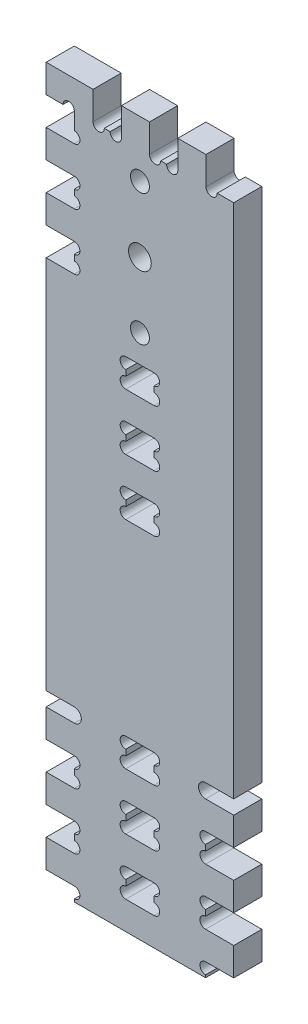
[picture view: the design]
ISO-10303-21;
HEADER;
FILE_DESCRIPTION(('STEP AP214'),'2;1');
FILE_NAME('part.step','',(''),(''),'','','');
FILE_SCHEMA(('AUTOMOTIVE_DESIGN { 1 0 10303 214 1 1 1 1 }'));
ENDSEC;
DATA;
#1=APPLICATION_CONTEXT('core data for automotive mechanical design processes');
#2=APPLICATION_PROTOCOL_DEFINITION('international standard','automotive_design',2000,#1);
#3=PRODUCT_CONTEXT('',#1,'mechanical');
#4=PRODUCT('Part','Part','',(#3));
#5=PRODUCT_RELATED_PRODUCT_CATEGORY('part','',(#4));
#6=PRODUCT_DEFINITION_FORMATION('','',#4);
#7=PRODUCT_DEFINITION_CONTEXT('part definition',#1,'design');
#8=PRODUCT_DEFINITION('design','',#6,#7);
#9=PRODUCT_DEFINITION_SHAPE('','',#8);
#10=(LENGTH_UNIT() NAMED_UNIT(*) SI_UNIT(.MILLI.,.METRE.));
#11=(NAMED_UNIT(*) PLANE_ANGLE_UNIT() SI_UNIT($,.RADIAN.));
#12=(NAMED_UNIT(*) SI_UNIT($,.STERADIAN.) SOLID_ANGLE_UNIT());
#13=UNCERTAINTY_MEASURE_WITH_UNIT(LENGTH_MEASURE(1.E-05),#10,'distance_accuracy_value','');
#14=(GEOMETRIC_REPRESENTATION_CONTEXT(3) GLOBAL_UNCERTAINTY_ASSIGNED_CONTEXT((#13)) GLOBAL_UNIT_ASSIGNED_CONTEXT((#10,
#11,#12)) REPRESENTATION_CONTEXT('',''));
#15=CARTESIAN_POINT('',(0.,0.,0.));
#16=DIRECTION('',(0.,0.,1.));
#17=DIRECTION('',(1.,0.,0.));
#18=AXIS2_PLACEMENT_3D('',#15,#16,#17);
#19=CARTESIAN_POINT('',(15.,86.35,15.));
#20=DIRECTION('',(0.,0.,1.));
#21=DIRECTION('',(1.,0.,0.));
#22=AXIS2_PLACEMENT_3D('',#19,#20,#21);
#23=PLANE('',#22);
#24=CARTESIAN_POINT('',(50.,315.270539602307,15.));
#25=DIRECTION('',(0.,0.,1.));
#26=DIRECTION('',(1.,0.,0.));
#27=AXIS2_PLACEMENT_3D('',#24,#25,#26);
#28=CIRCLE('',#27,6.05000000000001);
#29=CARTESIAN_POINT('',(56.05,315.270539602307,15.));
#30=VERTEX_POINT('',#29);
#31=EDGE_CURVE('E1719',#30,#30,#28,.T.);
#32=ORIENTED_EDGE('',*,*,#31,.F.);
#33=EDGE_LOOP('',(#32));
#34=FACE_BOUND('',#33,.T.);
#35=CARTESIAN_POINT('',(50.,280.270515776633,15.));
#36=DIRECTION('',(0.,0.,1.));
#37=DIRECTION('',(1.,0.,0.));
#38=AXIS2_PLACEMENT_3D('',#35,#36,#37);
#39=CIRCLE('',#38,5.05000000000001);
#40=CARTESIAN_POINT('',(55.05,280.270515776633,15.));
#41=VERTEX_POINT('',#40);
#42=EDGE_CURVE('E1714',#41,#41,#39,.T.);
#43=ORIENTED_EDGE('',*,*,#42,.F.);
#44=EDGE_LOOP('',(#43));
#45=FACE_BOUND('',#44,.T.);
#46=CARTESIAN_POINT('',(50.,350.270515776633,15.));
#47=DIRECTION('',(0.,0.,1.));
#48=DIRECTION('',(1.,0.,0.));
#49=AXIS2_PLACEMENT_3D('',#46,#47,#48);
#50=CIRCLE('',#49,5.05000000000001);
#51=CARTESIAN_POINT('',(55.05,350.270515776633,15.));
#52=VERTEX_POINT('',#51);
#53=EDGE_CURVE('E1708',#52,#52,#50,.T.);
#54=ORIENTED_EDGE('',*,*,#53,.F.);
#55=EDGE_LOOP('',(#54));
#56=FACE_BOUND('',#55,.T.);
#57=DIRECTION('',(0.,-1.,0.));
#58=VECTOR('',#57,1.);
#59=CARTESIAN_POINT('',(42.4499999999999,0.,15.));
#60=LINE('',#59,#58);
#61=CARTESIAN_POINT('',(42.4499999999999,84.3,15.));
#62=VERTEX_POINT('',#61);
#63=CARTESIAN_POINT('',(42.4499999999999,81.2,15.));
#64=VERTEX_POINT('',#63);
#65=EDGE_CURVE('E851',#62,#64,#60,.T.);
#66=ORIENTED_EDGE('',*,*,#65,.F.);
#67=CARTESIAN_POINT('',(42.4499999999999,87.3,15.));
#68=DIRECTION('',(0.,0.,1.));
#69=DIRECTION('',(1.,0.,0.));
#70=AXIS2_PLACEMENT_3D('',#67,#68,#69);
#71=CIRCLE('',#70,3.);
#72=CARTESIAN_POINT('',(42.4499999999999,90.3,15.));
#73=VERTEX_POINT('',#72);
#74=EDGE_CURVE('E854',#62,#73,#71,.F.);
#75=ORIENTED_EDGE('',*,*,#74,.T.);
#76=DIRECTION('',(1.,0.,0.));
#77=VECTOR('',#76,1.);
#78=CARTESIAN_POINT('',(0.,90.3,15.));
#79=LINE('',#78,#77);
#80=CARTESIAN_POINT('',(57.5499999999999,90.3,15.));
#81=VERTEX_POINT('',#80);
#82=EDGE_CURVE('E822',#73,#81,#79,.T.);
#83=ORIENTED_EDGE('',*,*,#82,.T.);
#84=CARTESIAN_POINT('',(57.5499999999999,87.3,15.));
#85=DIRECTION('',(0.,0.,1.));
#86=DIRECTION('',(1.,0.,0.));
#87=AXIS2_PLACEMENT_3D('',#84,#85,#86);
#88=CIRCLE('',#87,3.);
#89=CARTESIAN_POINT('',(57.5499999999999,84.3,15.));
#90=VERTEX_POINT('',#89);
#91=EDGE_CURVE('E836',#81,#90,#88,.F.);
#92=ORIENTED_EDGE('',*,*,#91,.T.);
#93=DIRECTION('',(0.,1.,0.));
#94=VECTOR('',#93,1.);
#95=CARTESIAN_POINT('',(57.5499999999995,-2.57634415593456E-13,15.));
#96=LINE('',#95,#94);
#97=CARTESIAN_POINT('',(57.5499999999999,81.2,15.));
#98=VERTEX_POINT('',#97);
#99=EDGE_CURVE('E839',#98,#90,#96,.T.);
#100=ORIENTED_EDGE('',*,*,#99,.F.);
#101=CARTESIAN_POINT('',(57.5499999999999,78.2,15.));
#102=DIRECTION('',(0.,0.,1.));
#103=DIRECTION('',(1.,0.,0.));
#104=AXIS2_PLACEMENT_3D('',#101,#102,#103);
#105=CIRCLE('',#104,3.);
#106=CARTESIAN_POINT('',(57.5499999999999,75.2,15.));
#107=VERTEX_POINT('',#106);
#108=EDGE_CURVE('E842',#98,#107,#105,.F.);
#109=ORIENTED_EDGE('',*,*,#108,.T.);
#110=DIRECTION('',(1.,0.,0.));
#111=VECTOR('',#110,1.);
#112=CARTESIAN_POINT('',(0.,75.2,15.));
#113=LINE('',#112,#111);
#114=CARTESIAN_POINT('',(42.4499999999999,75.2,15.));
#115=VERTEX_POINT('',#114);
#116=EDGE_CURVE('E845',#115,#107,#113,.T.);
#117=ORIENTED_EDGE('',*,*,#116,.F.);
#118=CARTESIAN_POINT('',(42.4499999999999,78.2,15.));
#119=DIRECTION('',(0.,0.,1.));
#120=DIRECTION('',(1.,0.,0.));
#121=AXIS2_PLACEMENT_3D('',#118,#119,#120);
#122=CIRCLE('',#121,3.);
#123=EDGE_CURVE('E848',#64,#115,#122,.T.);
#124=ORIENTED_EDGE('',*,*,#123,.F.);
#125=EDGE_LOOP('',(#66,#75,#83,#92,#100,#109,#117,#124));
#126=FACE_BOUND('',#125,.T.);
#127=DIRECTION('',(0.,-1.,0.));
#128=VECTOR('',#127,1.);
#129=CARTESIAN_POINT('',(42.4500000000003,0.,15.));
#130=LINE('',#129,#128);
#131=CARTESIAN_POINT('',(42.4499999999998,229.5,15.));
#132=VERTEX_POINT('',#131);
#133=CARTESIAN_POINT('',(42.4499999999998,226.4,15.));
#134=VERTEX_POINT('',#133);
#135=EDGE_CURVE('E933',#132,#134,#130,.T.);
#136=ORIENTED_EDGE('',*,*,#135,.F.);
#137=CARTESIAN_POINT('',(42.4499999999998,232.5,15.));
#138=DIRECTION('',(0.,0.,1.));
#139=DIRECTION('',(1.,0.,0.));
#140=AXIS2_PLACEMENT_3D('',#137,#138,#139);
#141=CIRCLE('',#140,3.);
#142=CARTESIAN_POINT('',(42.4499999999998,235.5,15.));
#143=VERTEX_POINT('',#142);
#144=EDGE_CURVE('E936',#132,#143,#141,.F.);
#145=ORIENTED_EDGE('',*,*,#144,.T.);
#146=DIRECTION('',(1.,0.,0.));
#147=VECTOR('',#146,1.);
#148=CARTESIAN_POINT('',(0.,235.5,15.));
#149=LINE('',#148,#147);
#150=CARTESIAN_POINT('',(57.5499999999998,235.5,15.));
#151=VERTEX_POINT('',#150);
#152=EDGE_CURVE('E902',#143,#151,#149,.T.);
#153=ORIENTED_EDGE('',*,*,#152,.T.);
#154=CARTESIAN_POINT('',(57.5499999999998,232.5,15.));
#155=DIRECTION('',(0.,0.,1.));
#156=DIRECTION('',(1.,0.,0.));
#157=AXIS2_PLACEMENT_3D('',#154,#155,#156);
#158=CIRCLE('',#157,2.99999999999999);
#159=CARTESIAN_POINT('',(57.5499999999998,229.5,15.));
#160=VERTEX_POINT('',#159);
#161=EDGE_CURVE('E918',#151,#160,#158,.F.);
#162=ORIENTED_EDGE('',*,*,#161,.T.);
#163=DIRECTION('',(0.,1.,0.));
#164=VECTOR('',#163,1.);
#165=CARTESIAN_POINT('',(57.5499999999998,0.,15.));
#166=LINE('',#165,#164);
#167=CARTESIAN_POINT('',(57.5499999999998,226.4,15.));
#168=VERTEX_POINT('',#167);
#169=EDGE_CURVE('E921',#168,#160,#166,.T.);
#170=ORIENTED_EDGE('',*,*,#169,.F.);
#171=CARTESIAN_POINT('',(57.5499999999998,223.4,15.));
#172=DIRECTION('',(0.,0.,1.));
#173=DIRECTION('',(1.,0.,0.));
#174=AXIS2_PLACEMENT_3D('',#171,#172,#173);
#175=CIRCLE('',#174,3.00000000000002);
#176=CARTESIAN_POINT('',(57.5499999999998,220.4,15.));
#177=VERTEX_POINT('',#176);
#178=EDGE_CURVE('E924',#168,#177,#175,.F.);
#179=ORIENTED_EDGE('',*,*,#178,.T.);
#180=DIRECTION('',(1.,0.,0.));
#181=VECTOR('',#180,1.);
#182=CARTESIAN_POINT('',(0.,220.4,15.));
#183=LINE('',#182,#181);
#184=CARTESIAN_POINT('',(42.4499999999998,220.4,15.));
#185=VERTEX_POINT('',#184);
#186=EDGE_CURVE('E927',#185,#177,#183,.T.);
#187=ORIENTED_EDGE('',*,*,#186,.F.);
#188=CARTESIAN_POINT('',(42.4499999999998,223.4,15.));
#189=DIRECTION('',(0.,0.,1.));
#190=DIRECTION('',(1.,0.,0.));
#191=AXIS2_PLACEMENT_3D('',#188,#189,#190);
#192=CIRCLE('',#191,3.);
#193=EDGE_CURVE('E930',#134,#185,#192,.T.);
#194=ORIENTED_EDGE('',*,*,#193,.F.);
#195=EDGE_LOOP('',(#136,#145,#153,#162,#170,#179,#187,#194));
#196=FACE_BOUND('',#195,.T.);
#197=DIRECTION('',(0.,-1.,0.));
#198=VECTOR('',#197,1.);
#199=CARTESIAN_POINT('',(42.45,0.,15.));
#200=LINE('',#199,#198);
#201=CARTESIAN_POINT('',(42.45,24.1,15.));
#202=VERTEX_POINT('',#201);
#203=CARTESIAN_POINT('',(42.45,21.,15.));
#204=VERTEX_POINT('',#203);
#205=EDGE_CURVE('E983',#202,#204,#200,.T.);
#206=ORIENTED_EDGE('',*,*,#205,.F.);
#207=CARTESIAN_POINT('',(42.45,27.1,15.));
#208=DIRECTION('',(0.,0.,1.));
#209=DIRECTION('',(1.,0.,0.));
#210=AXIS2_PLACEMENT_3D('',#207,#208,#209);
#211=CIRCLE('',#210,3.);
#212=CARTESIAN_POINT('',(42.45,30.1,15.));
#213=VERTEX_POINT('',#212);
#214=EDGE_CURVE('E980',#202,#213,#211,.F.);
#215=ORIENTED_EDGE('',*,*,#214,.T.);
#216=DIRECTION('',(1.,0.,0.));
#217=VECTOR('',#216,1.);
#218=CARTESIAN_POINT('',(0.,30.1,15.));
#219=LINE('',#218,#217);
#220=CARTESIAN_POINT('',(57.55,30.1,15.));
#221=VERTEX_POINT('',#220);
#222=EDGE_CURVE('E1001',#213,#221,#219,.T.);
#223=ORIENTED_EDGE('',*,*,#222,.T.);
#224=CARTESIAN_POINT('',(57.55,27.1,15.));
#225=DIRECTION('',(0.,0.,1.));
#226=DIRECTION('',(1.,0.,0.));
#227=AXIS2_PLACEMENT_3D('',#224,#225,#226);
#228=CIRCLE('',#227,3.);
#229=CARTESIAN_POINT('',(57.55,24.1,15.));
#230=VERTEX_POINT('',#229);
#231=EDGE_CURVE('E998',#221,#230,#228,.F.);
#232=ORIENTED_EDGE('',*,*,#231,.T.);
#233=DIRECTION('',(0.,1.,0.));
#234=VECTOR('',#233,1.);
#235=CARTESIAN_POINT('',(57.5500000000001,2.57634415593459E-13,15.));
#236=LINE('',#235,#234);
#237=CARTESIAN_POINT('',(57.55,21.,15.));
#238=VERTEX_POINT('',#237);
#239=EDGE_CURVE('E995',#238,#230,#236,.T.);
#240=ORIENTED_EDGE('',*,*,#239,.F.);
#241=CARTESIAN_POINT('',(57.55,18.,15.));
#242=DIRECTION('',(0.,0.,1.));
#243=DIRECTION('',(1.,0.,0.));
#244=AXIS2_PLACEMENT_3D('',#241,#242,#243);
#245=CIRCLE('',#244,3.);
#246=CARTESIAN_POINT('',(57.55,15.,15.));
#247=VERTEX_POINT('',#246);
#248=EDGE_CURVE('E992',#238,#247,#245,.F.);
#249=ORIENTED_EDGE('',*,*,#248,.T.);
#250=DIRECTION('',(1.,0.,0.));
#251=VECTOR('',#250,1.);
#252=CARTESIAN_POINT('',(0.,15.,15.));
#253=LINE('',#252,#251);
#254=CARTESIAN_POINT('',(42.45,15.,15.));
#255=VERTEX_POINT('',#254);
#256=EDGE_CURVE('E989',#255,#247,#253,.T.);
#257=ORIENTED_EDGE('',*,*,#256,.F.);
#258=CARTESIAN_POINT('',(42.45,18.,15.));
#259=DIRECTION('',(0.,0.,1.));
#260=DIRECTION('',(1.,0.,0.));
#261=AXIS2_PLACEMENT_3D('',#258,#259,#260);
#262=CIRCLE('',#261,3.);
#263=EDGE_CURVE('E986',#204,#255,#262,.T.);
#264=ORIENTED_EDGE('',*,*,#263,.F.);
#265=EDGE_LOOP('',(#206,#215,#223,#232,#240,#249,#257,#264));
#266=FACE_BOUND('',#265,.T.);
#267=CARTESIAN_POINT('',(15.,86.35,15.));
#268=DIRECTION('',(0.,0.,-1.));
#269=DIRECTION('',(1.,0.,0.));
#270=AXIS2_PLACEMENT_3D('',#267,#268,#269);
#271=CIRCLE('',#270,3.75);
#272=CARTESIAN_POINT('',(15.,90.1,15.));
#273=VERTEX_POINT('',#272);
#274=CARTESIAN_POINT('',(15.,82.6,15.));
#275=VERTEX_POINT('',#274);
#276=EDGE_CURVE('E1022',#273,#275,#271,.T.);
#277=ORIENTED_EDGE('',*,*,#276,.T.);
#278=DIRECTION('',(-1.,0.,0.));
#279=VECTOR('',#278,1.);
#280=CARTESIAN_POINT('',(0.,82.6,15.));
#281=LINE('',#280,#279);
#282=CARTESIAN_POINT('',(0.,82.6,15.));
#283=VERTEX_POINT('',#282);
#284=EDGE_CURVE('E1025',#275,#283,#281,.T.);
#285=ORIENTED_EDGE('',*,*,#284,.T.);
#286=DIRECTION('',(0.,-1.,0.));
#287=VECTOR('',#286,1.);
#288=CARTESIAN_POINT('',(0.,82.6,15.));
#289=LINE('',#288,#287);
#290=CARTESIAN_POINT('',(0.,67.6,15.));
#291=VERTEX_POINT('',#290);
#292=EDGE_CURVE('E1028',#283,#291,#289,.T.);
#293=ORIENTED_EDGE('',*,*,#292,.T.);
#294=DIRECTION('',(1.,0.,0.));
#295=VECTOR('',#294,1.);
#296=CARTESIAN_POINT('',(0.,67.6,15.));
#297=LINE('',#296,#295);
#298=CARTESIAN_POINT('',(15.,67.6,15.));
#299=VERTEX_POINT('',#298);
#300=EDGE_CURVE('E1030',#291,#299,#297,.T.);
#301=ORIENTED_EDGE('',*,*,#300,.T.);
#302=CARTESIAN_POINT('',(15.,64.6,15.));
#303=DIRECTION('',(0.,0.,-1.));
#304=DIRECTION('',(-1.,0.,0.));
#305=AXIS2_PLACEMENT_3D('',#302,#303,#304);
#306=CIRCLE('',#305,3.);
#307=CARTESIAN_POINT('',(15.,61.6,15.));
#308=VERTEX_POINT('',#307);
#309=EDGE_CURVE('E1032',#299,#308,#306,.T.);
#310=ORIENTED_EDGE('',*,*,#309,.T.);
#311=DIRECTION('',(0.,-1.,0.));
#312=VECTOR('',#311,1.);
#313=CARTESIAN_POINT('',(15.,61.6,15.));
#314=LINE('',#313,#312);
#315=CARTESIAN_POINT('',(15.,58.5,15.));
#316=VERTEX_POINT('',#315);
#317=EDGE_CURVE('E1034',#308,#316,#314,.T.);
#318=ORIENTED_EDGE('',*,*,#317,.T.);
#319=CARTESIAN_POINT('',(15.,55.5,15.));
#320=DIRECTION('',(0.,0.,-1.));
#321=DIRECTION('',(-1.,0.,0.));
#322=AXIS2_PLACEMENT_3D('',#319,#320,#321);
#323=CIRCLE('',#322,3.);
#324=CARTESIAN_POINT('',(15.,52.5,15.));
#325=VERTEX_POINT('',#324);
#326=EDGE_CURVE('E1036',#316,#325,#323,.T.);
#327=ORIENTED_EDGE('',*,*,#326,.T.);
#328=DIRECTION('',(-1.,0.,0.));
#329=VECTOR('',#328,1.);
#330=CARTESIAN_POINT('',(15.,52.5,15.));
#331=LINE('',#330,#329);
#332=CARTESIAN_POINT('',(0.,52.5,15.));
#333=VERTEX_POINT('',#332);
#334=EDGE_CURVE('E1038',#325,#333,#331,.T.);
#335=ORIENTED_EDGE('',*,*,#334,.T.);
#336=DIRECTION('',(0.,-1.,0.));
#337=VECTOR('',#336,1.);
#338=CARTESIAN_POINT('',(0.,52.5,15.));
#339=LINE('',#338,#337);
#340=CARTESIAN_POINT('',(0.,37.5,15.));
#341=VERTEX_POINT('',#340);
#342=EDGE_CURVE('E1040',#333,#341,#339,.T.);
#343=ORIENTED_EDGE('',*,*,#342,.T.);
#344=DIRECTION('',(1.,0.,0.));
#345=VECTOR('',#344,1.);
#346=CARTESIAN_POINT('',(0.,37.5,15.));
#347=LINE('',#346,#345);
#348=CARTESIAN_POINT('',(15.,37.5,15.));
#349=VERTEX_POINT('',#348);
#350=EDGE_CURVE('E1042',#341,#349,#347,.T.);
#351=ORIENTED_EDGE('',*,*,#350,.T.);
#352=CARTESIAN_POINT('',(15.,34.5,15.));
#353=DIRECTION('',(0.,0.,-1.));
#354=DIRECTION('',(-1.,0.,0.));
#355=AXIS2_PLACEMENT_3D('',#352,#353,#354);
#356=CIRCLE('',#355,3.);
#357=CARTESIAN_POINT('',(15.,31.5,15.));
#358=VERTEX_POINT('',#357);
#359=EDGE_CURVE('E1044',#349,#358,#356,.T.);
#360=ORIENTED_EDGE('',*,*,#359,.T.);
#361=DIRECTION('',(0.,-1.,0.));
#362=VECTOR('',#361,1.);
#363=CARTESIAN_POINT('',(15.,31.5,15.));
#364=LINE('',#363,#362);
#365=CARTESIAN_POINT('',(15.,28.4,15.));
#366=VERTEX_POINT('',#365);
#367=EDGE_CURVE('E1046',#358,#366,#364,.T.);
#368=ORIENTED_EDGE('',*,*,#367,.T.);
#369=CARTESIAN_POINT('',(15.,25.4,15.));
#370=DIRECTION('',(0.,0.,-1.));
#371=DIRECTION('',(-1.,0.,0.));
#372=AXIS2_PLACEMENT_3D('',#369,#370,#371);
#373=CIRCLE('',#372,3.);
#374=CARTESIAN_POINT('',(15.,22.4,15.));
#375=VERTEX_POINT('',#374);
#376=EDGE_CURVE('E1048',#366,#375,#373,.T.);
#377=ORIENTED_EDGE('',*,*,#376,.T.);
#378=DIRECTION('',(-1.,0.,0.));
#379=VECTOR('',#378,1.);
#380=CARTESIAN_POINT('',(15.,22.4,15.));
#381=LINE('',#380,#379);
#382=CARTESIAN_POINT('',(0.,22.4,15.));
#383=VERTEX_POINT('',#382);
#384=EDGE_CURVE('E1050',#375,#383,#381,.T.);
#385=ORIENTED_EDGE('',*,*,#384,.T.);
#386=DIRECTION('',(0.,-1.,0.));
#387=VECTOR('',#386,1.);
#388=CARTESIAN_POINT('',(0.,22.4,15.));
#389=LINE('',#388,#387);
#390=CARTESIAN_POINT('',(0.,7.4,15.));
#391=VERTEX_POINT('',#390);
#392=EDGE_CURVE('E1052',#383,#391,#389,.T.);
#393=ORIENTED_EDGE('',*,*,#392,.T.);
#394=DIRECTION('',(1.,0.,0.));
#395=VECTOR('',#394,1.);
#396=CARTESIAN_POINT('',(0.,7.4,15.));
#397=LINE('',#396,#395);
#398=CARTESIAN_POINT('',(15.,7.4,15.));
#399=VERTEX_POINT('',#398);
#400=EDGE_CURVE('E1054',#391,#399,#397,.T.);
#401=ORIENTED_EDGE('',*,*,#400,.T.);
#402=CARTESIAN_POINT('',(15.,4.4,15.));
#403=DIRECTION('',(0.,0.,-1.));
#404=DIRECTION('',(-1.,0.,0.));
#405=AXIS2_PLACEMENT_3D('',#402,#403,#404);
#406=CIRCLE('',#405,3.);
#407=CARTESIAN_POINT('',(15.,1.4,15.));
#408=VERTEX_POINT('',#407);
#409=EDGE_CURVE('E1056',#399,#408,#406,.T.);
#410=ORIENTED_EDGE('',*,*,#409,.T.);
#411=DIRECTION('',(0.,-1.,0.));
#412=VECTOR('',#411,1.);
#413=CARTESIAN_POINT('',(15.,1.4,15.));
#414=LINE('',#413,#412);
#415=CARTESIAN_POINT('',(15.,0.,15.));
#416=VERTEX_POINT('',#415);
#417=EDGE_CURVE('E1058',#408,#416,#414,.T.);
#418=ORIENTED_EDGE('',*,*,#417,.T.);
#419=DIRECTION('',(1.,0.,0.));
#420=VECTOR('',#419,1.);
#421=CARTESIAN_POINT('',(85.,0.,15.));
#422=LINE('',#421,#420);
#423=CARTESIAN_POINT('',(85.,0.,15.));
#424=VERTEX_POINT('',#423);
#425=EDGE_CURVE('E1060',#416,#424,#422,.T.);
#426=ORIENTED_EDGE('',*,*,#425,.T.);
#427=DIRECTION('',(0.,1.,0.));
#428=VECTOR('',#427,1.);
#429=CARTESIAN_POINT('',(85.,1.39999999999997,15.));
#430=LINE('',#429,#428);
#431=CARTESIAN_POINT('',(85.,1.39999999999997,15.));
#432=VERTEX_POINT('',#431);
#433=EDGE_CURVE('E1062',#424,#432,#430,.T.);
#434=ORIENTED_EDGE('',*,*,#433,.T.);
#435=CARTESIAN_POINT('',(85.,4.39999999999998,15.));
#436=DIRECTION('',(0.,0.,-1.));
#437=DIRECTION('',(1.,0.,0.));
#438=AXIS2_PLACEMENT_3D('',#435,#436,#437);
#439=CIRCLE('',#438,3.00000000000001);
#440=CARTESIAN_POINT('',(85.,7.39999999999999,15.));
#441=VERTEX_POINT('',#440);
#442=EDGE_CURVE('E1064',#432,#441,#439,.T.);
#443=ORIENTED_EDGE('',*,*,#442,.T.);
#444=DIRECTION('',(1.,0.,0.));
#445=VECTOR('',#444,1.);
#446=CARTESIAN_POINT('',(100.,7.4,15.));
#447=LINE('',#446,#445);
#448=CARTESIAN_POINT('',(100.,7.4,15.));
#449=VERTEX_POINT('',#448);
#450=EDGE_CURVE('E1066',#441,#449,#447,.T.);
#451=ORIENTED_EDGE('',*,*,#450,.T.);
#452=DIRECTION('',(0.,1.,0.));
#453=VECTOR('',#452,1.);
#454=CARTESIAN_POINT('',(100.,22.4,15.));
#455=LINE('',#454,#453);
#456=CARTESIAN_POINT('',(100.,22.4,15.));
#457=VERTEX_POINT('',#456);
#458=EDGE_CURVE('E1068',#449,#457,#455,.T.);
#459=ORIENTED_EDGE('',*,*,#458,.T.);
#460=DIRECTION('',(-1.,0.,0.));
#461=VECTOR('',#460,1.);
#462=CARTESIAN_POINT('',(85.,22.4,15.));
#463=LINE('',#462,#461);
#464=CARTESIAN_POINT('',(85.,22.4,15.));
#465=VERTEX_POINT('',#464);
#466=EDGE_CURVE('E1070',#457,#465,#463,.T.);
#467=ORIENTED_EDGE('',*,*,#466,.T.);
#468=CARTESIAN_POINT('',(85.0000000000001,25.4,15.));
#469=DIRECTION('',(0.,0.,-1.));
#470=DIRECTION('',(-1.,0.,0.));
#471=AXIS2_PLACEMENT_3D('',#468,#469,#470);
#472=CIRCLE('',#471,3.);
#473=CARTESIAN_POINT('',(85.0000000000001,28.4,15.));
#474=VERTEX_POINT('',#473);
#475=EDGE_CURVE('E1072',#465,#474,#472,.T.);
#476=ORIENTED_EDGE('',*,*,#475,.T.);
#477=DIRECTION('',(0.,1.,0.));
#478=VECTOR('',#477,1.);
#479=CARTESIAN_POINT('',(85.,31.5,15.));
#480=LINE('',#479,#478);
#481=CARTESIAN_POINT('',(85.,31.5,15.));
#482=VERTEX_POINT('',#481);
#483=EDGE_CURVE('E1074',#474,#482,#480,.T.);
#484=ORIENTED_EDGE('',*,*,#483,.T.);
#485=CARTESIAN_POINT('',(85.,34.5,15.));
#486=DIRECTION('',(0.,0.,-1.));
#487=DIRECTION('',(-1.,0.,0.));
#488=AXIS2_PLACEMENT_3D('',#485,#486,#487);
#489=CIRCLE('',#488,3.);
#490=CARTESIAN_POINT('',(85.,37.5,15.));
#491=VERTEX_POINT('',#490);
#492=EDGE_CURVE('E1076',#482,#491,#489,.T.);
#493=ORIENTED_EDGE('',*,*,#492,.T.);
#494=DIRECTION('',(1.,0.,0.));
#495=VECTOR('',#494,1.);
#496=CARTESIAN_POINT('',(100.,37.5,15.));
#497=LINE('',#496,#495);
#498=CARTESIAN_POINT('',(100.,37.5,15.));
#499=VERTEX_POINT('',#498);
#500=EDGE_CURVE('E1078',#491,#499,#497,.T.);
#501=ORIENTED_EDGE('',*,*,#500,.T.);
#502=DIRECTION('',(0.,1.,0.));
#503=VECTOR('',#502,1.);
#504=CARTESIAN_POINT('',(100.,52.5,15.));
#505=LINE('',#504,#503);
#506=CARTESIAN_POINT('',(100.,52.5,15.));
#507=VERTEX_POINT('',#506);
#508=EDGE_CURVE('E1080',#499,#507,#505,.T.);
#509=ORIENTED_EDGE('',*,*,#508,.T.);
#510=DIRECTION('',(-1.,0.,0.));
#511=VECTOR('',#510,1.);
#512=CARTESIAN_POINT('',(85.,52.5,15.));
#513=LINE('',#512,#511);
#514=CARTESIAN_POINT('',(85.,52.5,15.));
#515=VERTEX_POINT('',#514);
#516=EDGE_CURVE('E1082',#507,#515,#513,.T.);
#517=ORIENTED_EDGE('',*,*,#516,.T.);
#518=CARTESIAN_POINT('',(85.,55.5,15.));
#519=DIRECTION('',(0.,0.,-1.));
#520=DIRECTION('',(-1.,0.,0.));
#521=AXIS2_PLACEMENT_3D('',#518,#519,#520);
#522=CIRCLE('',#521,3.);
#523=CARTESIAN_POINT('',(85.,58.5,15.));
#524=VERTEX_POINT('',#523);
#525=EDGE_CURVE('E1084',#515,#524,#522,.T.);
#526=ORIENTED_EDGE('',*,*,#525,.T.);
#527=DIRECTION('',(0.,1.,0.));
#528=VECTOR('',#527,1.);
#529=CARTESIAN_POINT('',(85.,61.6,15.));
#530=LINE('',#529,#528);
#531=CARTESIAN_POINT('',(85.,61.6,15.));
#532=VERTEX_POINT('',#531);
#533=EDGE_CURVE('E1086',#524,#532,#530,.T.);
#534=ORIENTED_EDGE('',*,*,#533,.T.);
#535=CARTESIAN_POINT('',(85.,64.6,15.));
#536=DIRECTION('',(0.,0.,-1.));
#537=DIRECTION('',(-1.,0.,0.));
#538=AXIS2_PLACEMENT_3D('',#535,#536,#537);
#539=CIRCLE('',#538,3.);
#540=CARTESIAN_POINT('',(85.,67.6,15.));
#541=VERTEX_POINT('',#540);
#542=EDGE_CURVE('E1088',#532,#541,#539,.T.);
#543=ORIENTED_EDGE('',*,*,#542,.T.);
#544=DIRECTION('',(1.,0.,0.));
#545=VECTOR('',#544,1.);
#546=CARTESIAN_POINT('',(100.,67.6,15.));
#547=LINE('',#546,#545);
#548=CARTESIAN_POINT('',(100.,67.6,15.));
#549=VERTEX_POINT('',#548);
#550=EDGE_CURVE('E1090',#541,#549,#547,.T.);
#551=ORIENTED_EDGE('',*,*,#550,.T.);
#552=DIRECTION('',(0.,1.,0.));
#553=VECTOR('',#552,1.);
#554=CARTESIAN_POINT('',(100.,82.6,15.));
#555=LINE('',#554,#553);
#556=CARTESIAN_POINT('',(100.,82.6,15.));
#557=VERTEX_POINT('',#556);
#558=EDGE_CURVE('E1092',#549,#557,#555,.T.);
#559=ORIENTED_EDGE('',*,*,#558,.T.);
#560=DIRECTION('',(-1.,0.,0.));
#561=VECTOR('',#560,1.);
#562=CARTESIAN_POINT('',(85.,82.6,15.));
#563=LINE('',#562,#561);
#564=CARTESIAN_POINT('',(85.,82.6,15.));
#565=VERTEX_POINT('',#564);
#566=EDGE_CURVE('E1094',#557,#565,#563,.T.);
#567=ORIENTED_EDGE('',*,*,#566,.T.);
#568=CARTESIAN_POINT('',(85.,86.35,15.));
#569=DIRECTION('',(0.,0.,-1.));
#570=DIRECTION('',(-1.,0.,0.));
#571=AXIS2_PLACEMENT_3D('',#568,#569,#570);
#572=CIRCLE('',#571,3.75);
#573=CARTESIAN_POINT('',(85.,90.1,15.));
#574=VERTEX_POINT('',#573);
#575=EDGE_CURVE('E1096',#565,#574,#572,.T.);
#576=ORIENTED_EDGE('',*,*,#575,.T.);
#577=DIRECTION('',(1.,0.,0.));
#578=VECTOR('',#577,1.);
#579=CARTESIAN_POINT('',(85.,90.1,15.));
#580=LINE('',#579,#578);
#581=CARTESIAN_POINT('',(100.,90.1,15.));
#582=VERTEX_POINT('',#581);
#583=EDGE_CURVE('E1098',#574,#582,#580,.T.);
#584=ORIENTED_EDGE('',*,*,#583,.T.);
#585=DIRECTION('',(0.,1.,0.));
#586=VECTOR('',#585,1.);
#587=CARTESIAN_POINT('',(100.,90.1,15.));
#588=LINE('',#587,#586);
#589=CARTESIAN_POINT('',(100.,365.4,15.));
#590=VERTEX_POINT('',#589);
#591=EDGE_CURVE('E1100',#582,#590,#588,.T.);
#592=ORIENTED_EDGE('',*,*,#591,.T.);
#593=DIRECTION('',(-1.,0.,0.));
#594=VECTOR('',#593,1.);
#595=CARTESIAN_POINT('',(91.1999999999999,365.4,15.));
#596=LINE('',#595,#594);
#597=CARTESIAN_POINT('',(91.1999999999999,365.4,15.));
#598=VERTEX_POINT('',#597);
#599=EDGE_CURVE('E1102',#590,#598,#596,.T.);
#600=ORIENTED_EDGE('',*,*,#599,.T.);
#601=CARTESIAN_POINT('',(88.1999999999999,365.335267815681,15.));
#602=DIRECTION('',(0.,0.,-1.));
#603=DIRECTION('',(-1.,0.,0.));
#604=AXIS2_PLACEMENT_3D('',#601,#602,#603);
#605=CIRCLE('',#604,3.00069829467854);
#606=CARTESIAN_POINT('',(85.2,365.270535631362,15.));
#607=VERTEX_POINT('',#606);
#608=EDGE_CURVE('E1104',#598,#607,#605,.T.);
#609=ORIENTED_EDGE('',*,*,#608,.T.);
#610=DIRECTION('',(0.,1.,0.));
#611=VECTOR('',#610,1.);
#612=CARTESIAN_POINT('',(85.1999999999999,380.270535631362,15.));
#613=LINE('',#612,#611);
#614=CARTESIAN_POINT('',(85.1999999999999,380.270535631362,15.));
#615=VERTEX_POINT('',#614);
#616=EDGE_CURVE('E1106',#607,#615,#613,.T.);
#617=ORIENTED_EDGE('',*,*,#616,.T.);
#618=DIRECTION('',(-1.,0.,0.));
#619=VECTOR('',#618,1.);
#620=CARTESIAN_POINT('',(70.1999999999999,380.270535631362,15.));
#621=LINE('',#620,#619);
#622=CARTESIAN_POINT('',(70.1999999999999,380.270535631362,15.));
#623=VERTEX_POINT('',#622);
#624=EDGE_CURVE('E1108',#615,#623,#621,.T.);
#625=ORIENTED_EDGE('',*,*,#624,.T.);
#626=DIRECTION('',(0.,-1.,0.));
#627=VECTOR('',#626,1.);
#628=CARTESIAN_POINT('',(70.1999999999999,365.270535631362,15.));
#629=LINE('',#628,#627);
#630=CARTESIAN_POINT('',(70.1999999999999,365.270535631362,15.));
#631=VERTEX_POINT('',#630);
#632=EDGE_CURVE('E1110',#623,#631,#629,.T.);
#633=ORIENTED_EDGE('',*,*,#632,.T.);
#634=CARTESIAN_POINT('',(67.1999999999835,365.270535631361,15.));
#635=DIRECTION('',(0.,0.,-1.));
#636=DIRECTION('',(-1.,0.,0.));
#637=AXIS2_PLACEMENT_3D('',#634,#635,#636);
#638=CIRCLE('',#637,3.00000000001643);
#639=CARTESIAN_POINT('',(64.2000000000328,365.270515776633,15.));
#640=VERTEX_POINT('',#639);
#641=EDGE_CURVE('E1112',#631,#640,#638,.T.);
#642=ORIENTED_EDGE('',*,*,#641,.T.);
#643=DIRECTION('',(-1.,0.,0.));
#644=VECTOR('',#643,1.);
#645=CARTESIAN_POINT('',(61.0999999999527,365.270515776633,15.));
#646=LINE('',#645,#644);
#647=CARTESIAN_POINT('',(61.0999999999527,365.270515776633,15.));
#648=VERTEX_POINT('',#647);
#649=EDGE_CURVE('E1114',#640,#648,#646,.T.);
#650=ORIENTED_EDGE('',*,*,#649,.T.);
#651=CARTESIAN_POINT('',(58.1000000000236,365.270539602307,15.));
#652=DIRECTION('',(0.,0.,-1.));
#653=DIRECTION('',(-1.,0.,0.));
#654=AXIS2_PLACEMENT_3D('',#651,#652,#653);
#655=CIRCLE('',#654,3.00000000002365);
#656=CARTESIAN_POINT('',(55.1,365.270539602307,15.));
#657=VERTEX_POINT('',#656);
#658=EDGE_CURVE('E1116',#648,#657,#655,.T.);
#659=ORIENTED_EDGE('',*,*,#658,.T.);
#660=DIRECTION('',(0.,1.,0.));
#661=VECTOR('',#660,1.);
#662=CARTESIAN_POINT('',(55.1,380.270539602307,15.));
#663=LINE('',#662,#661);
#664=CARTESIAN_POINT('',(55.1,380.270539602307,15.));
#665=VERTEX_POINT('',#664);
#666=EDGE_CURVE('E1118',#657,#665,#663,.T.);
#667=ORIENTED_EDGE('',*,*,#666,.T.);
#668=DIRECTION('',(-1.,0.,0.));
#669=VECTOR('',#668,1.);
#670=CARTESIAN_POINT('',(40.1,380.270539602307,15.));
#671=LINE('',#670,#669);
#672=CARTESIAN_POINT('',(40.1,380.270539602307,15.));
#673=VERTEX_POINT('',#672);
#674=EDGE_CURVE('E1120',#665,#673,#671,.T.);
#675=ORIENTED_EDGE('',*,*,#674,.T.);
#676=DIRECTION('',(0.,-1.,0.));
#677=VECTOR('',#676,1.);
#678=CARTESIAN_POINT('',(40.1,365.270539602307,15.));
#679=LINE('',#678,#677);
#680=CARTESIAN_POINT('',(40.1,365.270539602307,15.));
#681=VERTEX_POINT('',#680);
#682=EDGE_CURVE('E1122',#673,#681,#679,.T.);
#683=ORIENTED_EDGE('',*,*,#682,.T.);
#684=CARTESIAN_POINT('',(37.0999999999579,365.270539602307,15.));
#685=DIRECTION('',(0.,0.,-1.));
#686=DIRECTION('',(-1.,0.,0.));
#687=AXIS2_PLACEMENT_3D('',#684,#685,#686);
#688=CIRCLE('',#687,3.00000000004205);
#689=CARTESIAN_POINT('',(34.1000000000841,365.270507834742,15.));
#690=VERTEX_POINT('',#689);
#691=EDGE_CURVE('E1124',#681,#690,#688,.T.);
#692=ORIENTED_EDGE('',*,*,#691,.T.);
#693=DIRECTION('',(-1.,0.,0.));
#694=VECTOR('',#693,1.);
#695=CARTESIAN_POINT('',(30.9999999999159,365.270507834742,15.));
#696=LINE('',#695,#694);
#697=CARTESIAN_POINT('',(30.9999999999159,365.270507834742,15.));
#698=VERTEX_POINT('',#697);
#699=EDGE_CURVE('E1126',#690,#698,#696,.T.);
#700=ORIENTED_EDGE('',*,*,#699,.T.);
#701=CARTESIAN_POINT('',(28.0000000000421,365.270539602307,15.));
#702=DIRECTION('',(0.,0.,-1.));
#703=DIRECTION('',(-1.,0.,0.));
#704=AXIS2_PLACEMENT_3D('',#701,#702,#703);
#705=CIRCLE('',#704,3.00000000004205);
#706=CARTESIAN_POINT('',(25.,365.270539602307,15.));
#707=VERTEX_POINT('',#706);
#708=EDGE_CURVE('E1128',#698,#707,#705,.T.);
#709=ORIENTED_EDGE('',*,*,#708,.T.);
#710=DIRECTION('',(0.,1.,0.));
#711=VECTOR('',#710,1.);
#712=CARTESIAN_POINT('',(25.,365.270539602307,15.));
#713=LINE('',#712,#711);
#714=CARTESIAN_POINT('',(25.,380.270539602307,15.));
#715=VERTEX_POINT('',#714);
#716=EDGE_CURVE('E1130',#707,#715,#713,.T.);
#717=ORIENTED_EDGE('',*,*,#716,.T.);
#718=DIRECTION('',(-1.,0.,0.));
#719=VECTOR('',#718,1.);
#720=CARTESIAN_POINT('',(0.,380.270539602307,15.));
#721=LINE('',#720,#719);
#722=CARTESIAN_POINT('',(0.,380.270539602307,15.));
#723=VERTEX_POINT('',#722);
#724=EDGE_CURVE('E1132',#715,#723,#721,.T.);
#725=ORIENTED_EDGE('',*,*,#724,.T.);
#726=DIRECTION('',(0.,-1.,0.));
#727=VECTOR('',#726,1.);
#728=CARTESIAN_POINT('',(0.,365.270539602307,15.));
#729=LINE('',#728,#727);
#730=CARTESIAN_POINT('',(0.,365.270539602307,15.));
#731=VERTEX_POINT('',#730);
#732=EDGE_CURVE('E1134',#723,#731,#729,.T.);
#733=ORIENTED_EDGE('',*,*,#732,.T.);
#734=DIRECTION('',(1.,0.,0.));
#735=VECTOR('',#734,1.);
#736=CARTESIAN_POINT('',(0.,365.270539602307,15.));
#737=LINE('',#736,#735);
#738=CARTESIAN_POINT('',(9.,365.270539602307,15.));
#739=VERTEX_POINT('',#738);
#740=EDGE_CURVE('E1136',#731,#739,#737,.T.);
#741=ORIENTED_EDGE('',*,*,#740,.T.);
#742=CARTESIAN_POINT('',(12.,365.270539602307,15.));
#743=DIRECTION('',(0.,0.,-1.));
#744=DIRECTION('',(1.,0.,0.));
#745=AXIS2_PLACEMENT_3D('',#742,#743,#744);
#746=CIRCLE('',#745,3.);
#747=CARTESIAN_POINT('',(15.,365.270539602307,15.));
#748=VERTEX_POINT('',#747);
#749=EDGE_CURVE('E1138',#739,#748,#746,.T.);
#750=ORIENTED_EDGE('',*,*,#749,.T.);
#751=DIRECTION('',(0.,-1.,0.));
#752=VECTOR('',#751,1.);
#753=CARTESIAN_POINT('',(15.,356.170539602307,15.));
#754=LINE('',#753,#752);
#755=CARTESIAN_POINT('',(15.,356.170539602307,15.));
#756=VERTEX_POINT('',#755);
#757=EDGE_CURVE('E1140',#748,#756,#754,.T.);
#758=ORIENTED_EDGE('',*,*,#757,.T.);
#759=CARTESIAN_POINT('',(15.,353.170539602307,15.));
#760=DIRECTION('',(0.,0.,-1.));
#761=DIRECTION('',(-1.,0.,0.));
#762=AXIS2_PLACEMENT_3D('',#759,#760,#761);
#763=CIRCLE('',#762,3.);
#764=CARTESIAN_POINT('',(15.,350.170539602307,15.));
#765=VERTEX_POINT('',#764);
#766=EDGE_CURVE('E1142',#756,#765,#763,.T.);
#767=ORIENTED_EDGE('',*,*,#766,.T.);
#768=DIRECTION('',(-1.,0.,0.));
#769=VECTOR('',#768,1.);
#770=CARTESIAN_POINT('',(15.,350.170539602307,15.));
#771=LINE('',#770,#769);
#772=CARTESIAN_POINT('',(0.,350.170539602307,15.));
#773=VERTEX_POINT('',#772);
#774=EDGE_CURVE('E1144',#765,#773,#771,.T.);
#775=ORIENTED_EDGE('',*,*,#774,.T.);
#776=DIRECTION('',(0.,-1.,0.));
#777=VECTOR('',#776,1.);
#778=CARTESIAN_POINT('',(0.,335.170539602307,15.));
#779=LINE('',#778,#777);
#780=CARTESIAN_POINT('',(0.,335.170539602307,15.));
#781=VERTEX_POINT('',#780);
#782=EDGE_CURVE('E1146',#773,#781,#779,.T.);
#783=ORIENTED_EDGE('',*,*,#782,.T.);
#784=DIRECTION('',(1.,0.,0.));
#785=VECTOR('',#784,1.);
#786=CARTESIAN_POINT('',(0.,335.170539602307,15.));
#787=LINE('',#786,#785);
#788=CARTESIAN_POINT('',(15.,335.170539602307,15.));
#789=VERTEX_POINT('',#788);
#790=EDGE_CURVE('E1148',#781,#789,#787,.T.);
#791=ORIENTED_EDGE('',*,*,#790,.T.);
#792=CARTESIAN_POINT('',(15.,332.170539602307,15.));
#793=DIRECTION('',(0.,0.,-1.));
#794=DIRECTION('',(-1.,0.,0.));
#795=AXIS2_PLACEMENT_3D('',#792,#793,#794);
#796=CIRCLE('',#795,3.);
#797=CARTESIAN_POINT('',(15.,329.170539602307,15.));
#798=VERTEX_POINT('',#797);
#799=EDGE_CURVE('E1150',#789,#798,#796,.T.);
#800=ORIENTED_EDGE('',*,*,#799,.T.);
#801=DIRECTION('',(0.,-1.,0.));
#802=VECTOR('',#801,1.);
#803=CARTESIAN_POINT('',(15.,326.070539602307,15.));
#804=LINE('',#803,#802);
#805=CARTESIAN_POINT('',(15.,326.070539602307,15.));
#806=VERTEX_POINT('',#805);
#807=EDGE_CURVE('E1152',#798,#806,#804,.T.);
#808=ORIENTED_EDGE('',*,*,#807,.T.);
#809=CARTESIAN_POINT('',(15.,323.070539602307,15.));
#810=DIRECTION('',(0.,0.,-1.));
#811=DIRECTION('',(-1.,0.,0.));
#812=AXIS2_PLACEMENT_3D('',#809,#810,#811);
#813=CIRCLE('',#812,3.);
#814=CARTESIAN_POINT('',(15.,320.070539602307,15.));
#815=VERTEX_POINT('',#814);
#816=EDGE_CURVE('E1154',#806,#815,#813,.T.);
#817=ORIENTED_EDGE('',*,*,#816,.T.);
#818=DIRECTION('',(-1.,0.,0.));
#819=VECTOR('',#818,1.);
#820=CARTESIAN_POINT('',(15.,320.070539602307,15.));
#821=LINE('',#820,#819);
#822=CARTESIAN_POINT('',(0.,320.070539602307,15.));
#823=VERTEX_POINT('',#822);
#824=EDGE_CURVE('E1156',#815,#823,#821,.T.);
#825=ORIENTED_EDGE('',*,*,#824,.T.);
#826=DIRECTION('',(0.,-1.,0.));
#827=VECTOR('',#826,1.);
#828=CARTESIAN_POINT('',(0.,305.070539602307,15.));
#829=LINE('',#828,#827);
#830=CARTESIAN_POINT('',(0.,305.070539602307,15.));
#831=VERTEX_POINT('',#830);
#832=EDGE_CURVE('E1158',#823,#831,#829,.T.);
#833=ORIENTED_EDGE('',*,*,#832,.T.);
#834=DIRECTION('',(1.,0.,0.));
#835=VECTOR('',#834,1.);
#836=CARTESIAN_POINT('',(0.,305.070539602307,15.));
#837=LINE('',#836,#835);
#838=CARTESIAN_POINT('',(15.,305.070539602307,15.));
#839=VERTEX_POINT('',#838);
#840=EDGE_CURVE('E1160',#831,#839,#837,.T.);
#841=ORIENTED_EDGE('',*,*,#840,.T.);
#842=CARTESIAN_POINT('',(15.,302.070539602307,15.));
#843=DIRECTION('',(0.,0.,-1.));
#844=DIRECTION('',(-1.,0.,0.));
#845=AXIS2_PLACEMENT_3D('',#842,#843,#844);
#846=CIRCLE('',#845,3.);
#847=CARTESIAN_POINT('',(15.,299.070539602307,15.));
#848=VERTEX_POINT('',#847);
#849=EDGE_CURVE('E1162',#839,#848,#846,.T.);
#850=ORIENTED_EDGE('',*,*,#849,.T.);
#851=DIRECTION('',(0.,-1.,0.));
#852=VECTOR('',#851,1.);
#853=CARTESIAN_POINT('',(15.,295.970539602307,15.));
#854=LINE('',#853,#852);
#855=CARTESIAN_POINT('',(15.,295.970539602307,15.));
#856=VERTEX_POINT('',#855);
#857=EDGE_CURVE('E1164',#848,#856,#854,.T.);
#858=ORIENTED_EDGE('',*,*,#857,.T.);
#859=CARTESIAN_POINT('',(15.,292.970539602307,15.));
#860=DIRECTION('',(0.,0.,-1.));
#861=DIRECTION('',(-1.,0.,0.));
#862=AXIS2_PLACEMENT_3D('',#859,#860,#861);
#863=CIRCLE('',#862,3.);
#864=CARTESIAN_POINT('',(15.,289.970539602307,15.));
#865=VERTEX_POINT('',#864);
#866=EDGE_CURVE('E1166',#856,#865,#863,.T.);
#867=ORIENTED_EDGE('',*,*,#866,.T.);
#868=DIRECTION('',(-1.,0.,0.));
#869=VECTOR('',#868,1.);
#870=CARTESIAN_POINT('',(15.,289.970539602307,15.));
#871=LINE('',#870,#869);
#872=CARTESIAN_POINT('',(0.,289.970539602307,15.));
#873=VERTEX_POINT('',#872);
#874=EDGE_CURVE('E1168',#865,#873,#871,.T.);
#875=ORIENTED_EDGE('',*,*,#874,.T.);
#876=DIRECTION('',(0.,-1.,0.));
#877=VECTOR('',#876,1.);
#878=CARTESIAN_POINT('',(0.,289.970539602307,15.));
#879=LINE('',#878,#877);
#880=CARTESIAN_POINT('',(0.,90.1,15.));
#881=VERTEX_POINT('',#880);
#882=EDGE_CURVE('E1170',#873,#881,#879,.T.);
#883=ORIENTED_EDGE('',*,*,#882,.T.);
#884=DIRECTION('',(1.,0.,0.));
#885=VECTOR('',#884,1.);
#886=CARTESIAN_POINT('',(0.,90.1,15.));
#887=LINE('',#886,#885);
#888=EDGE_CURVE('E1172',#881,#273,#887,.T.);
#889=ORIENTED_EDGE('',*,*,#888,.T.);
#890=EDGE_LOOP('',(#277,#285,#293,#301,#310,#318,#327,#335,#343,#351,#360,#368,#377,#385,#393,
#401,#410,#418,#426,#434,#443,#451,#459,#467,#476,#484,#493,#501,#509,#517,#526,#534,#543,#551,
#559,#567,#576,#584,#592,#600,#609,#617,#625,#633,#642,#650,#659,#667,#675,#683,#692,#700,#709,
#717,#725,#733,#741,#750,#758,#767,#775,#783,#791,#800,#808,#817,#825,#833,#841,#850,#858,#867,
#875,#883,#889));
#891=FACE_BOUND('',#890,.T.);
#892=DIRECTION('',(0.,-1.,0.));
#893=VECTOR('',#892,1.);
#894=CARTESIAN_POINT('',(42.4500000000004,0.,15.));
#895=LINE('',#894,#893);
#896=CARTESIAN_POINT('',(42.4499999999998,259.6,15.));
#897=VERTEX_POINT('',#896);
#898=CARTESIAN_POINT('',(42.4499999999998,256.5,15.));
#899=VERTEX_POINT('',#898);
#900=EDGE_CURVE('E974',#897,#899,#895,.T.);
#901=ORIENTED_EDGE('',*,*,#900,.F.);
#902=CARTESIAN_POINT('',(42.4499999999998,262.6,15.));
#903=DIRECTION('',(0.,0.,1.));
#904=DIRECTION('',(1.,0.,0.));
#905=AXIS2_PLACEMENT_3D('',#902,#903,#904);
#906=CIRCLE('',#905,3.);
#907=CARTESIAN_POINT('',(42.4499999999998,265.6,15.));
#908=VERTEX_POINT('',#907);
#909=EDGE_CURVE('E977',#897,#908,#906,.F.);
#910=ORIENTED_EDGE('',*,*,#909,.T.);
#911=DIRECTION('',(1.,0.,0.));
#912=VECTOR('',#911,1.);
#913=CARTESIAN_POINT('',(0.,265.6,15.));
#914=LINE('',#913,#912);
#915=CARTESIAN_POINT('',(57.5499999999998,265.6,15.));
#916=VERTEX_POINT('',#915);
#917=EDGE_CURVE('E943',#908,#916,#914,.T.);
#918=ORIENTED_EDGE('',*,*,#917,.T.);
#919=CARTESIAN_POINT('',(57.5499999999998,262.6,15.));
#920=DIRECTION('',(0.,0.,1.));
#921=DIRECTION('',(1.,0.,0.));
#922=AXIS2_PLACEMENT_3D('',#919,#920,#921);
#923=CIRCLE('',#922,3.);
#924=CARTESIAN_POINT('',(57.5499999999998,259.6,15.));
#925=VERTEX_POINT('',#924);
#926=EDGE_CURVE('E959',#916,#925,#923,.F.);
#927=ORIENTED_EDGE('',*,*,#926,.T.);
#928=DIRECTION('',(0.,1.,0.));
#929=VECTOR('',#928,1.);
#930=CARTESIAN_POINT('',(57.5499999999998,0.,15.));
#931=LINE('',#930,#929);
#932=CARTESIAN_POINT('',(57.5499999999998,256.5,15.));
#933=VERTEX_POINT('',#932);
#934=EDGE_CURVE('E962',#933,#925,#931,.T.);
#935=ORIENTED_EDGE('',*,*,#934,.F.);
#936=CARTESIAN_POINT('',(57.5499999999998,253.5,15.));
#937=DIRECTION('',(0.,0.,1.));
#938=DIRECTION('',(1.,0.,0.));
#939=AXIS2_PLACEMENT_3D('',#936,#937,#938);
#940=CIRCLE('',#939,3.);
#941=CARTESIAN_POINT('',(57.5499999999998,250.5,15.));
#942=VERTEX_POINT('',#941);
#943=EDGE_CURVE('E965',#933,#942,#940,.F.);
#944=ORIENTED_EDGE('',*,*,#943,.T.);
#945=DIRECTION('',(1.,0.,0.));
#946=VECTOR('',#945,1.);
#947=CARTESIAN_POINT('',(0.,250.5,15.));
#948=LINE('',#947,#946);
#949=CARTESIAN_POINT('',(42.4499999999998,250.5,15.));
#950=VERTEX_POINT('',#949);
#951=EDGE_CURVE('E968',#950,#942,#948,.T.);
#952=ORIENTED_EDGE('',*,*,#951,.F.);
#953=CARTESIAN_POINT('',(42.4499999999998,253.5,15.));
#954=DIRECTION('',(0.,0.,1.));
#955=DIRECTION('',(1.,0.,0.));
#956=AXIS2_PLACEMENT_3D('',#953,#954,#955);
#957=CIRCLE('',#956,3.);
#958=EDGE_CURVE('E971',#899,#950,#957,.T.);
#959=ORIENTED_EDGE('',*,*,#958,.F.);
#960=EDGE_LOOP('',(#901,#910,#918,#927,#935,#944,#952,#959));
#961=FACE_BOUND('',#960,.T.);
#962=DIRECTION('',(0.,-1.,0.));
#963=VECTOR('',#962,1.);
#964=CARTESIAN_POINT('',(42.45,0.,15.));
#965=LINE('',#964,#963);
#966=CARTESIAN_POINT('',(42.4499999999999,54.2,15.));
#967=VERTEX_POINT('',#966);
#968=CARTESIAN_POINT('',(42.4499999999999,51.1,15.));
#969=VERTEX_POINT('',#968);
#970=EDGE_CURVE('E892',#967,#969,#965,.T.);
#971=ORIENTED_EDGE('',*,*,#970,.F.);
#972=CARTESIAN_POINT('',(42.4499999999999,57.2,15.));
#973=DIRECTION('',(0.,0.,1.));
#974=DIRECTION('',(1.,0.,0.));
#975=AXIS2_PLACEMENT_3D('',#972,#973,#974);
#976=CIRCLE('',#975,3.);
#977=CARTESIAN_POINT('',(42.4499999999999,60.2,15.));
#978=VERTEX_POINT('',#977);
#979=EDGE_CURVE('E895',#967,#978,#976,.F.);
#980=ORIENTED_EDGE('',*,*,#979,.T.);
#981=DIRECTION('',(1.,0.,0.));
#982=VECTOR('',#981,1.);
#983=CARTESIAN_POINT('',(0.,60.2,15.));
#984=LINE('',#983,#982);
#985=CARTESIAN_POINT('',(57.5499999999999,60.2,15.));
#986=VERTEX_POINT('',#985);
#987=EDGE_CURVE('E861',#978,#986,#984,.T.);
#988=ORIENTED_EDGE('',*,*,#987,.T.);
#989=CARTESIAN_POINT('',(57.5499999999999,57.2,15.));
#990=DIRECTION('',(0.,0.,1.));
#991=DIRECTION('',(1.,0.,0.));
#992=AXIS2_PLACEMENT_3D('',#989,#990,#991);
#993=CIRCLE('',#992,3.);
#994=CARTESIAN_POINT('',(57.5499999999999,54.2,15.));
#995=VERTEX_POINT('',#994);
#996=EDGE_CURVE('E877',#986,#995,#993,.F.);
#997=ORIENTED_EDGE('',*,*,#996,.T.);
#998=DIRECTION('',(0.,1.,0.));
#999=VECTOR('',#998,1.);
#1000=CARTESIAN_POINT('',(57.5499999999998,-1.28817207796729E-13,15.));
#1001=LINE('',#1000,#999);
#1002=CARTESIAN_POINT('',(57.5499999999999,51.1,15.));
#1003=VERTEX_POINT('',#1002);
#1004=EDGE_CURVE('E880',#1003,#995,#1001,.T.);
#1005=ORIENTED_EDGE('',*,*,#1004,.F.);
#1006=CARTESIAN_POINT('',(57.5499999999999,48.1,15.));
#1007=DIRECTION('',(0.,0.,1.));
#1008=DIRECTION('',(1.,0.,0.));
#1009=AXIS2_PLACEMENT_3D('',#1006,#1007,#1008);
#1010=CIRCLE('',#1009,3.);
#1011=CARTESIAN_POINT('',(57.5499999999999,45.1,15.));
#1012=VERTEX_POINT('',#1011);
#1013=EDGE_CURVE('E883',#1003,#1012,#1010,.F.);
#1014=ORIENTED_EDGE('',*,*,#1013,.T.);
#1015=DIRECTION('',(1.,0.,0.));
#1016=VECTOR('',#1015,1.);
#1017=CARTESIAN_POINT('',(0.,45.1,15.));
#1018=LINE('',#1017,#1016);
#1019=CARTESIAN_POINT('',(42.4499999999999,45.1,15.));
#1020=VERTEX_POINT('',#1019);
#1021=EDGE_CURVE('E886',#1020,#1012,#1018,.T.);
#1022=ORIENTED_EDGE('',*,*,#1021,.F.);
#1023=CARTESIAN_POINT('',(42.4499999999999,48.1,15.));
#1024=DIRECTION('',(0.,0.,1.));
#1025=DIRECTION('',(1.,0.,0.));
#1026=AXIS2_PLACEMENT_3D('',#1023,#1024,#1025);
#1027=CIRCLE('',#1026,3.);
#1028=EDGE_CURVE('E889',#969,#1020,#1027,.T.);
#1029=ORIENTED_EDGE('',*,*,#1028,.F.);
#1030=EDGE_LOOP('',(#971,#980,#988,#997,#1005,#1014,#1022,#1029));
#1031=FACE_BOUND('',#1030,.T.);
#1032=DIRECTION('',(0.,-1.,0.));
#1033=VECTOR('',#1032,1.);
#1034=CARTESIAN_POINT('',(42.4500000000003,0.,15.));
#1035=LINE('',#1034,#1033);
#1036=CARTESIAN_POINT('',(42.4499999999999,199.4,15.));
#1037=VERTEX_POINT('',#1036);
#1038=CARTESIAN_POINT('',(42.4499999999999,196.3,15.));
#1039=VERTEX_POINT('',#1038);
#1040=EDGE_CURVE('E810',#1037,#1039,#1035,.T.);
#1041=ORIENTED_EDGE('',*,*,#1040,.F.);
#1042=CARTESIAN_POINT('',(42.4499999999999,202.4,15.));
#1043=DIRECTION('',(0.,0.,1.));
#1044=DIRECTION('',(1.,0.,0.));
#1045=AXIS2_PLACEMENT_3D('',#1042,#1043,#1044);
#1046=CIRCLE('',#1045,3.);
#1047=CARTESIAN_POINT('',(42.4499999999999,205.4,15.));
#1048=VERTEX_POINT('',#1047);
#1049=EDGE_CURVE('E51',#1037,#1048,#1046,.F.);
#1050=ORIENTED_EDGE('',*,*,#1049,.T.);
#1051=DIRECTION('',(1.,0.,0.));
#1052=VECTOR('',#1051,1.);
#1053=CARTESIAN_POINT('',(0.,205.4,15.));
#1054=LINE('',#1053,#1052);
#1055=CARTESIAN_POINT('',(57.5499999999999,205.4,15.));
#1056=VERTEX_POINT('',#1055);
#1057=EDGE_CURVE('E799',#1048,#1056,#1054,.T.);
#1058=ORIENTED_EDGE('',*,*,#1057,.T.);
#1059=CARTESIAN_POINT('',(57.5499999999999,202.4,15.));
#1060=DIRECTION('',(0.,0.,1.));
#1061=DIRECTION('',(1.,0.,0.));
#1062=AXIS2_PLACEMENT_3D('',#1059,#1060,#1061);
#1063=CIRCLE('',#1062,3.);
#1064=CARTESIAN_POINT('',(57.5499999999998,199.4,15.));
#1065=VERTEX_POINT('',#1064);
#1066=EDGE_CURVE('E805',#1056,#1065,#1063,.F.);
#1067=ORIENTED_EDGE('',*,*,#1066,.T.);
#1068=DIRECTION('',(0.,1.,0.));
#1069=VECTOR('',#1068,1.);
#1070=CARTESIAN_POINT('',(57.5499999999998,0.,15.));
#1071=LINE('',#1070,#1069);
#1072=CARTESIAN_POINT('',(57.5499999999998,196.3,15.));
#1073=VERTEX_POINT('',#1072);
#1074=EDGE_CURVE('E1693',#1073,#1065,#1071,.T.);
#1075=ORIENTED_EDGE('',*,*,#1074,.F.);
#1076=CARTESIAN_POINT('',(57.5499999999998,193.3,15.));
#1077=DIRECTION('',(0.,0.,1.));
#1078=DIRECTION('',(1.,0.,0.));
#1079=AXIS2_PLACEMENT_3D('',#1076,#1077,#1078);
#1080=CIRCLE('',#1079,2.99999999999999);
#1081=CARTESIAN_POINT('',(57.5499999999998,190.3,15.));
#1082=VERTEX_POINT('',#1081);
#1083=EDGE_CURVE('E1683',#1073,#1082,#1080,.F.);
#1084=ORIENTED_EDGE('',*,*,#1083,.T.);
#1085=DIRECTION('',(1.,0.,0.));
#1086=VECTOR('',#1085,1.);
#1087=CARTESIAN_POINT('',(-3.49793777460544E-13,190.3,15.));
#1088=LINE('',#1087,#1086);
#1089=CARTESIAN_POINT('',(42.4499999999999,190.3,15.));
#1090=VERTEX_POINT('',#1089);
#1091=EDGE_CURVE('E1696',#1090,#1082,#1088,.T.);
#1092=ORIENTED_EDGE('',*,*,#1091,.F.);
#1093=CARTESIAN_POINT('',(42.4499999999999,193.3,15.));
#1094=DIRECTION('',(0.,0.,1.));
#1095=DIRECTION('',(1.,0.,0.));
#1096=AXIS2_PLACEMENT_3D('',#1093,#1094,#1095);
#1097=CIRCLE('',#1096,3.);
#1098=EDGE_CURVE('E815',#1039,#1090,#1097,.T.);
#1099=ORIENTED_EDGE('',*,*,#1098,.F.);
#1100=EDGE_LOOP('',(#1041,#1050,#1058,#1067,#1075,#1084,#1092,#1099));
#1101=FACE_BOUND('',#1100,.T.);
#1102=ADVANCED_FACE('F35',(#34,#45,#56,#126,#196,#266,#891,#961,#1031,#1101),#23,.T.);
#1103=CARTESIAN_POINT('',(15.,86.35,0.));
#1104=DIRECTION('',(0.,0.,1.));
#1105=DIRECTION('',(1.,0.,0.));
#1106=AXIS2_PLACEMENT_3D('',#1103,#1104,#1105);
#1107=PLANE('',#1106);
#1108=CARTESIAN_POINT('',(50.,315.270539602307,0.));
#1109=DIRECTION('',(0.,0.,1.));
#1110=DIRECTION('',(1.,0.,0.));
#1111=AXIS2_PLACEMENT_3D('',#1108,#1109,#1110);
#1112=CIRCLE('',#1111,6.05000000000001);
#1113=CARTESIAN_POINT('',(56.05,315.270539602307,0.));
#1114=VERTEX_POINT('',#1113);
#1115=EDGE_CURVE('E39',#1114,#1114,#1112,.T.);
#1116=ORIENTED_EDGE('',*,*,#1115,.T.);
#1117=EDGE_LOOP('',(#1116));
#1118=FACE_BOUND('',#1117,.T.);
#1119=CARTESIAN_POINT('',(42.4499999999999,87.3,0.));
#1120=DIRECTION('',(0.,0.,1.));
#1121=DIRECTION('',(1.,0.,0.));
#1122=AXIS2_PLACEMENT_3D('',#1119,#1120,#1121);
#1123=CIRCLE('',#1122,3.);
#1124=CARTESIAN_POINT('',(42.4499999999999,84.3,0.));
#1125=VERTEX_POINT('',#1124);
#1126=CARTESIAN_POINT('',(42.4499999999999,90.3,0.));
#1127=VERTEX_POINT('',#1126);
#1128=EDGE_CURVE('E1646',#1125,#1127,#1123,.F.);
#1129=ORIENTED_EDGE('',*,*,#1128,.F.);
#1130=DIRECTION('',(0.,-1.,0.));
#1131=VECTOR('',#1130,1.);
#1132=CARTESIAN_POINT('',(42.4499999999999,86.35,0.));
#1133=LINE('',#1132,#1131);
#1134=CARTESIAN_POINT('',(42.4499999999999,81.2,0.));
#1135=VERTEX_POINT('',#1134);
#1136=EDGE_CURVE('E1628',#1125,#1135,#1133,.T.);
#1137=ORIENTED_EDGE('',*,*,#1136,.T.);
#1138=CARTESIAN_POINT('',(42.4499999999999,78.2,0.));
#1139=DIRECTION('',(0.,0.,1.));
#1140=DIRECTION('',(1.,0.,0.));
#1141=AXIS2_PLACEMENT_3D('',#1138,#1139,#1140);
#1142=CIRCLE('',#1141,3.);
#1143=CARTESIAN_POINT('',(42.4499999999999,75.2,0.));
#1144=VERTEX_POINT('',#1143);
#1145=EDGE_CURVE('E1631',#1135,#1144,#1142,.T.);
#1146=ORIENTED_EDGE('',*,*,#1145,.T.);
#1147=DIRECTION('',(1.,0.,0.));
#1148=VECTOR('',#1147,1.);
#1149=CARTESIAN_POINT('',(15.,75.2,0.));
#1150=LINE('',#1149,#1148);
#1151=CARTESIAN_POINT('',(57.5499999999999,75.2,0.));
#1152=VERTEX_POINT('',#1151);
#1153=EDGE_CURVE('E1634',#1144,#1152,#1150,.T.);
#1154=ORIENTED_EDGE('',*,*,#1153,.T.);
#1155=CARTESIAN_POINT('',(57.5499999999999,78.2,0.));
#1156=DIRECTION('',(0.,0.,1.));
#1157=DIRECTION('',(1.,0.,0.));
#1158=AXIS2_PLACEMENT_3D('',#1155,#1156,#1157);
#1159=CIRCLE('',#1158,3.);
#1160=CARTESIAN_POINT('',(57.5499999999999,81.2,0.));
#1161=VERTEX_POINT('',#1160);
#1162=EDGE_CURVE('E1637',#1161,#1152,#1159,.F.);
#1163=ORIENTED_EDGE('',*,*,#1162,.F.);
#1164=DIRECTION('',(0.,1.,0.));
#1165=VECTOR('',#1164,1.);
#1166=CARTESIAN_POINT('',(57.5499999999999,86.3499999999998,0.));
#1167=LINE('',#1166,#1165);
#1168=CARTESIAN_POINT('',(57.5499999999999,84.3,0.));
#1169=VERTEX_POINT('',#1168);
#1170=EDGE_CURVE('E1639',#1161,#1169,#1167,.T.);
#1171=ORIENTED_EDGE('',*,*,#1170,.T.);
#1172=CARTESIAN_POINT('',(57.5499999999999,87.3,0.));
#1173=DIRECTION('',(0.,0.,1.));
#1174=DIRECTION('',(1.,0.,0.));
#1175=AXIS2_PLACEMENT_3D('',#1172,#1173,#1174);
#1176=CIRCLE('',#1175,3.);
#1177=CARTESIAN_POINT('',(57.5499999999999,90.3,0.));
#1178=VERTEX_POINT('',#1177);
#1179=EDGE_CURVE('E1642',#1178,#1169,#1176,.F.);
#1180=ORIENTED_EDGE('',*,*,#1179,.F.);
#1181=DIRECTION('',(1.,0.,0.));
#1182=VECTOR('',#1181,1.);
#1183=CARTESIAN_POINT('',(15.,90.3,0.));
#1184=LINE('',#1183,#1182);
#1185=EDGE_CURVE('E1644',#1127,#1178,#1184,.T.);
#1186=ORIENTED_EDGE('',*,*,#1185,.F.);
#1187=EDGE_LOOP('',(#1129,#1137,#1146,#1154,#1163,#1171,#1180,#1186));
#1188=FACE_BOUND('',#1187,.T.);
#1189=CARTESIAN_POINT('',(42.4499999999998,232.5,0.));
#1190=DIRECTION('',(0.,0.,1.));
#1191=DIRECTION('',(1.,0.,0.));
#1192=AXIS2_PLACEMENT_3D('',#1189,#1190,#1191);
#1193=CIRCLE('',#1192,3.);
#1194=CARTESIAN_POINT('',(42.4499999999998,229.5,0.));
#1195=VERTEX_POINT('',#1194);
#1196=CARTESIAN_POINT('',(42.4499999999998,235.5,0.));
#1197=VERTEX_POINT('',#1196);
#1198=EDGE_CURVE('E1606',#1195,#1197,#1193,.F.);
#1199=ORIENTED_EDGE('',*,*,#1198,.F.);
#1200=DIRECTION('',(0.,-1.,0.));
#1201=VECTOR('',#1200,1.);
#1202=CARTESIAN_POINT('',(42.4500000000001,86.3500000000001,0.));
#1203=LINE('',#1202,#1201);
#1204=CARTESIAN_POINT('',(42.4499999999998,226.4,0.));
#1205=VERTEX_POINT('',#1204);
#1206=EDGE_CURVE('E1588',#1195,#1205,#1203,.T.);
#1207=ORIENTED_EDGE('',*,*,#1206,.T.);
#1208=CARTESIAN_POINT('',(42.4499999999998,223.4,0.));
#1209=DIRECTION('',(0.,0.,1.));
#1210=DIRECTION('',(1.,0.,0.));
#1211=AXIS2_PLACEMENT_3D('',#1208,#1209,#1210);
#1212=CIRCLE('',#1211,3.);
#1213=CARTESIAN_POINT('',(42.4499999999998,220.4,0.));
#1214=VERTEX_POINT('',#1213);
#1215=EDGE_CURVE('E1591',#1205,#1214,#1212,.T.);
#1216=ORIENTED_EDGE('',*,*,#1215,.T.);
#1217=DIRECTION('',(1.,0.,0.));
#1218=VECTOR('',#1217,1.);
#1219=CARTESIAN_POINT('',(15.,220.4,0.));
#1220=LINE('',#1219,#1218);
#1221=CARTESIAN_POINT('',(57.5499999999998,220.4,0.));
#1222=VERTEX_POINT('',#1221);
#1223=EDGE_CURVE('E1594',#1214,#1222,#1220,.T.);
#1224=ORIENTED_EDGE('',*,*,#1223,.T.);
#1225=CARTESIAN_POINT('',(57.5499999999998,223.4,0.));
#1226=DIRECTION('',(0.,0.,1.));
#1227=DIRECTION('',(1.,0.,0.));
#1228=AXIS2_PLACEMENT_3D('',#1225,#1226,#1227);
#1229=CIRCLE('',#1228,3.00000000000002);
#1230=CARTESIAN_POINT('',(57.5499999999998,226.4,0.));
#1231=VERTEX_POINT('',#1230);
#1232=EDGE_CURVE('E1597',#1231,#1222,#1229,.F.);
#1233=ORIENTED_EDGE('',*,*,#1232,.F.);
#1234=DIRECTION('',(0.,1.,0.));
#1235=VECTOR('',#1234,1.);
#1236=CARTESIAN_POINT('',(57.5499999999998,86.35,0.));
#1237=LINE('',#1236,#1235);
#1238=CARTESIAN_POINT('',(57.5499999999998,229.5,0.));
#1239=VERTEX_POINT('',#1238);
#1240=EDGE_CURVE('E1599',#1231,#1239,#1237,.T.);
#1241=ORIENTED_EDGE('',*,*,#1240,.T.);
#1242=CARTESIAN_POINT('',(57.5499999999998,232.5,0.));
#1243=DIRECTION('',(0.,0.,1.));
#1244=DIRECTION('',(1.,0.,0.));
#1245=AXIS2_PLACEMENT_3D('',#1242,#1243,#1244);
#1246=CIRCLE('',#1245,2.99999999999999);
#1247=CARTESIAN_POINT('',(57.5499999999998,235.5,0.));
#1248=VERTEX_POINT('',#1247);
#1249=EDGE_CURVE('E1602',#1248,#1239,#1246,.F.);
#1250=ORIENTED_EDGE('',*,*,#1249,.F.);
#1251=DIRECTION('',(1.,0.,0.));
#1252=VECTOR('',#1251,1.);
#1253=CARTESIAN_POINT('',(15.,235.5,0.));
#1254=LINE('',#1253,#1252);
#1255=EDGE_CURVE('E1604',#1197,#1248,#1254,.T.);
#1256=ORIENTED_EDGE('',*,*,#1255,.F.);
#1257=EDGE_LOOP('',(#1199,#1207,#1216,#1224,#1233,#1241,#1250,#1256));
#1258=FACE_BOUND('',#1257,.T.);
#1259=CARTESIAN_POINT('',(42.45,27.1,0.));
#1260=DIRECTION('',(0.,0.,1.));
#1261=DIRECTION('',(1.,0.,0.));
#1262=AXIS2_PLACEMENT_3D('',#1259,#1260,#1261);
#1263=CIRCLE('',#1262,3.);
#1264=CARTESIAN_POINT('',(42.45,24.1,0.));
#1265=VERTEX_POINT('',#1264);
#1266=CARTESIAN_POINT('',(42.45,30.1,0.));
#1267=VERTEX_POINT('',#1266);
#1268=EDGE_CURVE('E1566',#1265,#1267,#1263,.F.);
#1269=ORIENTED_EDGE('',*,*,#1268,.F.);
#1270=DIRECTION('',(0.,-1.,0.));
#1271=VECTOR('',#1270,1.);
#1272=CARTESIAN_POINT('',(42.45,86.35,0.));
#1273=LINE('',#1272,#1271);
#1274=CARTESIAN_POINT('',(42.45,21.,0.));
#1275=VERTEX_POINT('',#1274);
#1276=EDGE_CURVE('E1548',#1265,#1275,#1273,.T.);
#1277=ORIENTED_EDGE('',*,*,#1276,.T.);
#1278=CARTESIAN_POINT('',(42.45,18.,0.));
#1279=DIRECTION('',(0.,0.,1.));
#1280=DIRECTION('',(1.,0.,0.));
#1281=AXIS2_PLACEMENT_3D('',#1278,#1279,#1280);
#1282=CIRCLE('',#1281,3.);
#1283=CARTESIAN_POINT('',(42.45,15.,0.));
#1284=VERTEX_POINT('',#1283);
#1285=EDGE_CURVE('E1551',#1275,#1284,#1282,.T.);
#1286=ORIENTED_EDGE('',*,*,#1285,.T.);
#1287=DIRECTION('',(1.,0.,0.));
#1288=VECTOR('',#1287,1.);
#1289=CARTESIAN_POINT('',(15.,15.,0.));
#1290=LINE('',#1289,#1288);
#1291=CARTESIAN_POINT('',(57.55,15.,0.));
#1292=VERTEX_POINT('',#1291);
#1293=EDGE_CURVE('E1554',#1284,#1292,#1290,.T.);
#1294=ORIENTED_EDGE('',*,*,#1293,.T.);
#1295=CARTESIAN_POINT('',(57.55,18.,0.));
#1296=DIRECTION('',(0.,0.,1.));
#1297=DIRECTION('',(1.,0.,0.));
#1298=AXIS2_PLACEMENT_3D('',#1295,#1296,#1297);
#1299=CIRCLE('',#1298,3.);
#1300=CARTESIAN_POINT('',(57.55,21.,0.));
#1301=VERTEX_POINT('',#1300);
#1302=EDGE_CURVE('E1557',#1301,#1292,#1299,.F.);
#1303=ORIENTED_EDGE('',*,*,#1302,.F.);
#1304=DIRECTION('',(0.,1.,0.));
#1305=VECTOR('',#1304,1.);
#1306=CARTESIAN_POINT('',(57.5499999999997,86.3500000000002,0.));
#1307=LINE('',#1306,#1305);
#1308=CARTESIAN_POINT('',(57.55,24.1,0.));
#1309=VERTEX_POINT('',#1308);
#1310=EDGE_CURVE('E1559',#1301,#1309,#1307,.T.);
#1311=ORIENTED_EDGE('',*,*,#1310,.T.);
#1312=CARTESIAN_POINT('',(57.55,27.1,0.));
#1313=DIRECTION('',(0.,0.,1.));
#1314=DIRECTION('',(1.,0.,0.));
#1315=AXIS2_PLACEMENT_3D('',#1312,#1313,#1314);
#1316=CIRCLE('',#1315,3.);
#1317=CARTESIAN_POINT('',(57.55,30.1,0.));
#1318=VERTEX_POINT('',#1317);
#1319=EDGE_CURVE('E1562',#1318,#1309,#1316,.F.);
#1320=ORIENTED_EDGE('',*,*,#1319,.F.);
#1321=DIRECTION('',(1.,0.,0.));
#1322=VECTOR('',#1321,1.);
#1323=CARTESIAN_POINT('',(15.,30.1,0.));
#1324=LINE('',#1323,#1322);
#1325=EDGE_CURVE('E1564',#1267,#1318,#1324,.T.);
#1326=ORIENTED_EDGE('',*,*,#1325,.F.);
#1327=EDGE_LOOP('',(#1269,#1277,#1286,#1294,#1303,#1311,#1320,#1326));
#1328=FACE_BOUND('',#1327,.T.);
#1329=CARTESIAN_POINT('',(15.,86.35,0.));
#1330=DIRECTION('',(0.,0.,-1.));
#1331=DIRECTION('',(1.,0.,0.));
#1332=AXIS2_PLACEMENT_3D('',#1329,#1330,#1331);
#1333=CIRCLE('',#1332,3.75);
#1334=CARTESIAN_POINT('',(15.,90.1,0.));
#1335=VERTEX_POINT('',#1334);
#1336=CARTESIAN_POINT('',(15.,82.6,0.));
#1337=VERTEX_POINT('',#1336);
#1338=EDGE_CURVE('E1007',#1335,#1337,#1333,.T.);
#1339=ORIENTED_EDGE('',*,*,#1338,.F.);
#1340=DIRECTION('',(1.,0.,0.));
#1341=VECTOR('',#1340,1.);
#1342=CARTESIAN_POINT('',(0.,90.1,0.));
#1343=LINE('',#1342,#1341);
#1344=CARTESIAN_POINT('',(0.,90.1,0.));
#1345=VERTEX_POINT('',#1344);
#1346=EDGE_CURVE('E1026',#1345,#1335,#1343,.T.);
#1347=ORIENTED_EDGE('',*,*,#1346,.F.);
#1348=DIRECTION('',(0.,-1.,0.));
#1349=VECTOR('',#1348,1.);
#1350=CARTESIAN_POINT('',(0.,289.970539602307,0.));
#1351=LINE('',#1350,#1349);
#1352=CARTESIAN_POINT('',(0.,289.970539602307,0.));
#1353=VERTEX_POINT('',#1352);
#1354=EDGE_CURVE('E1321',#1353,#1345,#1351,.T.);
#1355=ORIENTED_EDGE('',*,*,#1354,.F.);
#1356=DIRECTION('',(-1.,0.,0.));
#1357=VECTOR('',#1356,1.);
#1358=CARTESIAN_POINT('',(15.,289.970539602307,0.));
#1359=LINE('',#1358,#1357);
#1360=CARTESIAN_POINT('',(15.,289.970539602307,0.));
#1361=VERTEX_POINT('',#1360);
#1362=EDGE_CURVE('E1319',#1361,#1353,#1359,.T.);
#1363=ORIENTED_EDGE('',*,*,#1362,.F.);
#1364=CARTESIAN_POINT('',(15.,292.970539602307,0.));
#1365=DIRECTION('',(0.,0.,-1.));
#1366=DIRECTION('',(-1.,0.,0.));
#1367=AXIS2_PLACEMENT_3D('',#1364,#1365,#1366);
#1368=CIRCLE('',#1367,3.);
#1369=CARTESIAN_POINT('',(15.,295.970539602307,0.));
#1370=VERTEX_POINT('',#1369);
#1371=EDGE_CURVE('E1317',#1370,#1361,#1368,.T.);
#1372=ORIENTED_EDGE('',*,*,#1371,.F.);
#1373=DIRECTION('',(0.,-1.,0.));
#1374=VECTOR('',#1373,1.);
#1375=CARTESIAN_POINT('',(15.,295.970539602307,0.));
#1376=LINE('',#1375,#1374);
#1377=CARTESIAN_POINT('',(15.,299.070539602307,0.));
#1378=VERTEX_POINT('',#1377);
#1379=EDGE_CURVE('E1315',#1378,#1370,#1376,.T.);
#1380=ORIENTED_EDGE('',*,*,#1379,.F.);
#1381=CARTESIAN_POINT('',(15.,302.070539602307,0.));
#1382=DIRECTION('',(0.,0.,-1.));
#1383=DIRECTION('',(-1.,0.,0.));
#1384=AXIS2_PLACEMENT_3D('',#1381,#1382,#1383);
#1385=CIRCLE('',#1384,3.);
#1386=CARTESIAN_POINT('',(15.,305.070539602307,0.));
#1387=VERTEX_POINT('',#1386);
#1388=EDGE_CURVE('E1313',#1387,#1378,#1385,.T.);
#1389=ORIENTED_EDGE('',*,*,#1388,.F.);
#1390=DIRECTION('',(1.,0.,0.));
#1391=VECTOR('',#1390,1.);
#1392=CARTESIAN_POINT('',(0.,305.070539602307,0.));
#1393=LINE('',#1392,#1391);
#1394=CARTESIAN_POINT('',(0.,305.070539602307,0.));
#1395=VERTEX_POINT('',#1394);
#1396=EDGE_CURVE('E1311',#1395,#1387,#1393,.T.);
#1397=ORIENTED_EDGE('',*,*,#1396,.F.);
#1398=DIRECTION('',(0.,-1.,0.));
#1399=VECTOR('',#1398,1.);
#1400=CARTESIAN_POINT('',(0.,305.070539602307,0.));
#1401=LINE('',#1400,#1399);
#1402=CARTESIAN_POINT('',(0.,320.070539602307,0.));
#1403=VERTEX_POINT('',#1402);
#1404=EDGE_CURVE('E1309',#1403,#1395,#1401,.T.);
#1405=ORIENTED_EDGE('',*,*,#1404,.F.);
#1406=DIRECTION('',(-1.,0.,0.));
#1407=VECTOR('',#1406,1.);
#1408=CARTESIAN_POINT('',(15.,320.070539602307,0.));
#1409=LINE('',#1408,#1407);
#1410=CARTESIAN_POINT('',(15.,320.070539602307,0.));
#1411=VERTEX_POINT('',#1410);
#1412=EDGE_CURVE('E1307',#1411,#1403,#1409,.T.);
#1413=ORIENTED_EDGE('',*,*,#1412,.F.);
#1414=CARTESIAN_POINT('',(15.,323.070539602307,0.));
#1415=DIRECTION('',(0.,0.,-1.));
#1416=DIRECTION('',(-1.,0.,0.));
#1417=AXIS2_PLACEMENT_3D('',#1414,#1415,#1416);
#1418=CIRCLE('',#1417,3.);
#1419=CARTESIAN_POINT('',(15.,326.070539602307,0.));
#1420=VERTEX_POINT('',#1419);
#1421=EDGE_CURVE('E1305',#1420,#1411,#1418,.T.);
#1422=ORIENTED_EDGE('',*,*,#1421,.F.);
#1423=DIRECTION('',(0.,-1.,0.));
#1424=VECTOR('',#1423,1.);
#1425=CARTESIAN_POINT('',(15.,326.070539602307,0.));
#1426=LINE('',#1425,#1424);
#1427=CARTESIAN_POINT('',(15.,329.170539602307,0.));
#1428=VERTEX_POINT('',#1427);
#1429=EDGE_CURVE('E1303',#1428,#1420,#1426,.T.);
#1430=ORIENTED_EDGE('',*,*,#1429,.F.);
#1431=CARTESIAN_POINT('',(15.,332.170539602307,0.));
#1432=DIRECTION('',(0.,0.,-1.));
#1433=DIRECTION('',(-1.,0.,0.));
#1434=AXIS2_PLACEMENT_3D('',#1431,#1432,#1433);
#1435=CIRCLE('',#1434,3.);
#1436=CARTESIAN_POINT('',(15.,335.170539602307,0.));
#1437=VERTEX_POINT('',#1436);
#1438=EDGE_CURVE('E1301',#1437,#1428,#1435,.T.);
#1439=ORIENTED_EDGE('',*,*,#1438,.F.);
#1440=DIRECTION('',(1.,0.,0.));
#1441=VECTOR('',#1440,1.);
#1442=CARTESIAN_POINT('',(0.,335.170539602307,0.));
#1443=LINE('',#1442,#1441);
#1444=CARTESIAN_POINT('',(0.,335.170539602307,0.));
#1445=VERTEX_POINT('',#1444);
#1446=EDGE_CURVE('E1299',#1445,#1437,#1443,.T.);
#1447=ORIENTED_EDGE('',*,*,#1446,.F.);
#1448=DIRECTION('',(0.,-1.,0.));
#1449=VECTOR('',#1448,1.);
#1450=CARTESIAN_POINT('',(0.,335.170539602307,0.));
#1451=LINE('',#1450,#1449);
#1452=CARTESIAN_POINT('',(0.,350.170539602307,0.));
#1453=VERTEX_POINT('',#1452);
#1454=EDGE_CURVE('E1297',#1453,#1445,#1451,.T.);
#1455=ORIENTED_EDGE('',*,*,#1454,.F.);
#1456=DIRECTION('',(-1.,0.,0.));
#1457=VECTOR('',#1456,1.);
#1458=CARTESIAN_POINT('',(15.,350.170539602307,0.));
#1459=LINE('',#1458,#1457);
#1460=CARTESIAN_POINT('',(15.,350.170539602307,0.));
#1461=VERTEX_POINT('',#1460);
#1462=EDGE_CURVE('E1295',#1461,#1453,#1459,.T.);
#1463=ORIENTED_EDGE('',*,*,#1462,.F.);
#1464=CARTESIAN_POINT('',(15.,353.170539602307,0.));
#1465=DIRECTION('',(0.,0.,-1.));
#1466=DIRECTION('',(-1.,0.,0.));
#1467=AXIS2_PLACEMENT_3D('',#1464,#1465,#1466);
#1468=CIRCLE('',#1467,3.);
#1469=CARTESIAN_POINT('',(15.,356.170539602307,0.));
#1470=VERTEX_POINT('',#1469);
#1471=EDGE_CURVE('E1293',#1470,#1461,#1468,.T.);
#1472=ORIENTED_EDGE('',*,*,#1471,.F.);
#1473=DIRECTION('',(0.,-1.,0.));
#1474=VECTOR('',#1473,1.);
#1475=CARTESIAN_POINT('',(15.,356.170539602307,0.));
#1476=LINE('',#1475,#1474);
#1477=CARTESIAN_POINT('',(15.,365.270539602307,0.));
#1478=VERTEX_POINT('',#1477);
#1479=EDGE_CURVE('E1291',#1478,#1470,#1476,.T.);
#1480=ORIENTED_EDGE('',*,*,#1479,.F.);
#1481=CARTESIAN_POINT('',(12.,365.270539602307,0.));
#1482=DIRECTION('',(0.,0.,-1.));
#1483=DIRECTION('',(1.,0.,0.));
#1484=AXIS2_PLACEMENT_3D('',#1481,#1482,#1483);
#1485=CIRCLE('',#1484,3.);
#1486=CARTESIAN_POINT('',(9.,365.270539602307,0.));
#1487=VERTEX_POINT('',#1486);
#1488=EDGE_CURVE('E1289',#1487,#1478,#1485,.T.);
#1489=ORIENTED_EDGE('',*,*,#1488,.F.);
#1490=DIRECTION('',(1.,0.,0.));
#1491=VECTOR('',#1490,1.);
#1492=CARTESIAN_POINT('',(0.,365.270539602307,0.));
#1493=LINE('',#1492,#1491);
#1494=CARTESIAN_POINT('',(0.,365.270539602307,0.));
#1495=VERTEX_POINT('',#1494);
#1496=EDGE_CURVE('E1287',#1495,#1487,#1493,.T.);
#1497=ORIENTED_EDGE('',*,*,#1496,.F.);
#1498=DIRECTION('',(0.,-1.,0.));
#1499=VECTOR('',#1498,1.);
#1500=CARTESIAN_POINT('',(0.,365.270539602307,0.));
#1501=LINE('',#1500,#1499);
#1502=CARTESIAN_POINT('',(0.,380.270539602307,0.));
#1503=VERTEX_POINT('',#1502);
#1504=EDGE_CURVE('E1285',#1503,#1495,#1501,.T.);
#1505=ORIENTED_EDGE('',*,*,#1504,.F.);
#1506=DIRECTION('',(-1.,0.,0.));
#1507=VECTOR('',#1506,1.);
#1508=CARTESIAN_POINT('',(0.,380.270539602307,0.));
#1509=LINE('',#1508,#1507);
#1510=CARTESIAN_POINT('',(25.,380.270539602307,0.));
#1511=VERTEX_POINT('',#1510);
#1512=EDGE_CURVE('E1283',#1511,#1503,#1509,.T.);
#1513=ORIENTED_EDGE('',*,*,#1512,.F.);
#1514=DIRECTION('',(0.,1.,0.));
#1515=VECTOR('',#1514,1.);
#1516=CARTESIAN_POINT('',(25.,365.270539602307,0.));
#1517=LINE('',#1516,#1515);
#1518=CARTESIAN_POINT('',(25.,365.270539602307,0.));
#1519=VERTEX_POINT('',#1518);
#1520=EDGE_CURVE('E1281',#1519,#1511,#1517,.T.);
#1521=ORIENTED_EDGE('',*,*,#1520,.F.);
#1522=CARTESIAN_POINT('',(28.0000000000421,365.270539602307,0.));
#1523=DIRECTION('',(0.,0.,-1.));
#1524=DIRECTION('',(-1.,0.,0.));
#1525=AXIS2_PLACEMENT_3D('',#1522,#1523,#1524);
#1526=CIRCLE('',#1525,3.00000000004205);
#1527=CARTESIAN_POINT('',(30.9999999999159,365.270507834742,0.));
#1528=VERTEX_POINT('',#1527);
#1529=EDGE_CURVE('E1279',#1528,#1519,#1526,.T.);
#1530=ORIENTED_EDGE('',*,*,#1529,.F.);
#1531=DIRECTION('',(-1.,0.,0.));
#1532=VECTOR('',#1531,1.);
#1533=CARTESIAN_POINT('',(30.9999999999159,365.270507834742,0.));
#1534=LINE('',#1533,#1532);
#1535=CARTESIAN_POINT('',(34.1000000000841,365.270507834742,0.));
#1536=VERTEX_POINT('',#1535);
#1537=EDGE_CURVE('E1277',#1536,#1528,#1534,.T.);
#1538=ORIENTED_EDGE('',*,*,#1537,.F.);
#1539=CARTESIAN_POINT('',(37.0999999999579,365.270539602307,0.));
#1540=DIRECTION('',(0.,0.,-1.));
#1541=DIRECTION('',(-1.,0.,0.));
#1542=AXIS2_PLACEMENT_3D('',#1539,#1540,#1541);
#1543=CIRCLE('',#1542,3.00000000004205);
#1544=CARTESIAN_POINT('',(40.1,365.270539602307,0.));
#1545=VERTEX_POINT('',#1544);
#1546=EDGE_CURVE('E1275',#1545,#1536,#1543,.T.);
#1547=ORIENTED_EDGE('',*,*,#1546,.F.);
#1548=DIRECTION('',(0.,-1.,0.));
#1549=VECTOR('',#1548,1.);
#1550=CARTESIAN_POINT('',(40.1,365.270539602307,0.));
#1551=LINE('',#1550,#1549);
#1552=CARTESIAN_POINT('',(40.1,380.270539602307,0.));
#1553=VERTEX_POINT('',#1552);
#1554=EDGE_CURVE('E1273',#1553,#1545,#1551,.T.);
#1555=ORIENTED_EDGE('',*,*,#1554,.F.);
#1556=DIRECTION('',(-1.,0.,0.));
#1557=VECTOR('',#1556,1.);
#1558=CARTESIAN_POINT('',(40.1,380.270539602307,0.));
#1559=LINE('',#1558,#1557);
#1560=CARTESIAN_POINT('',(55.1,380.270539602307,0.));
#1561=VERTEX_POINT('',#1560);
#1562=EDGE_CURVE('E1271',#1561,#1553,#1559,.T.);
#1563=ORIENTED_EDGE('',*,*,#1562,.F.);
#1564=DIRECTION('',(0.,1.,0.));
#1565=VECTOR('',#1564,1.);
#1566=CARTESIAN_POINT('',(55.1,380.270539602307,0.));
#1567=LINE('',#1566,#1565);
#1568=CARTESIAN_POINT('',(55.1,365.270539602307,0.));
#1569=VERTEX_POINT('',#1568);
#1570=EDGE_CURVE('E1269',#1569,#1561,#1567,.T.);
#1571=ORIENTED_EDGE('',*,*,#1570,.F.);
#1572=CARTESIAN_POINT('',(58.1000000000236,365.270539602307,0.));
#1573=DIRECTION('',(0.,0.,-1.));
#1574=DIRECTION('',(-1.,0.,0.));
#1575=AXIS2_PLACEMENT_3D('',#1572,#1573,#1574);
#1576=CIRCLE('',#1575,3.00000000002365);
#1577=CARTESIAN_POINT('',(61.0999999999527,365.270515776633,0.));
#1578=VERTEX_POINT('',#1577);
#1579=EDGE_CURVE('E1267',#1578,#1569,#1576,.T.);
#1580=ORIENTED_EDGE('',*,*,#1579,.F.);
#1581=DIRECTION('',(-1.,0.,0.));
#1582=VECTOR('',#1581,1.);
#1583=CARTESIAN_POINT('',(61.0999999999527,365.270515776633,0.));
#1584=LINE('',#1583,#1582);
#1585=CARTESIAN_POINT('',(64.2000000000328,365.270515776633,0.));
#1586=VERTEX_POINT('',#1585);
#1587=EDGE_CURVE('E1265',#1586,#1578,#1584,.T.);
#1588=ORIENTED_EDGE('',*,*,#1587,.F.);
#1589=CARTESIAN_POINT('',(67.1999999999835,365.270535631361,0.));
#1590=DIRECTION('',(0.,0.,-1.));
#1591=DIRECTION('',(-1.,0.,0.));
#1592=AXIS2_PLACEMENT_3D('',#1589,#1590,#1591);
#1593=CIRCLE('',#1592,3.00000000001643);
#1594=CARTESIAN_POINT('',(70.1999999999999,365.270535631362,0.));
#1595=VERTEX_POINT('',#1594);
#1596=EDGE_CURVE('E1263',#1595,#1586,#1593,.T.);
#1597=ORIENTED_EDGE('',*,*,#1596,.F.);
#1598=DIRECTION('',(0.,-1.,0.));
#1599=VECTOR('',#1598,1.);
#1600=CARTESIAN_POINT('',(70.1999999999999,365.270535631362,0.));
#1601=LINE('',#1600,#1599);
#1602=CARTESIAN_POINT('',(70.1999999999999,380.270535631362,0.));
#1603=VERTEX_POINT('',#1602);
#1604=EDGE_CURVE('E1261',#1603,#1595,#1601,.T.);
#1605=ORIENTED_EDGE('',*,*,#1604,.F.);
#1606=DIRECTION('',(-1.,0.,0.));
#1607=VECTOR('',#1606,1.);
#1608=CARTESIAN_POINT('',(70.1999999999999,380.270535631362,0.));
#1609=LINE('',#1608,#1607);
#1610=CARTESIAN_POINT('',(85.1999999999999,380.270535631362,0.));
#1611=VERTEX_POINT('',#1610);
#1612=EDGE_CURVE('E1259',#1611,#1603,#1609,.T.);
#1613=ORIENTED_EDGE('',*,*,#1612,.F.);
#1614=DIRECTION('',(0.,1.,0.));
#1615=VECTOR('',#1614,1.);
#1616=CARTESIAN_POINT('',(85.1999999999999,380.270535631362,0.));
#1617=LINE('',#1616,#1615);
#1618=CARTESIAN_POINT('',(85.2,365.270535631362,0.));
#1619=VERTEX_POINT('',#1618);
#1620=EDGE_CURVE('E1257',#1619,#1611,#1617,.T.);
#1621=ORIENTED_EDGE('',*,*,#1620,.F.);
#1622=CARTESIAN_POINT('',(88.1999999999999,365.335267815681,0.));
#1623=DIRECTION('',(0.,0.,-1.));
#1624=DIRECTION('',(-1.,0.,0.));
#1625=AXIS2_PLACEMENT_3D('',#1622,#1623,#1624);
#1626=CIRCLE('',#1625,3.00069829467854);
#1627=CARTESIAN_POINT('',(91.1999999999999,365.4,0.));
#1628=VERTEX_POINT('',#1627);
#1629=EDGE_CURVE('E1255',#1628,#1619,#1626,.T.);
#1630=ORIENTED_EDGE('',*,*,#1629,.F.);
#1631=DIRECTION('',(-1.,0.,0.));
#1632=VECTOR('',#1631,1.);
#1633=CARTESIAN_POINT('',(91.1999999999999,365.4,0.));
#1634=LINE('',#1633,#1632);
#1635=CARTESIAN_POINT('',(100.,365.4,0.));
#1636=VERTEX_POINT('',#1635);
#1637=EDGE_CURVE('E1253',#1636,#1628,#1634,.T.);
#1638=ORIENTED_EDGE('',*,*,#1637,.F.);
#1639=DIRECTION('',(0.,1.,0.));
#1640=VECTOR('',#1639,1.);
#1641=CARTESIAN_POINT('',(100.,90.1,0.));
#1642=LINE('',#1641,#1640);
#1643=CARTESIAN_POINT('',(100.,90.1,0.));
#1644=VERTEX_POINT('',#1643);
#1645=EDGE_CURVE('E1251',#1644,#1636,#1642,.T.);
#1646=ORIENTED_EDGE('',*,*,#1645,.F.);
#1647=DIRECTION('',(1.,0.,0.));
#1648=VECTOR('',#1647,1.);
#1649=CARTESIAN_POINT('',(85.,90.1,0.));
#1650=LINE('',#1649,#1648);
#1651=CARTESIAN_POINT('',(85.,90.1,0.));
#1652=VERTEX_POINT('',#1651);
#1653=EDGE_CURVE('E1249',#1652,#1644,#1650,.T.);
#1654=ORIENTED_EDGE('',*,*,#1653,.F.);
#1655=CARTESIAN_POINT('',(85.,86.35,0.));
#1656=DIRECTION('',(0.,0.,-1.));
#1657=DIRECTION('',(-1.,0.,0.));
#1658=AXIS2_PLACEMENT_3D('',#1655,#1656,#1657);
#1659=CIRCLE('',#1658,3.75);
#1660=CARTESIAN_POINT('',(85.,82.6,0.));
#1661=VERTEX_POINT('',#1660);
#1662=EDGE_CURVE('E1247',#1661,#1652,#1659,.T.);
#1663=ORIENTED_EDGE('',*,*,#1662,.F.);
#1664=DIRECTION('',(-1.,0.,0.));
#1665=VECTOR('',#1664,1.);
#1666=CARTESIAN_POINT('',(85.,82.6,0.));
#1667=LINE('',#1666,#1665);
#1668=CARTESIAN_POINT('',(100.,82.6,0.));
#1669=VERTEX_POINT('',#1668);
#1670=EDGE_CURVE('E1245',#1669,#1661,#1667,.T.);
#1671=ORIENTED_EDGE('',*,*,#1670,.F.);
#1672=DIRECTION('',(0.,1.,0.));
#1673=VECTOR('',#1672,1.);
#1674=CARTESIAN_POINT('',(100.,82.6,0.));
#1675=LINE('',#1674,#1673);
#1676=CARTESIAN_POINT('',(100.,67.6,0.));
#1677=VERTEX_POINT('',#1676);
#1678=EDGE_CURVE('E1243',#1677,#1669,#1675,.T.);
#1679=ORIENTED_EDGE('',*,*,#1678,.F.);
#1680=DIRECTION('',(1.,0.,0.));
#1681=VECTOR('',#1680,1.);
#1682=CARTESIAN_POINT('',(100.,67.6,0.));
#1683=LINE('',#1682,#1681);
#1684=CARTESIAN_POINT('',(85.,67.6,0.));
#1685=VERTEX_POINT('',#1684);
#1686=EDGE_CURVE('E1241',#1685,#1677,#1683,.T.);
#1687=ORIENTED_EDGE('',*,*,#1686,.F.);
#1688=CARTESIAN_POINT('',(85.,64.6,0.));
#1689=DIRECTION('',(0.,0.,-1.));
#1690=DIRECTION('',(-1.,0.,0.));
#1691=AXIS2_PLACEMENT_3D('',#1688,#1689,#1690);
#1692=CIRCLE('',#1691,3.);
#1693=CARTESIAN_POINT('',(85.,61.6,0.));
#1694=VERTEX_POINT('',#1693);
#1695=EDGE_CURVE('E1239',#1694,#1685,#1692,.T.);
#1696=ORIENTED_EDGE('',*,*,#1695,.F.);
#1697=DIRECTION('',(0.,1.,0.));
#1698=VECTOR('',#1697,1.);
#1699=CARTESIAN_POINT('',(85.,61.6,0.));
#1700=LINE('',#1699,#1698);
#1701=CARTESIAN_POINT('',(85.,58.5,0.));
#1702=VERTEX_POINT('',#1701);
#1703=EDGE_CURVE('E1237',#1702,#1694,#1700,.T.);
#1704=ORIENTED_EDGE('',*,*,#1703,.F.);
#1705=CARTESIAN_POINT('',(85.,55.5,0.));
#1706=DIRECTION('',(0.,0.,-1.));
#1707=DIRECTION('',(-1.,0.,0.));
#1708=AXIS2_PLACEMENT_3D('',#1705,#1706,#1707);
#1709=CIRCLE('',#1708,3.);
#1710=CARTESIAN_POINT('',(85.,52.5,0.));
#1711=VERTEX_POINT('',#1710);
#1712=EDGE_CURVE('E1235',#1711,#1702,#1709,.T.);
#1713=ORIENTED_EDGE('',*,*,#1712,.F.);
#1714=DIRECTION('',(-1.,0.,0.));
#1715=VECTOR('',#1714,1.);
#1716=CARTESIAN_POINT('',(85.,52.5,0.));
#1717=LINE('',#1716,#1715);
#1718=CARTESIAN_POINT('',(100.,52.5,0.));
#1719=VERTEX_POINT('',#1718);
#1720=EDGE_CURVE('E1233',#1719,#1711,#1717,.T.);
#1721=ORIENTED_EDGE('',*,*,#1720,.F.);
#1722=DIRECTION('',(0.,1.,0.));
#1723=VECTOR('',#1722,1.);
#1724=CARTESIAN_POINT('',(100.,52.5,0.));
#1725=LINE('',#1724,#1723);
#1726=CARTESIAN_POINT('',(100.,37.5,0.));
#1727=VERTEX_POINT('',#1726);
#1728=EDGE_CURVE('E1231',#1727,#1719,#1725,.T.);
#1729=ORIENTED_EDGE('',*,*,#1728,.F.);
#1730=DIRECTION('',(1.,0.,0.));
#1731=VECTOR('',#1730,1.);
#1732=CARTESIAN_POINT('',(100.,37.5,0.));
#1733=LINE('',#1732,#1731);
#1734=CARTESIAN_POINT('',(85.,37.5,0.));
#1735=VERTEX_POINT('',#1734);
#1736=EDGE_CURVE('E1229',#1735,#1727,#1733,.T.);
#1737=ORIENTED_EDGE('',*,*,#1736,.F.);
#1738=CARTESIAN_POINT('',(85.,34.5,0.));
#1739=DIRECTION('',(0.,0.,-1.));
#1740=DIRECTION('',(-1.,0.,0.));
#1741=AXIS2_PLACEMENT_3D('',#1738,#1739,#1740);
#1742=CIRCLE('',#1741,3.);
#1743=CARTESIAN_POINT('',(85.,31.5,0.));
#1744=VERTEX_POINT('',#1743);
#1745=EDGE_CURVE('E1227',#1744,#1735,#1742,.T.);
#1746=ORIENTED_EDGE('',*,*,#1745,.F.);
#1747=DIRECTION('',(0.,1.,0.));
#1748=VECTOR('',#1747,1.);
#1749=CARTESIAN_POINT('',(85.,31.5,0.));
#1750=LINE('',#1749,#1748);
#1751=CARTESIAN_POINT('',(85.0000000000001,28.4,0.));
#1752=VERTEX_POINT('',#1751);
#1753=EDGE_CURVE('E1225',#1752,#1744,#1750,.T.);
#1754=ORIENTED_EDGE('',*,*,#1753,.F.);
#1755=CARTESIAN_POINT('',(85.0000000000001,25.4,0.));
#1756=DIRECTION('',(0.,0.,-1.));
#1757=DIRECTION('',(-1.,0.,0.));
#1758=AXIS2_PLACEMENT_3D('',#1755,#1756,#1757);
#1759=CIRCLE('',#1758,3.);
#1760=CARTESIAN_POINT('',(85.,22.4,0.));
#1761=VERTEX_POINT('',#1760);
#1762=EDGE_CURVE('E1223',#1761,#1752,#1759,.T.);
#1763=ORIENTED_EDGE('',*,*,#1762,.F.);
#1764=DIRECTION('',(-1.,0.,0.));
#1765=VECTOR('',#1764,1.);
#1766=CARTESIAN_POINT('',(85.,22.4,0.));
#1767=LINE('',#1766,#1765);
#1768=CARTESIAN_POINT('',(100.,22.4,0.));
#1769=VERTEX_POINT('',#1768);
#1770=EDGE_CURVE('E1221',#1769,#1761,#1767,.T.);
#1771=ORIENTED_EDGE('',*,*,#1770,.F.);
#1772=DIRECTION('',(0.,1.,0.));
#1773=VECTOR('',#1772,1.);
#1774=CARTESIAN_POINT('',(100.,22.4,0.));
#1775=LINE('',#1774,#1773);
#1776=CARTESIAN_POINT('',(100.,7.4,0.));
#1777=VERTEX_POINT('',#1776);
#1778=EDGE_CURVE('E1219',#1777,#1769,#1775,.T.);
#1779=ORIENTED_EDGE('',*,*,#1778,.F.);
#1780=DIRECTION('',(1.,0.,0.));
#1781=VECTOR('',#1780,1.);
#1782=CARTESIAN_POINT('',(100.,7.4,0.));
#1783=LINE('',#1782,#1781);
#1784=CARTESIAN_POINT('',(85.,7.39999999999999,0.));
#1785=VERTEX_POINT('',#1784);
#1786=EDGE_CURVE('E1217',#1785,#1777,#1783,.T.);
#1787=ORIENTED_EDGE('',*,*,#1786,.F.);
#1788=CARTESIAN_POINT('',(85.,4.39999999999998,0.));
#1789=DIRECTION('',(0.,0.,-1.));
#1790=DIRECTION('',(1.,0.,0.));
#1791=AXIS2_PLACEMENT_3D('',#1788,#1789,#1790);
#1792=CIRCLE('',#1791,3.00000000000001);
#1793=CARTESIAN_POINT('',(85.,1.39999999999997,0.));
#1794=VERTEX_POINT('',#1793);
#1795=EDGE_CURVE('E1215',#1794,#1785,#1792,.T.);
#1796=ORIENTED_EDGE('',*,*,#1795,.F.);
#1797=DIRECTION('',(0.,1.,0.));
#1798=VECTOR('',#1797,1.);
#1799=CARTESIAN_POINT('',(85.,1.39999999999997,0.));
#1800=LINE('',#1799,#1798);
#1801=CARTESIAN_POINT('',(85.,0.,0.));
#1802=VERTEX_POINT('',#1801);
#1803=EDGE_CURVE('E1213',#1802,#1794,#1800,.T.);
#1804=ORIENTED_EDGE('',*,*,#1803,.F.);
#1805=DIRECTION('',(1.,0.,0.));
#1806=VECTOR('',#1805,1.);
#1807=CARTESIAN_POINT('',(85.,0.,0.));
#1808=LINE('',#1807,#1806);
#1809=CARTESIAN_POINT('',(15.,0.,0.));
#1810=VERTEX_POINT('',#1809);
#1811=EDGE_CURVE('E1211',#1810,#1802,#1808,.T.);
#1812=ORIENTED_EDGE('',*,*,#1811,.F.);
#1813=DIRECTION('',(0.,-1.,0.));
#1814=VECTOR('',#1813,1.);
#1815=CARTESIAN_POINT('',(15.,1.4,0.));
#1816=LINE('',#1815,#1814);
#1817=CARTESIAN_POINT('',(15.,1.4,0.));
#1818=VERTEX_POINT('',#1817);
#1819=EDGE_CURVE('E1209',#1818,#1810,#1816,.T.);
#1820=ORIENTED_EDGE('',*,*,#1819,.F.);
#1821=CARTESIAN_POINT('',(15.,4.4,0.));
#1822=DIRECTION('',(0.,0.,-1.));
#1823=DIRECTION('',(-1.,0.,0.));
#1824=AXIS2_PLACEMENT_3D('',#1821,#1822,#1823);
#1825=CIRCLE('',#1824,3.);
#1826=CARTESIAN_POINT('',(15.,7.4,0.));
#1827=VERTEX_POINT('',#1826);
#1828=EDGE_CURVE('E1207',#1827,#1818,#1825,.T.);
#1829=ORIENTED_EDGE('',*,*,#1828,.F.);
#1830=DIRECTION('',(1.,0.,0.));
#1831=VECTOR('',#1830,1.);
#1832=CARTESIAN_POINT('',(0.,7.4,0.));
#1833=LINE('',#1832,#1831);
#1834=CARTESIAN_POINT('',(0.,7.4,0.));
#1835=VERTEX_POINT('',#1834);
#1836=EDGE_CURVE('E1205',#1835,#1827,#1833,.T.);
#1837=ORIENTED_EDGE('',*,*,#1836,.F.);
#1838=DIRECTION('',(0.,-1.,0.));
#1839=VECTOR('',#1838,1.);
#1840=CARTESIAN_POINT('',(0.,22.4,0.));
#1841=LINE('',#1840,#1839);
#1842=CARTESIAN_POINT('',(0.,22.4,0.));
#1843=VERTEX_POINT('',#1842);
#1844=EDGE_CURVE('E1203',#1843,#1835,#1841,.T.);
#1845=ORIENTED_EDGE('',*,*,#1844,.F.);
#1846=DIRECTION('',(-1.,0.,0.));
#1847=VECTOR('',#1846,1.);
#1848=CARTESIAN_POINT('',(15.,22.4,0.));
#1849=LINE('',#1848,#1847);
#1850=CARTESIAN_POINT('',(15.,22.4,0.));
#1851=VERTEX_POINT('',#1850);
#1852=EDGE_CURVE('E1201',#1851,#1843,#1849,.T.);
#1853=ORIENTED_EDGE('',*,*,#1852,.F.);
#1854=CARTESIAN_POINT('',(15.,25.4,0.));
#1855=DIRECTION('',(0.,0.,-1.));
#1856=DIRECTION('',(-1.,0.,0.));
#1857=AXIS2_PLACEMENT_3D('',#1854,#1855,#1856);
#1858=CIRCLE('',#1857,3.);
#1859=CARTESIAN_POINT('',(15.,28.4,0.));
#1860=VERTEX_POINT('',#1859);
#1861=EDGE_CURVE('E1199',#1860,#1851,#1858,.T.);
#1862=ORIENTED_EDGE('',*,*,#1861,.F.);
#1863=DIRECTION('',(0.,-1.,0.));
#1864=VECTOR('',#1863,1.);
#1865=CARTESIAN_POINT('',(15.,31.5,0.));
#1866=LINE('',#1865,#1864);
#1867=CARTESIAN_POINT('',(15.,31.5,0.));
#1868=VERTEX_POINT('',#1867);
#1869=EDGE_CURVE('E1197',#1868,#1860,#1866,.T.);
#1870=ORIENTED_EDGE('',*,*,#1869,.F.);
#1871=CARTESIAN_POINT('',(15.,34.5,0.));
#1872=DIRECTION('',(0.,0.,-1.));
#1873=DIRECTION('',(-1.,0.,0.));
#1874=AXIS2_PLACEMENT_3D('',#1871,#1872,#1873);
#1875=CIRCLE('',#1874,3.);
#1876=CARTESIAN_POINT('',(15.,37.5,0.));
#1877=VERTEX_POINT('',#1876);
#1878=EDGE_CURVE('E1195',#1877,#1868,#1875,.T.);
#1879=ORIENTED_EDGE('',*,*,#1878,.F.);
#1880=DIRECTION('',(1.,0.,0.));
#1881=VECTOR('',#1880,1.);
#1882=CARTESIAN_POINT('',(0.,37.5,0.));
#1883=LINE('',#1882,#1881);
#1884=CARTESIAN_POINT('',(0.,37.5,0.));
#1885=VERTEX_POINT('',#1884);
#1886=EDGE_CURVE('E1193',#1885,#1877,#1883,.T.);
#1887=ORIENTED_EDGE('',*,*,#1886,.F.);
#1888=DIRECTION('',(0.,-1.,0.));
#1889=VECTOR('',#1888,1.);
#1890=CARTESIAN_POINT('',(0.,52.5,0.));
#1891=LINE('',#1890,#1889);
#1892=CARTESIAN_POINT('',(0.,52.5,0.));
#1893=VERTEX_POINT('',#1892);
#1894=EDGE_CURVE('E1191',#1893,#1885,#1891,.T.);
#1895=ORIENTED_EDGE('',*,*,#1894,.F.);
#1896=DIRECTION('',(-1.,0.,0.));
#1897=VECTOR('',#1896,1.);
#1898=CARTESIAN_POINT('',(15.,52.5,0.));
#1899=LINE('',#1898,#1897);
#1900=CARTESIAN_POINT('',(15.,52.5,0.));
#1901=VERTEX_POINT('',#1900);
#1902=EDGE_CURVE('E1189',#1901,#1893,#1899,.T.);
#1903=ORIENTED_EDGE('',*,*,#1902,.F.);
#1904=CARTESIAN_POINT('',(15.,55.5,0.));
#1905=DIRECTION('',(0.,0.,-1.));
#1906=DIRECTION('',(-1.,0.,0.));
#1907=AXIS2_PLACEMENT_3D('',#1904,#1905,#1906);
#1908=CIRCLE('',#1907,3.);
#1909=CARTESIAN_POINT('',(15.,58.5,0.));
#1910=VERTEX_POINT('',#1909);
#1911=EDGE_CURVE('E1187',#1910,#1901,#1908,.T.);
#1912=ORIENTED_EDGE('',*,*,#1911,.F.);
#1913=DIRECTION('',(0.,-1.,0.));
#1914=VECTOR('',#1913,1.);
#1915=CARTESIAN_POINT('',(15.,61.6,0.));
#1916=LINE('',#1915,#1914);
#1917=CARTESIAN_POINT('',(15.,61.6,0.));
#1918=VERTEX_POINT('',#1917);
#1919=EDGE_CURVE('E1185',#1918,#1910,#1916,.T.);
#1920=ORIENTED_EDGE('',*,*,#1919,.F.);
#1921=CARTESIAN_POINT('',(15.,64.6,0.));
#1922=DIRECTION('',(0.,0.,-1.));
#1923=DIRECTION('',(-1.,0.,0.));
#1924=AXIS2_PLACEMENT_3D('',#1921,#1922,#1923);
#1925=CIRCLE('',#1924,3.);
#1926=CARTESIAN_POINT('',(15.,67.6,0.));
#1927=VERTEX_POINT('',#1926);
#1928=EDGE_CURVE('E1183',#1927,#1918,#1925,.T.);
#1929=ORIENTED_EDGE('',*,*,#1928,.F.);
#1930=DIRECTION('',(1.,0.,0.));
#1931=VECTOR('',#1930,1.);
#1932=CARTESIAN_POINT('',(0.,67.6,0.));
#1933=LINE('',#1932,#1931);
#1934=CARTESIAN_POINT('',(0.,67.6,0.));
#1935=VERTEX_POINT('',#1934);
#1936=EDGE_CURVE('E1181',#1935,#1927,#1933,.T.);
#1937=ORIENTED_EDGE('',*,*,#1936,.F.);
#1938=DIRECTION('',(0.,-1.,0.));
#1939=VECTOR('',#1938,1.);
#1940=CARTESIAN_POINT('',(0.,82.6,0.));
#1941=LINE('',#1940,#1939);
#1942=CARTESIAN_POINT('',(0.,82.6,0.));
#1943=VERTEX_POINT('',#1942);
#1944=EDGE_CURVE('E1179',#1943,#1935,#1941,.T.);
#1945=ORIENTED_EDGE('',*,*,#1944,.F.);
#1946=DIRECTION('',(-1.,0.,0.));
#1947=VECTOR('',#1946,1.);
#1948=CARTESIAN_POINT('',(0.,82.6,0.));
#1949=LINE('',#1948,#1947);
#1950=EDGE_CURVE('E1177',#1337,#1943,#1949,.T.);
#1951=ORIENTED_EDGE('',*,*,#1950,.F.);
#1952=EDGE_LOOP('',(#1339,#1347,#1355,#1363,#1372,#1380,#1389,#1397,#1405,#1413,#1422,#1430,
#1439,#1447,#1455,#1463,#1472,#1480,#1489,#1497,#1505,#1513,#1521,#1530,#1538,#1547,#1555,#1563,
#1571,#1580,#1588,#1597,#1605,#1613,#1621,#1630,#1638,#1646,#1654,#1663,#1671,#1679,#1687,#1696,
#1704,#1713,#1721,#1729,#1737,#1746,#1754,#1763,#1771,#1779,#1787,#1796,#1804,#1812,#1820,#1829,
#1837,#1845,#1853,#1862,#1870,#1879,#1887,#1895,#1903,#1912,#1920,#1929,#1937,#1945,#1951));
#1953=FACE_BOUND('',#1952,.T.);
#1954=CARTESIAN_POINT('',(42.4499999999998,262.6,0.));
#1955=DIRECTION('',(0.,0.,1.));
#1956=DIRECTION('',(1.,0.,0.));
#1957=AXIS2_PLACEMENT_3D('',#1954,#1955,#1956);
#1958=CIRCLE('',#1957,3.);
#1959=CARTESIAN_POINT('',(42.4499999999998,259.6,0.));
#1960=VERTEX_POINT('',#1959);
#1961=CARTESIAN_POINT('',(42.4499999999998,265.6,0.));
#1962=VERTEX_POINT('',#1961);
#1963=EDGE_CURVE('E1586',#1960,#1962,#1958,.F.);
#1964=ORIENTED_EDGE('',*,*,#1963,.F.);
#1965=DIRECTION('',(0.,-1.,0.));
#1966=VECTOR('',#1965,1.);
#1967=CARTESIAN_POINT('',(42.4500000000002,86.3500000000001,0.));
#1968=LINE('',#1967,#1966);
#1969=CARTESIAN_POINT('',(42.4499999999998,256.5,0.));
#1970=VERTEX_POINT('',#1969);
#1971=EDGE_CURVE('E1568',#1960,#1970,#1968,.T.);
#1972=ORIENTED_EDGE('',*,*,#1971,.T.);
#1973=CARTESIAN_POINT('',(42.4499999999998,253.5,0.));
#1974=DIRECTION('',(0.,0.,1.));
#1975=DIRECTION('',(1.,0.,0.));
#1976=AXIS2_PLACEMENT_3D('',#1973,#1974,#1975);
#1977=CIRCLE('',#1976,3.);
#1978=CARTESIAN_POINT('',(42.4499999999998,250.5,0.));
#1979=VERTEX_POINT('',#1978);
#1980=EDGE_CURVE('E1571',#1970,#1979,#1977,.T.);
#1981=ORIENTED_EDGE('',*,*,#1980,.T.);
#1982=DIRECTION('',(1.,0.,0.));
#1983=VECTOR('',#1982,1.);
#1984=CARTESIAN_POINT('',(15.,250.5,0.));
#1985=LINE('',#1984,#1983);
#1986=CARTESIAN_POINT('',(57.5499999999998,250.5,0.));
#1987=VERTEX_POINT('',#1986);
#1988=EDGE_CURVE('E1574',#1979,#1987,#1985,.T.);
#1989=ORIENTED_EDGE('',*,*,#1988,.T.);
#1990=CARTESIAN_POINT('',(57.5499999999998,253.5,0.));
#1991=DIRECTION('',(0.,0.,1.));
#1992=DIRECTION('',(1.,0.,0.));
#1993=AXIS2_PLACEMENT_3D('',#1990,#1991,#1992);
#1994=CIRCLE('',#1993,3.);
#1995=CARTESIAN_POINT('',(57.5499999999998,256.5,0.));
#1996=VERTEX_POINT('',#1995);
#1997=EDGE_CURVE('E1577',#1996,#1987,#1994,.F.);
#1998=ORIENTED_EDGE('',*,*,#1997,.F.);
#1999=DIRECTION('',(0.,1.,0.));
#2000=VECTOR('',#1999,1.);
#2001=CARTESIAN_POINT('',(57.5499999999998,86.35,0.));
#2002=LINE('',#2001,#2000);
#2003=CARTESIAN_POINT('',(57.5499999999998,259.6,0.));
#2004=VERTEX_POINT('',#2003);
#2005=EDGE_CURVE('E1579',#1996,#2004,#2002,.T.);
#2006=ORIENTED_EDGE('',*,*,#2005,.T.);
#2007=CARTESIAN_POINT('',(57.5499999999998,262.6,0.));
#2008=DIRECTION('',(0.,0.,1.));
#2009=DIRECTION('',(1.,0.,0.));
#2010=AXIS2_PLACEMENT_3D('',#2007,#2008,#2009);
#2011=CIRCLE('',#2010,3.);
#2012=CARTESIAN_POINT('',(57.5499999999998,265.6,0.));
#2013=VERTEX_POINT('',#2012);
#2014=EDGE_CURVE('E1582',#2013,#2004,#2011,.F.);
#2015=ORIENTED_EDGE('',*,*,#2014,.F.);
#2016=DIRECTION('',(1.,0.,0.));
#2017=VECTOR('',#2016,1.);
#2018=CARTESIAN_POINT('',(15.,265.6,0.));
#2019=LINE('',#2018,#2017);
#2020=EDGE_CURVE('E1584',#1962,#2013,#2019,.T.);
#2021=ORIENTED_EDGE('',*,*,#2020,.F.);
#2022=EDGE_LOOP('',(#1964,#1972,#1981,#1989,#1998,#2006,#2015,#2021));
#2023=FACE_BOUND('',#2022,.T.);
#2024=CARTESIAN_POINT('',(42.4499999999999,57.2,0.));
#2025=DIRECTION('',(0.,0.,1.));
#2026=DIRECTION('',(1.,0.,0.));
#2027=AXIS2_PLACEMENT_3D('',#2024,#2025,#2026);
#2028=CIRCLE('',#2027,3.);
#2029=CARTESIAN_POINT('',(42.4499999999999,54.2,0.));
#2030=VERTEX_POINT('',#2029);
#2031=CARTESIAN_POINT('',(42.4499999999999,60.2,0.));
#2032=VERTEX_POINT('',#2031);
#2033=EDGE_CURVE('E1626',#2030,#2032,#2028,.F.);
#2034=ORIENTED_EDGE('',*,*,#2033,.F.);
#2035=DIRECTION('',(0.,-1.,0.));
#2036=VECTOR('',#2035,1.);
#2037=CARTESIAN_POINT('',(42.4499999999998,86.3500000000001,0.));
#2038=LINE('',#2037,#2036);
#2039=CARTESIAN_POINT('',(42.4499999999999,51.1,0.));
#2040=VERTEX_POINT('',#2039);
#2041=EDGE_CURVE('E1608',#2030,#2040,#2038,.T.);
#2042=ORIENTED_EDGE('',*,*,#2041,.T.);
#2043=CARTESIAN_POINT('',(42.4499999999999,48.1,0.));
#2044=DIRECTION('',(0.,0.,1.));
#2045=DIRECTION('',(1.,0.,0.));
#2046=AXIS2_PLACEMENT_3D('',#2043,#2044,#2045);
#2047=CIRCLE('',#2046,3.);
#2048=CARTESIAN_POINT('',(42.4499999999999,45.1,0.));
#2049=VERTEX_POINT('',#2048);
#2050=EDGE_CURVE('E1611',#2040,#2049,#2047,.T.);
#2051=ORIENTED_EDGE('',*,*,#2050,.T.);
#2052=DIRECTION('',(1.,0.,0.));
#2053=VECTOR('',#2052,1.);
#2054=CARTESIAN_POINT('',(15.,45.1,0.));
#2055=LINE('',#2054,#2053);
#2056=CARTESIAN_POINT('',(57.5499999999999,45.1,0.));
#2057=VERTEX_POINT('',#2056);
#2058=EDGE_CURVE('E1614',#2049,#2057,#2055,.T.);
#2059=ORIENTED_EDGE('',*,*,#2058,.T.);
#2060=CARTESIAN_POINT('',(57.5499999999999,48.1,0.));
#2061=DIRECTION('',(0.,0.,1.));
#2062=DIRECTION('',(1.,0.,0.));
#2063=AXIS2_PLACEMENT_3D('',#2060,#2061,#2062);
#2064=CIRCLE('',#2063,3.);
#2065=CARTESIAN_POINT('',(57.5499999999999,51.1,0.));
#2066=VERTEX_POINT('',#2065);
#2067=EDGE_CURVE('E1617',#2066,#2057,#2064,.F.);
#2068=ORIENTED_EDGE('',*,*,#2067,.F.);
#2069=DIRECTION('',(0.,1.,0.));
#2070=VECTOR('',#2069,1.);
#2071=CARTESIAN_POINT('',(57.55,86.3499999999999,0.));
#2072=LINE('',#2071,#2070);
#2073=CARTESIAN_POINT('',(57.5499999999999,54.2,0.));
#2074=VERTEX_POINT('',#2073);
#2075=EDGE_CURVE('E1619',#2066,#2074,#2072,.T.);
#2076=ORIENTED_EDGE('',*,*,#2075,.T.);
#2077=CARTESIAN_POINT('',(57.5499999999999,57.2,0.));
#2078=DIRECTION('',(0.,0.,1.));
#2079=DIRECTION('',(1.,0.,0.));
#2080=AXIS2_PLACEMENT_3D('',#2077,#2078,#2079);
#2081=CIRCLE('',#2080,3.);
#2082=CARTESIAN_POINT('',(57.5499999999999,60.2,0.));
#2083=VERTEX_POINT('',#2082);
#2084=EDGE_CURVE('E1622',#2083,#2074,#2081,.F.);
#2085=ORIENTED_EDGE('',*,*,#2084,.F.);
#2086=DIRECTION('',(1.,0.,0.));
#2087=VECTOR('',#2086,1.);
#2088=CARTESIAN_POINT('',(15.,60.2,0.));
#2089=LINE('',#2088,#2087);
#2090=EDGE_CURVE('E1624',#2032,#2083,#2089,.T.);
#2091=ORIENTED_EDGE('',*,*,#2090,.F.);
#2092=EDGE_LOOP('',(#2034,#2042,#2051,#2059,#2068,#2076,#2085,#2091));
#2093=FACE_BOUND('',#2092,.T.);
#2094=CARTESIAN_POINT('',(42.4499999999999,202.4,0.));
#2095=DIRECTION('',(0.,0.,1.));
#2096=DIRECTION('',(1.,0.,0.));
#2097=AXIS2_PLACEMENT_3D('',#2094,#2095,#2096);
#2098=CIRCLE('',#2097,3.);
#2099=CARTESIAN_POINT('',(42.4499999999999,199.4,0.));
#2100=VERTEX_POINT('',#2099);
#2101=CARTESIAN_POINT('',(42.4499999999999,205.4,0.));
#2102=VERTEX_POINT('',#2101);
#2103=EDGE_CURVE('E11',#2100,#2102,#2098,.F.);
#2104=ORIENTED_EDGE('',*,*,#2103,.F.);
#2105=DIRECTION('',(0.,-1.,0.));
#2106=VECTOR('',#2105,1.);
#2107=CARTESIAN_POINT('',(42.4500000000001,86.3500000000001,0.));
#2108=LINE('',#2107,#2106);
#2109=CARTESIAN_POINT('',(42.4499999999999,196.3,0.));
#2110=VERTEX_POINT('',#2109);
#2111=EDGE_CURVE('E1648',#2100,#2110,#2108,.T.);
#2112=ORIENTED_EDGE('',*,*,#2111,.T.);
#2113=CARTESIAN_POINT('',(42.4499999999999,193.3,0.));
#2114=DIRECTION('',(0.,0.,1.));
#2115=DIRECTION('',(1.,0.,0.));
#2116=AXIS2_PLACEMENT_3D('',#2113,#2114,#2115);
#2117=CIRCLE('',#2116,3.);
#2118=CARTESIAN_POINT('',(42.4499999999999,190.3,0.));
#2119=VERTEX_POINT('',#2118);
#2120=EDGE_CURVE('E1651',#2110,#2119,#2117,.T.);
#2121=ORIENTED_EDGE('',*,*,#2120,.T.);
#2122=DIRECTION('',(1.,0.,0.));
#2123=VECTOR('',#2122,1.);
#2124=CARTESIAN_POINT('',(14.9999999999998,190.3,0.));
#2125=LINE('',#2124,#2123);
#2126=CARTESIAN_POINT('',(57.5499999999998,190.3,0.));
#2127=VERTEX_POINT('',#2126);
#2128=EDGE_CURVE('E1654',#2119,#2127,#2125,.T.);
#2129=ORIENTED_EDGE('',*,*,#2128,.T.);
#2130=CARTESIAN_POINT('',(57.5499999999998,193.3,0.));
#2131=DIRECTION('',(0.,0.,1.));
#2132=DIRECTION('',(1.,0.,0.));
#2133=AXIS2_PLACEMENT_3D('',#2130,#2131,#2132);
#2134=CIRCLE('',#2133,2.99999999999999);
#2135=CARTESIAN_POINT('',(57.5499999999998,196.3,0.));
#2136=VERTEX_POINT('',#2135);
#2137=EDGE_CURVE('E1657',#2136,#2127,#2134,.F.);
#2138=ORIENTED_EDGE('',*,*,#2137,.F.);
#2139=DIRECTION('',(0.,1.,0.));
#2140=VECTOR('',#2139,1.);
#2141=CARTESIAN_POINT('',(57.5499999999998,86.35,0.));
#2142=LINE('',#2141,#2140);
#2143=CARTESIAN_POINT('',(57.5499999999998,199.4,0.));
#2144=VERTEX_POINT('',#2143);
#2145=EDGE_CURVE('E1659',#2136,#2144,#2142,.T.);
#2146=ORIENTED_EDGE('',*,*,#2145,.T.);
#2147=CARTESIAN_POINT('',(57.5499999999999,202.4,0.));
#2148=DIRECTION('',(0.,0.,1.));
#2149=DIRECTION('',(1.,0.,0.));
#2150=AXIS2_PLACEMENT_3D('',#2147,#2148,#2149);
#2151=CIRCLE('',#2150,3.);
#2152=CARTESIAN_POINT('',(57.5499999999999,205.4,0.));
#2153=VERTEX_POINT('',#2152);
#2154=EDGE_CURVE('E1662',#2153,#2144,#2151,.F.);
#2155=ORIENTED_EDGE('',*,*,#2154,.F.);
#2156=DIRECTION('',(1.,0.,0.));
#2157=VECTOR('',#2156,1.);
#2158=CARTESIAN_POINT('',(15.,205.4,0.));
#2159=LINE('',#2158,#2157);
#2160=EDGE_CURVE('E44',#2102,#2153,#2159,.T.);
#2161=ORIENTED_EDGE('',*,*,#2160,.F.);
#2162=EDGE_LOOP('',(#2104,#2112,#2121,#2129,#2138,#2146,#2155,#2161));
#2163=FACE_BOUND('',#2162,.T.);
#2164=ADVANCED_FACE('F1671',(#1118,#1188,#1258,#1328,#1953,#2023,#2093,#2163),#1107,.F.);
#2165=CARTESIAN_POINT('',(15.,86.35,15.));
#2166=DIRECTION('',(0.,0.,-1.));
#2167=DIRECTION('',(-1.,0.,0.));
#2168=AXIS2_PLACEMENT_3D('',#2165,#2166,#2167);
#2169=CYLINDRICAL_SURFACE('',#2168,3.75);
#2170=ORIENTED_EDGE('',*,*,#1338,.T.);
#2171=DIRECTION('',(0.,0.,-1.));
#2172=VECTOR('',#2171,1.);
#2173=CARTESIAN_POINT('',(15.,82.6,15.));
#2174=LINE('',#2173,#2172);
#2175=EDGE_CURVE('E1545',#275,#1337,#2174,.T.);
#2176=ORIENTED_EDGE('',*,*,#2175,.F.);
#2177=ORIENTED_EDGE('',*,*,#276,.F.);
#2178=DIRECTION('',(0.,0.,-1.));
#2179=VECTOR('',#2178,1.);
#2180=CARTESIAN_POINT('',(15.,90.1,15.));
#2181=LINE('',#2180,#2179);
#2182=EDGE_CURVE('E1174',#273,#1335,#2181,.T.);
#2183=ORIENTED_EDGE('',*,*,#2182,.T.);
#2184=EDGE_LOOP('',(#2170,#2176,#2177,#2183));
#2185=FACE_BOUND('',#2184,.T.);
#2186=ADVANCED_FACE('F37',(#2185),#2169,.F.);
#2187=CARTESIAN_POINT('',(0.,82.6,15.));
#2188=DIRECTION('',(0.,-1.,0.));
#2189=DIRECTION('',(0.,0.,-1.));
#2190=AXIS2_PLACEMENT_3D('',#2187,#2188,#2189);
#2191=PLANE('',#2190);
#2192=ORIENTED_EDGE('',*,*,#1950,.T.);
#2193=DIRECTION('',(0.,0.,-1.));
#2194=VECTOR('',#2193,1.);
#2195=CARTESIAN_POINT('',(0.,82.6,15.));
#2196=LINE('',#2195,#2194);
#2197=EDGE_CURVE('E1542',#283,#1943,#2196,.T.);
#2198=ORIENTED_EDGE('',*,*,#2197,.F.);
#2199=ORIENTED_EDGE('',*,*,#284,.F.);
#2200=ORIENTED_EDGE('',*,*,#2175,.T.);
#2201=EDGE_LOOP('',(#2192,#2198,#2199,#2200));
#2202=FACE_BOUND('',#2201,.T.);
#2203=ADVANCED_FACE('F2040',(#2202),#2191,.F.);
#2204=CARTESIAN_POINT('',(0.,82.6,15.));
#2205=DIRECTION('',(1.,0.,0.));
#2206=DIRECTION('',(0.,0.,-1.));
#2207=AXIS2_PLACEMENT_3D('',#2204,#2205,#2206);
#2208=PLANE('',#2207);
#2209=ORIENTED_EDGE('',*,*,#1944,.T.);
#2210=DIRECTION('',(0.,0.,-1.));
#2211=VECTOR('',#2210,1.);
#2212=CARTESIAN_POINT('',(0.,67.6,15.));
#2213=LINE('',#2212,#2211);
#2214=EDGE_CURVE('E1539',#291,#1935,#2213,.T.);
#2215=ORIENTED_EDGE('',*,*,#2214,.F.);
#2216=ORIENTED_EDGE('',*,*,#292,.F.);
#2217=ORIENTED_EDGE('',*,*,#2197,.T.);
#2218=EDGE_LOOP('',(#2209,#2215,#2216,#2217));
#2219=FACE_BOUND('',#2218,.T.);
#2220=ADVANCED_FACE('F2037',(#2219),#2208,.F.);
#2221=CARTESIAN_POINT('',(0.,67.6,15.));
#2222=DIRECTION('',(0.,1.,0.));
#2223=DIRECTION('',(0.,0.,1.));
#2224=AXIS2_PLACEMENT_3D('',#2221,#2222,#2223);
#2225=PLANE('',#2224);
#2226=ORIENTED_EDGE('',*,*,#1936,.T.);
#2227=DIRECTION('',(0.,0.,-1.));
#2228=VECTOR('',#2227,1.);
#2229=CARTESIAN_POINT('',(15.,67.6,15.));
#2230=LINE('',#2229,#2228);
#2231=EDGE_CURVE('E1536',#299,#1927,#2230,.T.);
#2232=ORIENTED_EDGE('',*,*,#2231,.F.);
#2233=ORIENTED_EDGE('',*,*,#300,.F.);
#2234=ORIENTED_EDGE('',*,*,#2214,.T.);
#2235=EDGE_LOOP('',(#2226,#2232,#2233,#2234));
#2236=FACE_BOUND('',#2235,.T.);
#2237=ADVANCED_FACE('F2033',(#2236),#2225,.F.);
#2238=CARTESIAN_POINT('',(15.,64.6,15.));
#2239=DIRECTION('',(0.,0.,-1.));
#2240=DIRECTION('',(-1.,0.,0.));
#2241=AXIS2_PLACEMENT_3D('',#2238,#2239,#2240);
#2242=CYLINDRICAL_SURFACE('',#2241,3.);
#2243=ORIENTED_EDGE('',*,*,#1928,.T.);
#2244=DIRECTION('',(0.,0.,-1.));
#2245=VECTOR('',#2244,1.);
#2246=CARTESIAN_POINT('',(15.,61.6,15.));
#2247=LINE('',#2246,#2245);
#2248=EDGE_CURVE('E1533',#308,#1918,#2247,.T.);
#2249=ORIENTED_EDGE('',*,*,#2248,.F.);
#2250=ORIENTED_EDGE('',*,*,#309,.F.);
#2251=ORIENTED_EDGE('',*,*,#2231,.T.);
#2252=EDGE_LOOP('',(#2243,#2249,#2250,#2251));
#2253=FACE_BOUND('',#2252,.T.);
#2254=ADVANCED_FACE('F2029',(#2253),#2242,.F.);
#2255=CARTESIAN_POINT('',(15.,61.6,15.));
#2256=DIRECTION('',(1.,0.,0.));
#2257=DIRECTION('',(0.,1.,0.));
#2258=AXIS2_PLACEMENT_3D('',#2255,#2256,#2257);
#2259=PLANE('',#2258);
#2260=ORIENTED_EDGE('',*,*,#1919,.T.);
#2261=DIRECTION('',(0.,0.,-1.));
#2262=VECTOR('',#2261,1.);
#2263=CARTESIAN_POINT('',(15.,58.5,15.));
#2264=LINE('',#2263,#2262);
#2265=EDGE_CURVE('E1530',#316,#1910,#2264,.T.);
#2266=ORIENTED_EDGE('',*,*,#2265,.F.);
#2267=ORIENTED_EDGE('',*,*,#317,.F.);
#2268=ORIENTED_EDGE('',*,*,#2248,.T.);
#2269=EDGE_LOOP('',(#2260,#2266,#2267,#2268));
#2270=FACE_BOUND('',#2269,.T.);
#2271=ADVANCED_FACE('F2025',(#2270),#2259,.F.);
#2272=CARTESIAN_POINT('',(15.,55.5,15.));
#2273=DIRECTION('',(0.,0.,-1.));
#2274=DIRECTION('',(-1.,0.,0.));
#2275=AXIS2_PLACEMENT_3D('',#2272,#2273,#2274);
#2276=CYLINDRICAL_SURFACE('',#2275,3.);
#2277=ORIENTED_EDGE('',*,*,#1911,.T.);
#2278=DIRECTION('',(0.,0.,-1.));
#2279=VECTOR('',#2278,1.);
#2280=CARTESIAN_POINT('',(15.,52.5,15.));
#2281=LINE('',#2280,#2279);
#2282=EDGE_CURVE('E1527',#325,#1901,#2281,.T.);
#2283=ORIENTED_EDGE('',*,*,#2282,.F.);
#2284=ORIENTED_EDGE('',*,*,#326,.F.);
#2285=ORIENTED_EDGE('',*,*,#2265,.T.);
#2286=EDGE_LOOP('',(#2277,#2283,#2284,#2285));
#2287=FACE_BOUND('',#2286,.T.);
#2288=ADVANCED_FACE('F2021',(#2287),#2276,.F.);
#2289=CARTESIAN_POINT('',(15.,52.5,15.));
#2290=DIRECTION('',(0.,-1.,0.));
#2291=DIRECTION('',(0.,0.,-1.));
#2292=AXIS2_PLACEMENT_3D('',#2289,#2290,#2291);
#2293=PLANE('',#2292);
#2294=ORIENTED_EDGE('',*,*,#1902,.T.);
#2295=DIRECTION('',(0.,0.,-1.));
#2296=VECTOR('',#2295,1.);
#2297=CARTESIAN_POINT('',(0.,52.5,15.));
#2298=LINE('',#2297,#2296);
#2299=EDGE_CURVE('E1524',#333,#1893,#2298,.T.);
#2300=ORIENTED_EDGE('',*,*,#2299,.F.);
#2301=ORIENTED_EDGE('',*,*,#334,.F.);
#2302=ORIENTED_EDGE('',*,*,#2282,.T.);
#2303=EDGE_LOOP('',(#2294,#2300,#2301,#2302));
#2304=FACE_BOUND('',#2303,.T.);
#2305=ADVANCED_FACE('F2017',(#2304),#2293,.F.);
#2306=CARTESIAN_POINT('',(0.,52.5,15.));
#2307=DIRECTION('',(1.,0.,0.));
#2308=DIRECTION('',(0.,0.,-1.));
#2309=AXIS2_PLACEMENT_3D('',#2306,#2307,#2308);
#2310=PLANE('',#2309);
#2311=ORIENTED_EDGE('',*,*,#1894,.T.);
#2312=DIRECTION('',(0.,0.,-1.));
#2313=VECTOR('',#2312,1.);
#2314=CARTESIAN_POINT('',(0.,37.5,15.));
#2315=LINE('',#2314,#2313);
#2316=EDGE_CURVE('E1521',#341,#1885,#2315,.T.);
#2317=ORIENTED_EDGE('',*,*,#2316,.F.);
#2318=ORIENTED_EDGE('',*,*,#342,.F.);
#2319=ORIENTED_EDGE('',*,*,#2299,.T.);
#2320=EDGE_LOOP('',(#2311,#2317,#2318,#2319));
#2321=FACE_BOUND('',#2320,.T.);
#2322=ADVANCED_FACE('F2013',(#2321),#2310,.F.);
#2323=CARTESIAN_POINT('',(0.,37.5,15.));
#2324=DIRECTION('',(0.,1.,0.));
#2325=DIRECTION('',(0.,0.,1.));
#2326=AXIS2_PLACEMENT_3D('',#2323,#2324,#2325);
#2327=PLANE('',#2326);
#2328=ORIENTED_EDGE('',*,*,#1886,.T.);
#2329=DIRECTION('',(0.,0.,-1.));
#2330=VECTOR('',#2329,1.);
#2331=CARTESIAN_POINT('',(15.,37.5,15.));
#2332=LINE('',#2331,#2330);
#2333=EDGE_CURVE('E1518',#349,#1877,#2332,.T.);
#2334=ORIENTED_EDGE('',*,*,#2333,.F.);
#2335=ORIENTED_EDGE('',*,*,#350,.F.);
#2336=ORIENTED_EDGE('',*,*,#2316,.T.);
#2337=EDGE_LOOP('',(#2328,#2334,#2335,#2336));
#2338=FACE_BOUND('',#2337,.T.);
#2339=ADVANCED_FACE('F2009',(#2338),#2327,.F.);
#2340=CARTESIAN_POINT('',(15.,34.5,15.));
#2341=DIRECTION('',(0.,0.,-1.));
#2342=DIRECTION('',(-1.,0.,0.));
#2343=AXIS2_PLACEMENT_3D('',#2340,#2341,#2342);
#2344=CYLINDRICAL_SURFACE('',#2343,3.);
#2345=ORIENTED_EDGE('',*,*,#1878,.T.);
#2346=DIRECTION('',(0.,0.,-1.));
#2347=VECTOR('',#2346,1.);
#2348=CARTESIAN_POINT('',(15.,31.5,15.));
#2349=LINE('',#2348,#2347);
#2350=EDGE_CURVE('E1515',#358,#1868,#2349,.T.);
#2351=ORIENTED_EDGE('',*,*,#2350,.F.);
#2352=ORIENTED_EDGE('',*,*,#359,.F.);
#2353=ORIENTED_EDGE('',*,*,#2333,.T.);
#2354=EDGE_LOOP('',(#2345,#2351,#2352,#2353));
#2355=FACE_BOUND('',#2354,.T.);
#2356=ADVANCED_FACE('F2005',(#2355),#2344,.F.);
#2357=CARTESIAN_POINT('',(15.,31.5,15.));
#2358=DIRECTION('',(1.,0.,0.));
#2359=DIRECTION('',(0.,0.,-1.));
#2360=AXIS2_PLACEMENT_3D('',#2357,#2358,#2359);
#2361=PLANE('',#2360);
#2362=ORIENTED_EDGE('',*,*,#1869,.T.);
#2363=DIRECTION('',(0.,0.,-1.));
#2364=VECTOR('',#2363,1.);
#2365=CARTESIAN_POINT('',(15.,28.4,15.));
#2366=LINE('',#2365,#2364);
#2367=EDGE_CURVE('E1512',#366,#1860,#2366,.T.);
#2368=ORIENTED_EDGE('',*,*,#2367,.F.);
#2369=ORIENTED_EDGE('',*,*,#367,.F.);
#2370=ORIENTED_EDGE('',*,*,#2350,.T.);
#2371=EDGE_LOOP('',(#2362,#2368,#2369,#2370));
#2372=FACE_BOUND('',#2371,.T.);
#2373=ADVANCED_FACE('F2001',(#2372),#2361,.F.);
#2374=CARTESIAN_POINT('',(15.,25.4,15.));
#2375=DIRECTION('',(0.,0.,-1.));
#2376=DIRECTION('',(-1.,0.,0.));
#2377=AXIS2_PLACEMENT_3D('',#2374,#2375,#2376);
#2378=CYLINDRICAL_SURFACE('',#2377,3.);
#2379=ORIENTED_EDGE('',*,*,#1861,.T.);
#2380=DIRECTION('',(0.,0.,-1.));
#2381=VECTOR('',#2380,1.);
#2382=CARTESIAN_POINT('',(15.,22.4,15.));
#2383=LINE('',#2382,#2381);
#2384=EDGE_CURVE('E1509',#375,#1851,#2383,.T.);
#2385=ORIENTED_EDGE('',*,*,#2384,.F.);
#2386=ORIENTED_EDGE('',*,*,#376,.F.);
#2387=ORIENTED_EDGE('',*,*,#2367,.T.);
#2388=EDGE_LOOP('',(#2379,#2385,#2386,#2387));
#2389=FACE_BOUND('',#2388,.T.);
#2390=ADVANCED_FACE('F1997',(#2389),#2378,.F.);
#2391=CARTESIAN_POINT('',(15.,22.4,15.));
#2392=DIRECTION('',(0.,-1.,0.));
#2393=DIRECTION('',(1.,0.,0.));
#2394=AXIS2_PLACEMENT_3D('',#2391,#2392,#2393);
#2395=PLANE('',#2394);
#2396=ORIENTED_EDGE('',*,*,#1852,.T.);
#2397=DIRECTION('',(0.,0.,-1.));
#2398=VECTOR('',#2397,1.);
#2399=CARTESIAN_POINT('',(0.,22.4,15.));
#2400=LINE('',#2399,#2398);
#2401=EDGE_CURVE('E1506',#383,#1843,#2400,.T.);
#2402=ORIENTED_EDGE('',*,*,#2401,.F.);
#2403=ORIENTED_EDGE('',*,*,#384,.F.);
#2404=ORIENTED_EDGE('',*,*,#2384,.T.);
#2405=EDGE_LOOP('',(#2396,#2402,#2403,#2404));
#2406=FACE_BOUND('',#2405,.T.);
#2407=ADVANCED_FACE('F1993',(#2406),#2395,.F.);
#2408=CARTESIAN_POINT('',(0.,22.4,15.));
#2409=DIRECTION('',(1.,0.,0.));
#2410=DIRECTION('',(0.,0.,-1.));
#2411=AXIS2_PLACEMENT_3D('',#2408,#2409,#2410);
#2412=PLANE('',#2411);
#2413=ORIENTED_EDGE('',*,*,#1844,.T.);
#2414=DIRECTION('',(0.,0.,-1.));
#2415=VECTOR('',#2414,1.);
#2416=CARTESIAN_POINT('',(0.,7.4,15.));
#2417=LINE('',#2416,#2415);
#2418=EDGE_CURVE('E1503',#391,#1835,#2417,.T.);
#2419=ORIENTED_EDGE('',*,*,#2418,.F.);
#2420=ORIENTED_EDGE('',*,*,#392,.F.);
#2421=ORIENTED_EDGE('',*,*,#2401,.T.);
#2422=EDGE_LOOP('',(#2413,#2419,#2420,#2421));
#2423=FACE_BOUND('',#2422,.T.);
#2424=ADVANCED_FACE('F1989',(#2423),#2412,.F.);
#2425=CARTESIAN_POINT('',(0.,7.4,15.));
#2426=DIRECTION('',(0.,1.,0.));
#2427=DIRECTION('',(0.,0.,1.));
#2428=AXIS2_PLACEMENT_3D('',#2425,#2426,#2427);
#2429=PLANE('',#2428);
#2430=ORIENTED_EDGE('',*,*,#1836,.T.);
#2431=DIRECTION('',(0.,0.,-1.));
#2432=VECTOR('',#2431,1.);
#2433=CARTESIAN_POINT('',(15.,7.4,15.));
#2434=LINE('',#2433,#2432);
#2435=EDGE_CURVE('E1500',#399,#1827,#2434,.T.);
#2436=ORIENTED_EDGE('',*,*,#2435,.F.);
#2437=ORIENTED_EDGE('',*,*,#400,.F.);
#2438=ORIENTED_EDGE('',*,*,#2418,.T.);
#2439=EDGE_LOOP('',(#2430,#2436,#2437,#2438));
#2440=FACE_BOUND('',#2439,.T.);
#2441=ADVANCED_FACE('F1985',(#2440),#2429,.F.);
#2442=CARTESIAN_POINT('',(15.,4.4,15.));
#2443=DIRECTION('',(0.,0.,-1.));
#2444=DIRECTION('',(-1.,0.,0.));
#2445=AXIS2_PLACEMENT_3D('',#2442,#2443,#2444);
#2446=CYLINDRICAL_SURFACE('',#2445,3.);
#2447=ORIENTED_EDGE('',*,*,#1828,.T.);
#2448=DIRECTION('',(0.,0.,-1.));
#2449=VECTOR('',#2448,1.);
#2450=CARTESIAN_POINT('',(15.,1.4,15.));
#2451=LINE('',#2450,#2449);
#2452=EDGE_CURVE('E1497',#408,#1818,#2451,.T.);
#2453=ORIENTED_EDGE('',*,*,#2452,.F.);
#2454=ORIENTED_EDGE('',*,*,#409,.F.);
#2455=ORIENTED_EDGE('',*,*,#2435,.T.);
#2456=EDGE_LOOP('',(#2447,#2453,#2454,#2455));
#2457=FACE_BOUND('',#2456,.T.);
#2458=ADVANCED_FACE('F1981',(#2457),#2446,.F.);
#2459=CARTESIAN_POINT('',(15.,1.4,15.));
#2460=DIRECTION('',(1.,0.,0.));
#2461=DIRECTION('',(0.,0.,-1.));
#2462=AXIS2_PLACEMENT_3D('',#2459,#2460,#2461);
#2463=PLANE('',#2462);
#2464=ORIENTED_EDGE('',*,*,#1819,.T.);
#2465=DIRECTION('',(0.,0.,-1.));
#2466=VECTOR('',#2465,1.);
#2467=CARTESIAN_POINT('',(15.,0.,15.));
#2468=LINE('',#2467,#2466);
#2469=EDGE_CURVE('E1494',#416,#1810,#2468,.T.);
#2470=ORIENTED_EDGE('',*,*,#2469,.F.);
#2471=ORIENTED_EDGE('',*,*,#417,.F.);
#2472=ORIENTED_EDGE('',*,*,#2452,.T.);
#2473=EDGE_LOOP('',(#2464,#2470,#2471,#2472));
#2474=FACE_BOUND('',#2473,.T.);
#2475=ADVANCED_FACE('F1977',(#2474),#2463,.F.);
#2476=CARTESIAN_POINT('',(85.,0.,15.));
#2477=DIRECTION('',(0.,1.,0.));
#2478=DIRECTION('',(0.,0.,1.));
#2479=AXIS2_PLACEMENT_3D('',#2476,#2477,#2478);
#2480=PLANE('',#2479);
#2481=ORIENTED_EDGE('',*,*,#1811,.T.);
#2482=DIRECTION('',(0.,0.,-1.));
#2483=VECTOR('',#2482,1.);
#2484=CARTESIAN_POINT('',(85.,0.,15.));
#2485=LINE('',#2484,#2483);
#2486=EDGE_CURVE('E1491',#424,#1802,#2485,.T.);
#2487=ORIENTED_EDGE('',*,*,#2486,.F.);
#2488=ORIENTED_EDGE('',*,*,#425,.F.);
#2489=ORIENTED_EDGE('',*,*,#2469,.T.);
#2490=EDGE_LOOP('',(#2481,#2487,#2488,#2489));
#2491=FACE_BOUND('',#2490,.T.);
#2492=ADVANCED_FACE('F1973',(#2491),#2480,.F.);
#2493=CARTESIAN_POINT('',(85.,1.39999999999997,15.));
#2494=DIRECTION('',(-1.,0.,0.));
#2495=DIRECTION('',(0.,-1.,0.));
#2496=AXIS2_PLACEMENT_3D('',#2493,#2494,#2495);
#2497=PLANE('',#2496);
#2498=ORIENTED_EDGE('',*,*,#1803,.T.);
#2499=DIRECTION('',(0.,0.,-1.));
#2500=VECTOR('',#2499,1.);
#2501=CARTESIAN_POINT('',(85.,1.39999999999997,15.));
#2502=LINE('',#2501,#2500);
#2503=EDGE_CURVE('E1488',#432,#1794,#2502,.T.);
#2504=ORIENTED_EDGE('',*,*,#2503,.F.);
#2505=ORIENTED_EDGE('',*,*,#433,.F.);
#2506=ORIENTED_EDGE('',*,*,#2486,.T.);
#2507=EDGE_LOOP('',(#2498,#2504,#2505,#2506));
#2508=FACE_BOUND('',#2507,.T.);
#2509=ADVANCED_FACE('F1969',(#2508),#2497,.F.);
#2510=CARTESIAN_POINT('',(85.,4.39999999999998,15.));
#2511=DIRECTION('',(0.,0.,-1.));
#2512=DIRECTION('',(-1.,0.,0.));
#2513=AXIS2_PLACEMENT_3D('',#2510,#2511,#2512);
#2514=CYLINDRICAL_SURFACE('',#2513,3.00000000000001);
#2515=ORIENTED_EDGE('',*,*,#1795,.T.);
#2516=DIRECTION('',(0.,0.,-1.));
#2517=VECTOR('',#2516,1.);
#2518=CARTESIAN_POINT('',(85.,7.39999999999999,15.));
#2519=LINE('',#2518,#2517);
#2520=EDGE_CURVE('E1485',#441,#1785,#2519,.T.);
#2521=ORIENTED_EDGE('',*,*,#2520,.F.);
#2522=ORIENTED_EDGE('',*,*,#442,.F.);
#2523=ORIENTED_EDGE('',*,*,#2503,.T.);
#2524=EDGE_LOOP('',(#2515,#2521,#2522,#2523));
#2525=FACE_BOUND('',#2524,.T.);
#2526=ADVANCED_FACE('F1965',(#2525),#2514,.F.);
#2527=CARTESIAN_POINT('',(100.,7.4,15.));
#2528=DIRECTION('',(0.,1.,0.));
#2529=DIRECTION('',(-1.,0.,0.));
#2530=AXIS2_PLACEMENT_3D('',#2527,#2528,#2529);
#2531=PLANE('',#2530);
#2532=ORIENTED_EDGE('',*,*,#1786,.T.);
#2533=DIRECTION('',(0.,0.,-1.));
#2534=VECTOR('',#2533,1.);
#2535=CARTESIAN_POINT('',(100.,7.4,15.));
#2536=LINE('',#2535,#2534);
#2537=EDGE_CURVE('E1482',#449,#1777,#2536,.T.);
#2538=ORIENTED_EDGE('',*,*,#2537,.F.);
#2539=ORIENTED_EDGE('',*,*,#450,.F.);
#2540=ORIENTED_EDGE('',*,*,#2520,.T.);
#2541=EDGE_LOOP('',(#2532,#2538,#2539,#2540));
#2542=FACE_BOUND('',#2541,.T.);
#2543=ADVANCED_FACE('F1961',(#2542),#2531,.F.);
#2544=CARTESIAN_POINT('',(100.,22.4,15.));
#2545=DIRECTION('',(-1.,0.,0.));
#2546=DIRECTION('',(0.,0.,1.));
#2547=AXIS2_PLACEMENT_3D('',#2544,#2545,#2546);
#2548=PLANE('',#2547);
#2549=ORIENTED_EDGE('',*,*,#1778,.T.);
#2550=DIRECTION('',(0.,0.,-1.));
#2551=VECTOR('',#2550,1.);
#2552=CARTESIAN_POINT('',(100.,22.4,15.));
#2553=LINE('',#2552,#2551);
#2554=EDGE_CURVE('E1479',#457,#1769,#2553,.T.);
#2555=ORIENTED_EDGE('',*,*,#2554,.F.);
#2556=ORIENTED_EDGE('',*,*,#458,.F.);
#2557=ORIENTED_EDGE('',*,*,#2537,.T.);
#2558=EDGE_LOOP('',(#2549,#2555,#2556,#2557));
#2559=FACE_BOUND('',#2558,.T.);
#2560=ADVANCED_FACE('F1957',(#2559),#2548,.F.);
#2561=CARTESIAN_POINT('',(85.,22.4,15.));
#2562=DIRECTION('',(0.,-1.,0.));
#2563=DIRECTION('',(1.,0.,0.));
#2564=AXIS2_PLACEMENT_3D('',#2561,#2562,#2563);
#2565=PLANE('',#2564);
#2566=ORIENTED_EDGE('',*,*,#1770,.T.);
#2567=DIRECTION('',(0.,0.,-1.));
#2568=VECTOR('',#2567,1.);
#2569=CARTESIAN_POINT('',(85.,22.4,15.));
#2570=LINE('',#2569,#2568);
#2571=EDGE_CURVE('E1476',#465,#1761,#2570,.T.);
#2572=ORIENTED_EDGE('',*,*,#2571,.F.);
#2573=ORIENTED_EDGE('',*,*,#466,.F.);
#2574=ORIENTED_EDGE('',*,*,#2554,.T.);
#2575=EDGE_LOOP('',(#2566,#2572,#2573,#2574));
#2576=FACE_BOUND('',#2575,.T.);
#2577=ADVANCED_FACE('F1953',(#2576),#2565,.F.);
#2578=CARTESIAN_POINT('',(85.0000000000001,25.4,15.));
#2579=DIRECTION('',(0.,0.,-1.));
#2580=DIRECTION('',(-1.,0.,0.));
#2581=AXIS2_PLACEMENT_3D('',#2578,#2579,#2580);
#2582=CYLINDRICAL_SURFACE('',#2581,3.);
#2583=ORIENTED_EDGE('',*,*,#1762,.T.);
#2584=DIRECTION('',(0.,0.,-1.));
#2585=VECTOR('',#2584,1.);
#2586=CARTESIAN_POINT('',(85.0000000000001,28.4,15.));
#2587=LINE('',#2586,#2585);
#2588=EDGE_CURVE('E1473',#474,#1752,#2587,.T.);
#2589=ORIENTED_EDGE('',*,*,#2588,.F.);
#2590=ORIENTED_EDGE('',*,*,#475,.F.);
#2591=ORIENTED_EDGE('',*,*,#2571,.T.);
#2592=EDGE_LOOP('',(#2583,#2589,#2590,#2591));
#2593=FACE_BOUND('',#2592,.T.);
#2594=ADVANCED_FACE('F1949',(#2593),#2582,.F.);
#2595=CARTESIAN_POINT('',(85.,31.5,15.));
#2596=DIRECTION('',(-1.,0.,0.));
#2597=DIRECTION('',(0.,-1.,0.));
#2598=AXIS2_PLACEMENT_3D('',#2595,#2596,#2597);
#2599=PLANE('',#2598);
#2600=ORIENTED_EDGE('',*,*,#1753,.T.);
#2601=DIRECTION('',(0.,0.,-1.));
#2602=VECTOR('',#2601,1.);
#2603=CARTESIAN_POINT('',(85.,31.5,15.));
#2604=LINE('',#2603,#2602);
#2605=EDGE_CURVE('E1470',#482,#1744,#2604,.T.);
#2606=ORIENTED_EDGE('',*,*,#2605,.F.);
#2607=ORIENTED_EDGE('',*,*,#483,.F.);
#2608=ORIENTED_EDGE('',*,*,#2588,.T.);
#2609=EDGE_LOOP('',(#2600,#2606,#2607,#2608));
#2610=FACE_BOUND('',#2609,.T.);
#2611=ADVANCED_FACE('F1945',(#2610),#2599,.F.);
#2612=CARTESIAN_POINT('',(85.,34.5,15.));
#2613=DIRECTION('',(0.,0.,-1.));
#2614=DIRECTION('',(-1.,0.,0.));
#2615=AXIS2_PLACEMENT_3D('',#2612,#2613,#2614);
#2616=CYLINDRICAL_SURFACE('',#2615,3.);
#2617=ORIENTED_EDGE('',*,*,#1745,.T.);
#2618=DIRECTION('',(0.,0.,-1.));
#2619=VECTOR('',#2618,1.);
#2620=CARTESIAN_POINT('',(85.,37.5,15.));
#2621=LINE('',#2620,#2619);
#2622=EDGE_CURVE('E1467',#491,#1735,#2621,.T.);
#2623=ORIENTED_EDGE('',*,*,#2622,.F.);
#2624=ORIENTED_EDGE('',*,*,#492,.F.);
#2625=ORIENTED_EDGE('',*,*,#2605,.T.);
#2626=EDGE_LOOP('',(#2617,#2623,#2624,#2625));
#2627=FACE_BOUND('',#2626,.T.);
#2628=ADVANCED_FACE('F1941',(#2627),#2616,.F.);
#2629=CARTESIAN_POINT('',(100.,37.5,15.));
#2630=DIRECTION('',(0.,1.,0.));
#2631=DIRECTION('',(-1.,0.,0.));
#2632=AXIS2_PLACEMENT_3D('',#2629,#2630,#2631);
#2633=PLANE('',#2632);
#2634=ORIENTED_EDGE('',*,*,#1736,.T.);
#2635=DIRECTION('',(0.,0.,-1.));
#2636=VECTOR('',#2635,1.);
#2637=CARTESIAN_POINT('',(100.,37.5,15.));
#2638=LINE('',#2637,#2636);
#2639=EDGE_CURVE('E1464',#499,#1727,#2638,.T.);
#2640=ORIENTED_EDGE('',*,*,#2639,.F.);
#2641=ORIENTED_EDGE('',*,*,#500,.F.);
#2642=ORIENTED_EDGE('',*,*,#2622,.T.);
#2643=EDGE_LOOP('',(#2634,#2640,#2641,#2642));
#2644=FACE_BOUND('',#2643,.T.);
#2645=ADVANCED_FACE('F1937',(#2644),#2633,.F.);
#2646=CARTESIAN_POINT('',(100.,52.5,15.));
#2647=DIRECTION('',(-1.,0.,0.));
#2648=DIRECTION('',(0.,-1.,0.));
#2649=AXIS2_PLACEMENT_3D('',#2646,#2647,#2648);
#2650=PLANE('',#2649);
#2651=ORIENTED_EDGE('',*,*,#1728,.T.);
#2652=DIRECTION('',(0.,0.,-1.));
#2653=VECTOR('',#2652,1.);
#2654=CARTESIAN_POINT('',(100.,52.5,15.));
#2655=LINE('',#2654,#2653);
#2656=EDGE_CURVE('E1461',#507,#1719,#2655,.T.);
#2657=ORIENTED_EDGE('',*,*,#2656,.F.);
#2658=ORIENTED_EDGE('',*,*,#508,.F.);
#2659=ORIENTED_EDGE('',*,*,#2639,.T.);
#2660=EDGE_LOOP('',(#2651,#2657,#2658,#2659));
#2661=FACE_BOUND('',#2660,.T.);
#2662=ADVANCED_FACE('F1933',(#2661),#2650,.F.);
#2663=CARTESIAN_POINT('',(85.,52.5,15.));
#2664=DIRECTION('',(0.,-1.,0.));
#2665=DIRECTION('',(0.,0.,-1.));
#2666=AXIS2_PLACEMENT_3D('',#2663,#2664,#2665);
#2667=PLANE('',#2666);
#2668=ORIENTED_EDGE('',*,*,#1720,.T.);
#2669=DIRECTION('',(0.,0.,-1.));
#2670=VECTOR('',#2669,1.);
#2671=CARTESIAN_POINT('',(85.,52.5,15.));
#2672=LINE('',#2671,#2670);
#2673=EDGE_CURVE('E1458',#515,#1711,#2672,.T.);
#2674=ORIENTED_EDGE('',*,*,#2673,.F.);
#2675=ORIENTED_EDGE('',*,*,#516,.F.);
#2676=ORIENTED_EDGE('',*,*,#2656,.T.);
#2677=EDGE_LOOP('',(#2668,#2674,#2675,#2676));
#2678=FACE_BOUND('',#2677,.T.);
#2679=ADVANCED_FACE('F1929',(#2678),#2667,.F.);
#2680=CARTESIAN_POINT('',(85.,55.5,15.));
#2681=DIRECTION('',(0.,0.,-1.));
#2682=DIRECTION('',(-1.,0.,0.));
#2683=AXIS2_PLACEMENT_3D('',#2680,#2681,#2682);
#2684=CYLINDRICAL_SURFACE('',#2683,3.);
#2685=ORIENTED_EDGE('',*,*,#1712,.T.);
#2686=DIRECTION('',(0.,0.,-1.));
#2687=VECTOR('',#2686,1.);
#2688=CARTESIAN_POINT('',(85.,58.5,15.));
#2689=LINE('',#2688,#2687);
#2690=EDGE_CURVE('E1455',#524,#1702,#2689,.T.);
#2691=ORIENTED_EDGE('',*,*,#2690,.F.);
#2692=ORIENTED_EDGE('',*,*,#525,.F.);
#2693=ORIENTED_EDGE('',*,*,#2673,.T.);
#2694=EDGE_LOOP('',(#2685,#2691,#2692,#2693));
#2695=FACE_BOUND('',#2694,.T.);
#2696=ADVANCED_FACE('F1925',(#2695),#2684,.F.);
#2697=CARTESIAN_POINT('',(85.,61.6,15.));
#2698=DIRECTION('',(-1.,0.,0.));
#2699=DIRECTION('',(0.,0.,1.));
#2700=AXIS2_PLACEMENT_3D('',#2697,#2698,#2699);
#2701=PLANE('',#2700);
#2702=ORIENTED_EDGE('',*,*,#1703,.T.);
#2703=DIRECTION('',(0.,0.,-1.));
#2704=VECTOR('',#2703,1.);
#2705=CARTESIAN_POINT('',(85.,61.6,15.));
#2706=LINE('',#2705,#2704);
#2707=EDGE_CURVE('E1452',#532,#1694,#2706,.T.);
#2708=ORIENTED_EDGE('',*,*,#2707,.F.);
#2709=ORIENTED_EDGE('',*,*,#533,.F.);
#2710=ORIENTED_EDGE('',*,*,#2690,.T.);
#2711=EDGE_LOOP('',(#2702,#2708,#2709,#2710));
#2712=FACE_BOUND('',#2711,.T.);
#2713=ADVANCED_FACE('F1921',(#2712),#2701,.F.);
#2714=CARTESIAN_POINT('',(85.,64.6,15.));
#2715=DIRECTION('',(0.,0.,-1.));
#2716=DIRECTION('',(-1.,0.,0.));
#2717=AXIS2_PLACEMENT_3D('',#2714,#2715,#2716);
#2718=CYLINDRICAL_SURFACE('',#2717,3.);
#2719=ORIENTED_EDGE('',*,*,#1695,.T.);
#2720=DIRECTION('',(0.,0.,-1.));
#2721=VECTOR('',#2720,1.);
#2722=CARTESIAN_POINT('',(85.,67.6,15.));
#2723=LINE('',#2722,#2721);
#2724=EDGE_CURVE('E1449',#541,#1685,#2723,.T.);
#2725=ORIENTED_EDGE('',*,*,#2724,.F.);
#2726=ORIENTED_EDGE('',*,*,#542,.F.);
#2727=ORIENTED_EDGE('',*,*,#2707,.T.);
#2728=EDGE_LOOP('',(#2719,#2725,#2726,#2727));
#2729=FACE_BOUND('',#2728,.T.);
#2730=ADVANCED_FACE('F1917',(#2729),#2718,.F.);
#2731=CARTESIAN_POINT('',(100.,67.6,15.));
#2732=DIRECTION('',(0.,1.,0.));
#2733=DIRECTION('',(0.,0.,1.));
#2734=AXIS2_PLACEMENT_3D('',#2731,#2732,#2733);
#2735=PLANE('',#2734);
#2736=ORIENTED_EDGE('',*,*,#1686,.T.);
#2737=DIRECTION('',(0.,0.,-1.));
#2738=VECTOR('',#2737,1.);
#2739=CARTESIAN_POINT('',(100.,67.6,15.));
#2740=LINE('',#2739,#2738);
#2741=EDGE_CURVE('E1446',#549,#1677,#2740,.T.);
#2742=ORIENTED_EDGE('',*,*,#2741,.F.);
#2743=ORIENTED_EDGE('',*,*,#550,.F.);
#2744=ORIENTED_EDGE('',*,*,#2724,.T.);
#2745=EDGE_LOOP('',(#2736,#2742,#2743,#2744));
#2746=FACE_BOUND('',#2745,.T.);
#2747=ADVANCED_FACE('F1913',(#2746),#2735,.F.);
#2748=CARTESIAN_POINT('',(100.,82.6,15.));
#2749=DIRECTION('',(-1.,0.,0.));
#2750=DIRECTION('',(0.,0.,1.));
#2751=AXIS2_PLACEMENT_3D('',#2748,#2749,#2750);
#2752=PLANE('',#2751);
#2753=ORIENTED_EDGE('',*,*,#1678,.T.);
#2754=DIRECTION('',(0.,0.,-1.));
#2755=VECTOR('',#2754,1.);
#2756=CARTESIAN_POINT('',(100.,82.6,15.));
#2757=LINE('',#2756,#2755);
#2758=EDGE_CURVE('E1443',#557,#1669,#2757,.T.);
#2759=ORIENTED_EDGE('',*,*,#2758,.F.);
#2760=ORIENTED_EDGE('',*,*,#558,.F.);
#2761=ORIENTED_EDGE('',*,*,#2741,.T.);
#2762=EDGE_LOOP('',(#2753,#2759,#2760,#2761));
#2763=FACE_BOUND('',#2762,.T.);
#2764=ADVANCED_FACE('F1909',(#2763),#2752,.F.);
#2765=CARTESIAN_POINT('',(85.,82.6,15.));
#2766=DIRECTION('',(0.,-1.,0.));
#2767=DIRECTION('',(0.,0.,-1.));
#2768=AXIS2_PLACEMENT_3D('',#2765,#2766,#2767);
#2769=PLANE('',#2768);
#2770=ORIENTED_EDGE('',*,*,#1670,.T.);
#2771=DIRECTION('',(0.,0.,-1.));
#2772=VECTOR('',#2771,1.);
#2773=CARTESIAN_POINT('',(85.,82.6,15.));
#2774=LINE('',#2773,#2772);
#2775=EDGE_CURVE('E1440',#565,#1661,#2774,.T.);
#2776=ORIENTED_EDGE('',*,*,#2775,.F.);
#2777=ORIENTED_EDGE('',*,*,#566,.F.);
#2778=ORIENTED_EDGE('',*,*,#2758,.T.);
#2779=EDGE_LOOP('',(#2770,#2776,#2777,#2778));
#2780=FACE_BOUND('',#2779,.T.);
#2781=ADVANCED_FACE('F1905',(#2780),#2769,.F.);
#2782=CARTESIAN_POINT('',(85.,86.35,15.));
#2783=DIRECTION('',(0.,0.,-1.));
#2784=DIRECTION('',(-1.,0.,0.));
#2785=AXIS2_PLACEMENT_3D('',#2782,#2783,#2784);
#2786=CYLINDRICAL_SURFACE('',#2785,3.75);
#2787=ORIENTED_EDGE('',*,*,#1662,.T.);
#2788=DIRECTION('',(0.,0.,-1.));
#2789=VECTOR('',#2788,1.);
#2790=CARTESIAN_POINT('',(85.,90.1,15.));
#2791=LINE('',#2790,#2789);
#2792=EDGE_CURVE('E1437',#574,#1652,#2791,.T.);
#2793=ORIENTED_EDGE('',*,*,#2792,.F.);
#2794=ORIENTED_EDGE('',*,*,#575,.F.);
#2795=ORIENTED_EDGE('',*,*,#2775,.T.);
#2796=EDGE_LOOP('',(#2787,#2793,#2794,#2795));
#2797=FACE_BOUND('',#2796,.T.);
#2798=ADVANCED_FACE('F1901',(#2797),#2786,.F.);
#2799=CARTESIAN_POINT('',(85.,90.1,15.));
#2800=DIRECTION('',(0.,1.,0.));
#2801=DIRECTION('',(0.,0.,1.));
#2802=AXIS2_PLACEMENT_3D('',#2799,#2800,#2801);
#2803=PLANE('',#2802);
#2804=ORIENTED_EDGE('',*,*,#1653,.T.);
#2805=DIRECTION('',(0.,0.,-1.));
#2806=VECTOR('',#2805,1.);
#2807=CARTESIAN_POINT('',(100.,90.1,15.));
#2808=LINE('',#2807,#2806);
#2809=EDGE_CURVE('E1434',#582,#1644,#2808,.T.);
#2810=ORIENTED_EDGE('',*,*,#2809,.F.);
#2811=ORIENTED_EDGE('',*,*,#583,.F.);
#2812=ORIENTED_EDGE('',*,*,#2792,.T.);
#2813=EDGE_LOOP('',(#2804,#2810,#2811,#2812));
#2814=FACE_BOUND('',#2813,.T.);
#2815=ADVANCED_FACE('F1897',(#2814),#2803,.F.);
#2816=CARTESIAN_POINT('',(100.,90.1,15.));
#2817=DIRECTION('',(-1.,0.,0.));
#2818=DIRECTION('',(0.,0.,1.));
#2819=AXIS2_PLACEMENT_3D('',#2816,#2817,#2818);
#2820=PLANE('',#2819);
#2821=ORIENTED_EDGE('',*,*,#1645,.T.);
#2822=DIRECTION('',(0.,0.,-1.));
#2823=VECTOR('',#2822,1.);
#2824=CARTESIAN_POINT('',(100.,365.4,15.));
#2825=LINE('',#2824,#2823);
#2826=EDGE_CURVE('E1431',#590,#1636,#2825,.T.);
#2827=ORIENTED_EDGE('',*,*,#2826,.F.);
#2828=ORIENTED_EDGE('',*,*,#591,.F.);
#2829=ORIENTED_EDGE('',*,*,#2809,.T.);
#2830=EDGE_LOOP('',(#2821,#2827,#2828,#2829));
#2831=FACE_BOUND('',#2830,.T.);
#2832=ADVANCED_FACE('F1893',(#2831),#2820,.F.);
#2833=CARTESIAN_POINT('',(91.1999999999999,365.4,15.));
#2834=DIRECTION('',(0.,-1.,0.));
#2835=DIRECTION('',(0.,0.,-1.));
#2836=AXIS2_PLACEMENT_3D('',#2833,#2834,#2835);
#2837=PLANE('',#2836);
#2838=ORIENTED_EDGE('',*,*,#1637,.T.);
#2839=DIRECTION('',(0.,0.,-1.));
#2840=VECTOR('',#2839,1.);
#2841=CARTESIAN_POINT('',(91.1999999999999,365.4,15.));
#2842=LINE('',#2841,#2840);
#2843=EDGE_CURVE('E1428',#598,#1628,#2842,.T.);
#2844=ORIENTED_EDGE('',*,*,#2843,.F.);
#2845=ORIENTED_EDGE('',*,*,#599,.F.);
#2846=ORIENTED_EDGE('',*,*,#2826,.T.);
#2847=EDGE_LOOP('',(#2838,#2844,#2845,#2846));
#2848=FACE_BOUND('',#2847,.T.);
#2849=ADVANCED_FACE('F1889',(#2848),#2837,.F.);
#2850=CARTESIAN_POINT('',(88.1999999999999,365.335267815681,15.));
#2851=DIRECTION('',(0.,0.,-1.));
#2852=DIRECTION('',(-1.,0.,0.));
#2853=AXIS2_PLACEMENT_3D('',#2850,#2851,#2852);
#2854=CYLINDRICAL_SURFACE('',#2853,3.00069829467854);
#2855=ORIENTED_EDGE('',*,*,#1629,.T.);
#2856=DIRECTION('',(0.,0.,-1.));
#2857=VECTOR('',#2856,1.);
#2858=CARTESIAN_POINT('',(85.2,365.270535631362,15.));
#2859=LINE('',#2858,#2857);
#2860=EDGE_CURVE('E1425',#607,#1619,#2859,.T.);
#2861=ORIENTED_EDGE('',*,*,#2860,.F.);
#2862=ORIENTED_EDGE('',*,*,#608,.F.);
#2863=ORIENTED_EDGE('',*,*,#2843,.T.);
#2864=EDGE_LOOP('',(#2855,#2861,#2862,#2863));
#2865=FACE_BOUND('',#2864,.T.);
#2866=ADVANCED_FACE('F1885',(#2865),#2854,.F.);
#2867=CARTESIAN_POINT('',(85.1999999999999,380.270535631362,15.));
#2868=DIRECTION('',(-1.,0.,0.));
#2869=DIRECTION('',(0.,-1.,0.));
#2870=AXIS2_PLACEMENT_3D('',#2867,#2868,#2869);
#2871=PLANE('',#2870);
#2872=ORIENTED_EDGE('',*,*,#1620,.T.);
#2873=DIRECTION('',(0.,0.,-1.));
#2874=VECTOR('',#2873,1.);
#2875=CARTESIAN_POINT('',(85.1999999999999,380.270535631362,15.));
#2876=LINE('',#2875,#2874);
#2877=EDGE_CURVE('E1422',#615,#1611,#2876,.T.);
#2878=ORIENTED_EDGE('',*,*,#2877,.F.);
#2879=ORIENTED_EDGE('',*,*,#616,.F.);
#2880=ORIENTED_EDGE('',*,*,#2860,.T.);
#2881=EDGE_LOOP('',(#2872,#2878,#2879,#2880));
#2882=FACE_BOUND('',#2881,.T.);
#2883=ADVANCED_FACE('F1881',(#2882),#2871,.F.);
#2884=CARTESIAN_POINT('',(70.1999999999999,380.270535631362,15.));
#2885=DIRECTION('',(0.,-1.,0.));
#2886=DIRECTION('',(0.,0.,-1.));
#2887=AXIS2_PLACEMENT_3D('',#2884,#2885,#2886);
#2888=PLANE('',#2887);
#2889=ORIENTED_EDGE('',*,*,#1612,.T.);
#2890=DIRECTION('',(0.,0.,-1.));
#2891=VECTOR('',#2890,1.);
#2892=CARTESIAN_POINT('',(70.1999999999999,380.270535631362,15.));
#2893=LINE('',#2892,#2891);
#2894=EDGE_CURVE('E1419',#623,#1603,#2893,.T.);
#2895=ORIENTED_EDGE('',*,*,#2894,.F.);
#2896=ORIENTED_EDGE('',*,*,#624,.F.);
#2897=ORIENTED_EDGE('',*,*,#2877,.T.);
#2898=EDGE_LOOP('',(#2889,#2895,#2896,#2897));
#2899=FACE_BOUND('',#2898,.T.);
#2900=ADVANCED_FACE('F1877',(#2899),#2888,.F.);
#2901=CARTESIAN_POINT('',(70.1999999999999,365.270535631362,15.));
#2902=DIRECTION('',(1.,0.,0.));
#2903=DIRECTION('',(0.,1.,0.));
#2904=AXIS2_PLACEMENT_3D('',#2901,#2902,#2903);
#2905=PLANE('',#2904);
#2906=ORIENTED_EDGE('',*,*,#1604,.T.);
#2907=DIRECTION('',(0.,0.,-1.));
#2908=VECTOR('',#2907,1.);
#2909=CARTESIAN_POINT('',(70.1999999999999,365.270535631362,15.));
#2910=LINE('',#2909,#2908);
#2911=EDGE_CURVE('E1416',#631,#1595,#2910,.T.);
#2912=ORIENTED_EDGE('',*,*,#2911,.F.);
#2913=ORIENTED_EDGE('',*,*,#632,.F.);
#2914=ORIENTED_EDGE('',*,*,#2894,.T.);
#2915=EDGE_LOOP('',(#2906,#2912,#2913,#2914));
#2916=FACE_BOUND('',#2915,.T.);
#2917=ADVANCED_FACE('F1873',(#2916),#2905,.F.);
#2918=CARTESIAN_POINT('',(67.1999999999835,365.270535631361,15.));
#2919=DIRECTION('',(0.,0.,-1.));
#2920=DIRECTION('',(-1.,0.,0.));
#2921=AXIS2_PLACEMENT_3D('',#2918,#2919,#2920);
#2922=CYLINDRICAL_SURFACE('',#2921,3.00000000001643);
#2923=ORIENTED_EDGE('',*,*,#1596,.T.);
#2924=DIRECTION('',(0.,0.,-1.));
#2925=VECTOR('',#2924,1.);
#2926=CARTESIAN_POINT('',(64.2000000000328,365.270515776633,15.));
#2927=LINE('',#2926,#2925);
#2928=EDGE_CURVE('E1413',#640,#1586,#2927,.T.);
#2929=ORIENTED_EDGE('',*,*,#2928,.F.);
#2930=ORIENTED_EDGE('',*,*,#641,.F.);
#2931=ORIENTED_EDGE('',*,*,#2911,.T.);
#2932=EDGE_LOOP('',(#2923,#2929,#2930,#2931));
#2933=FACE_BOUND('',#2932,.T.);
#2934=ADVANCED_FACE('F1869',(#2933),#2922,.F.);
#2935=CARTESIAN_POINT('',(61.0999999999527,365.270515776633,15.));
#2936=DIRECTION('',(0.,-1.,0.));
#2937=DIRECTION('',(0.,0.,-1.));
#2938=AXIS2_PLACEMENT_3D('',#2935,#2936,#2937);
#2939=PLANE('',#2938);
#2940=ORIENTED_EDGE('',*,*,#1587,.T.);
#2941=DIRECTION('',(0.,0.,-1.));
#2942=VECTOR('',#2941,1.);
#2943=CARTESIAN_POINT('',(61.0999999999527,365.270515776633,15.));
#2944=LINE('',#2943,#2942);
#2945=EDGE_CURVE('E1410',#648,#1578,#2944,.T.);
#2946=ORIENTED_EDGE('',*,*,#2945,.F.);
#2947=ORIENTED_EDGE('',*,*,#649,.F.);
#2948=ORIENTED_EDGE('',*,*,#2928,.T.);
#2949=EDGE_LOOP('',(#2940,#2946,#2947,#2948));
#2950=FACE_BOUND('',#2949,.T.);
#2951=ADVANCED_FACE('F1865',(#2950),#2939,.F.);
#2952=CARTESIAN_POINT('',(58.1000000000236,365.270539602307,15.));
#2953=DIRECTION('',(0.,0.,-1.));
#2954=DIRECTION('',(-1.,0.,0.));
#2955=AXIS2_PLACEMENT_3D('',#2952,#2953,#2954);
#2956=CYLINDRICAL_SURFACE('',#2955,3.00000000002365);
#2957=ORIENTED_EDGE('',*,*,#1579,.T.);
#2958=DIRECTION('',(0.,0.,-1.));
#2959=VECTOR('',#2958,1.);
#2960=CARTESIAN_POINT('',(55.1,365.270539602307,15.));
#2961=LINE('',#2960,#2959);
#2962=EDGE_CURVE('E1407',#657,#1569,#2961,.T.);
#2963=ORIENTED_EDGE('',*,*,#2962,.F.);
#2964=ORIENTED_EDGE('',*,*,#658,.F.);
#2965=ORIENTED_EDGE('',*,*,#2945,.T.);
#2966=EDGE_LOOP('',(#2957,#2963,#2964,#2965));
#2967=FACE_BOUND('',#2966,.T.);
#2968=ADVANCED_FACE('F1861',(#2967),#2956,.F.);
#2969=CARTESIAN_POINT('',(55.1,380.270539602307,15.));
#2970=DIRECTION('',(-1.,0.,0.));
#2971=DIRECTION('',(0.,-1.,0.));
#2972=AXIS2_PLACEMENT_3D('',#2969,#2970,#2971);
#2973=PLANE('',#2972);
#2974=ORIENTED_EDGE('',*,*,#1570,.T.);
#2975=DIRECTION('',(0.,0.,-1.));
#2976=VECTOR('',#2975,1.);
#2977=CARTESIAN_POINT('',(55.1,380.270539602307,15.));
#2978=LINE('',#2977,#2976);
#2979=EDGE_CURVE('E1404',#665,#1561,#2978,.T.);
#2980=ORIENTED_EDGE('',*,*,#2979,.F.);
#2981=ORIENTED_EDGE('',*,*,#666,.F.);
#2982=ORIENTED_EDGE('',*,*,#2962,.T.);
#2983=EDGE_LOOP('',(#2974,#2980,#2981,#2982));
#2984=FACE_BOUND('',#2983,.T.);
#2985=ADVANCED_FACE('F1857',(#2984),#2973,.F.);
#2986=CARTESIAN_POINT('',(40.1,380.270539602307,15.));
#2987=DIRECTION('',(0.,-1.,0.));
#2988=DIRECTION('',(0.,0.,-1.));
#2989=AXIS2_PLACEMENT_3D('',#2986,#2987,#2988);
#2990=PLANE('',#2989);
#2991=ORIENTED_EDGE('',*,*,#1562,.T.);
#2992=DIRECTION('',(0.,0.,-1.));
#2993=VECTOR('',#2992,1.);
#2994=CARTESIAN_POINT('',(40.1,380.270539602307,15.));
#2995=LINE('',#2994,#2993);
#2996=EDGE_CURVE('E1401',#673,#1553,#2995,.T.);
#2997=ORIENTED_EDGE('',*,*,#2996,.F.);
#2998=ORIENTED_EDGE('',*,*,#674,.F.);
#2999=ORIENTED_EDGE('',*,*,#2979,.T.);
#3000=EDGE_LOOP('',(#2991,#2997,#2998,#2999));
#3001=FACE_BOUND('',#3000,.T.);
#3002=ADVANCED_FACE('F1853',(#3001),#2990,.F.);
#3003=CARTESIAN_POINT('',(40.1,365.270539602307,15.));
#3004=DIRECTION('',(1.,0.,0.));
#3005=DIRECTION('',(0.,1.,0.));
#3006=AXIS2_PLACEMENT_3D('',#3003,#3004,#3005);
#3007=PLANE('',#3006);
#3008=ORIENTED_EDGE('',*,*,#1554,.T.);
#3009=DIRECTION('',(0.,0.,-1.));
#3010=VECTOR('',#3009,1.);
#3011=CARTESIAN_POINT('',(40.1,365.270539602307,15.));
#3012=LINE('',#3011,#3010);
#3013=EDGE_CURVE('E1398',#681,#1545,#3012,.T.);
#3014=ORIENTED_EDGE('',*,*,#3013,.F.);
#3015=ORIENTED_EDGE('',*,*,#682,.F.);
#3016=ORIENTED_EDGE('',*,*,#2996,.T.);
#3017=EDGE_LOOP('',(#3008,#3014,#3015,#3016));
#3018=FACE_BOUND('',#3017,.T.);
#3019=ADVANCED_FACE('F1849',(#3018),#3007,.F.);
#3020=CARTESIAN_POINT('',(37.0999999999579,365.270539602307,15.));
#3021=DIRECTION('',(0.,0.,-1.));
#3022=DIRECTION('',(-1.,0.,0.));
#3023=AXIS2_PLACEMENT_3D('',#3020,#3021,#3022);
#3024=CYLINDRICAL_SURFACE('',#3023,3.00000000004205);
#3025=ORIENTED_EDGE('',*,*,#1546,.T.);
#3026=DIRECTION('',(0.,0.,-1.));
#3027=VECTOR('',#3026,1.);
#3028=CARTESIAN_POINT('',(34.1000000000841,365.270507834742,15.));
#3029=LINE('',#3028,#3027);
#3030=EDGE_CURVE('E1395',#690,#1536,#3029,.T.);
#3031=ORIENTED_EDGE('',*,*,#3030,.F.);
#3032=ORIENTED_EDGE('',*,*,#691,.F.);
#3033=ORIENTED_EDGE('',*,*,#3013,.T.);
#3034=EDGE_LOOP('',(#3025,#3031,#3032,#3033));
#3035=FACE_BOUND('',#3034,.T.);
#3036=ADVANCED_FACE('F1845',(#3035),#3024,.F.);
#3037=CARTESIAN_POINT('',(30.9999999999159,365.270507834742,15.));
#3038=DIRECTION('',(0.,-1.,0.));
#3039=DIRECTION('',(0.,0.,-1.));
#3040=AXIS2_PLACEMENT_3D('',#3037,#3038,#3039);
#3041=PLANE('',#3040);
#3042=ORIENTED_EDGE('',*,*,#1537,.T.);
#3043=DIRECTION('',(0.,0.,-1.));
#3044=VECTOR('',#3043,1.);
#3045=CARTESIAN_POINT('',(30.9999999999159,365.270507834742,15.));
#3046=LINE('',#3045,#3044);
#3047=EDGE_CURVE('E1392',#698,#1528,#3046,.T.);
#3048=ORIENTED_EDGE('',*,*,#3047,.F.);
#3049=ORIENTED_EDGE('',*,*,#699,.F.);
#3050=ORIENTED_EDGE('',*,*,#3030,.T.);
#3051=EDGE_LOOP('',(#3042,#3048,#3049,#3050));
#3052=FACE_BOUND('',#3051,.T.);
#3053=ADVANCED_FACE('F1841',(#3052),#3041,.F.);
#3054=CARTESIAN_POINT('',(28.0000000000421,365.270539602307,15.));
#3055=DIRECTION('',(0.,0.,-1.));
#3056=DIRECTION('',(-1.,0.,0.));
#3057=AXIS2_PLACEMENT_3D('',#3054,#3055,#3056);
#3058=CYLINDRICAL_SURFACE('',#3057,3.00000000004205);
#3059=ORIENTED_EDGE('',*,*,#1529,.T.);
#3060=DIRECTION('',(0.,0.,-1.));
#3061=VECTOR('',#3060,1.);
#3062=CARTESIAN_POINT('',(25.,365.270539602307,15.));
#3063=LINE('',#3062,#3061);
#3064=EDGE_CURVE('E1389',#707,#1519,#3063,.T.);
#3065=ORIENTED_EDGE('',*,*,#3064,.F.);
#3066=ORIENTED_EDGE('',*,*,#708,.F.);
#3067=ORIENTED_EDGE('',*,*,#3047,.T.);
#3068=EDGE_LOOP('',(#3059,#3065,#3066,#3067));
#3069=FACE_BOUND('',#3068,.T.);
#3070=ADVANCED_FACE('F1837',(#3069),#3058,.F.);
#3071=CARTESIAN_POINT('',(25.,365.270539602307,15.));
#3072=DIRECTION('',(-1.,0.,0.));
#3073=DIRECTION('',(0.,0.,1.));
#3074=AXIS2_PLACEMENT_3D('',#3071,#3072,#3073);
#3075=PLANE('',#3074);
#3076=ORIENTED_EDGE('',*,*,#1520,.T.);
#3077=DIRECTION('',(0.,0.,-1.));
#3078=VECTOR('',#3077,1.);
#3079=CARTESIAN_POINT('',(25.,380.270539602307,15.));
#3080=LINE('',#3079,#3078);
#3081=EDGE_CURVE('E1386',#715,#1511,#3080,.T.);
#3082=ORIENTED_EDGE('',*,*,#3081,.F.);
#3083=ORIENTED_EDGE('',*,*,#716,.F.);
#3084=ORIENTED_EDGE('',*,*,#3064,.T.);
#3085=EDGE_LOOP('',(#3076,#3082,#3083,#3084));
#3086=FACE_BOUND('',#3085,.T.);
#3087=ADVANCED_FACE('F1833',(#3086),#3075,.F.);
#3088=CARTESIAN_POINT('',(0.,380.270539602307,15.));
#3089=DIRECTION('',(0.,-1.,0.));
#3090=DIRECTION('',(0.,0.,-1.));
#3091=AXIS2_PLACEMENT_3D('',#3088,#3089,#3090);
#3092=PLANE('',#3091);
#3093=ORIENTED_EDGE('',*,*,#1512,.T.);
#3094=DIRECTION('',(0.,0.,-1.));
#3095=VECTOR('',#3094,1.);
#3096=CARTESIAN_POINT('',(0.,380.270539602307,15.));
#3097=LINE('',#3096,#3095);
#3098=EDGE_CURVE('E1383',#723,#1503,#3097,.T.);
#3099=ORIENTED_EDGE('',*,*,#3098,.F.);
#3100=ORIENTED_EDGE('',*,*,#724,.F.);
#3101=ORIENTED_EDGE('',*,*,#3081,.T.);
#3102=EDGE_LOOP('',(#3093,#3099,#3100,#3101));
#3103=FACE_BOUND('',#3102,.T.);
#3104=ADVANCED_FACE('F1829',(#3103),#3092,.F.);
#3105=CARTESIAN_POINT('',(0.,365.270539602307,15.));
#3106=DIRECTION('',(1.,0.,0.));
#3107=DIRECTION('',(0.,0.,-1.));
#3108=AXIS2_PLACEMENT_3D('',#3105,#3106,#3107);
#3109=PLANE('',#3108);
#3110=ORIENTED_EDGE('',*,*,#1504,.T.);
#3111=DIRECTION('',(0.,0.,-1.));
#3112=VECTOR('',#3111,1.);
#3113=CARTESIAN_POINT('',(0.,365.270539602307,15.));
#3114=LINE('',#3113,#3112);
#3115=EDGE_CURVE('E1380',#731,#1495,#3114,.T.);
#3116=ORIENTED_EDGE('',*,*,#3115,.F.);
#3117=ORIENTED_EDGE('',*,*,#732,.F.);
#3118=ORIENTED_EDGE('',*,*,#3098,.T.);
#3119=EDGE_LOOP('',(#3110,#3116,#3117,#3118));
#3120=FACE_BOUND('',#3119,.T.);
#3121=ADVANCED_FACE('F1825',(#3120),#3109,.F.);
#3122=CARTESIAN_POINT('',(0.,365.270539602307,15.));
#3123=DIRECTION('',(0.,1.,0.));
#3124=DIRECTION('',(-1.,0.,0.));
#3125=AXIS2_PLACEMENT_3D('',#3122,#3123,#3124);
#3126=PLANE('',#3125);
#3127=ORIENTED_EDGE('',*,*,#1496,.T.);
#3128=DIRECTION('',(0.,0.,-1.));
#3129=VECTOR('',#3128,1.);
#3130=CARTESIAN_POINT('',(9.,365.270539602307,15.));
#3131=LINE('',#3130,#3129);
#3132=EDGE_CURVE('E1377',#739,#1487,#3131,.T.);
#3133=ORIENTED_EDGE('',*,*,#3132,.F.);
#3134=ORIENTED_EDGE('',*,*,#740,.F.);
#3135=ORIENTED_EDGE('',*,*,#3115,.T.);
#3136=EDGE_LOOP('',(#3127,#3133,#3134,#3135));
#3137=FACE_BOUND('',#3136,.T.);
#3138=ADVANCED_FACE('F1821',(#3137),#3126,.F.);
#3139=CARTESIAN_POINT('',(12.,365.270539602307,15.));
#3140=DIRECTION('',(0.,0.,-1.));
#3141=DIRECTION('',(-1.,0.,0.));
#3142=AXIS2_PLACEMENT_3D('',#3139,#3140,#3141);
#3143=CYLINDRICAL_SURFACE('',#3142,3.);
#3144=ORIENTED_EDGE('',*,*,#1488,.T.);
#3145=DIRECTION('',(0.,0.,-1.));
#3146=VECTOR('',#3145,1.);
#3147=CARTESIAN_POINT('',(15.,365.270539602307,15.));
#3148=LINE('',#3147,#3146);
#3149=EDGE_CURVE('E1374',#748,#1478,#3148,.T.);
#3150=ORIENTED_EDGE('',*,*,#3149,.F.);
#3151=ORIENTED_EDGE('',*,*,#749,.F.);
#3152=ORIENTED_EDGE('',*,*,#3132,.T.);
#3153=EDGE_LOOP('',(#3144,#3150,#3151,#3152));
#3154=FACE_BOUND('',#3153,.T.);
#3155=ADVANCED_FACE('F1817',(#3154),#3143,.F.);
#3156=CARTESIAN_POINT('',(15.,356.170539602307,15.));
#3157=DIRECTION('',(1.,0.,0.));
#3158=DIRECTION('',(0.,0.,-1.));
#3159=AXIS2_PLACEMENT_3D('',#3156,#3157,#3158);
#3160=PLANE('',#3159);
#3161=ORIENTED_EDGE('',*,*,#1479,.T.);
#3162=DIRECTION('',(0.,0.,-1.));
#3163=VECTOR('',#3162,1.);
#3164=CARTESIAN_POINT('',(15.,356.170539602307,15.));
#3165=LINE('',#3164,#3163);
#3166=EDGE_CURVE('E1371',#756,#1470,#3165,.T.);
#3167=ORIENTED_EDGE('',*,*,#3166,.F.);
#3168=ORIENTED_EDGE('',*,*,#757,.F.);
#3169=ORIENTED_EDGE('',*,*,#3149,.T.);
#3170=EDGE_LOOP('',(#3161,#3167,#3168,#3169));
#3171=FACE_BOUND('',#3170,.T.);
#3172=ADVANCED_FACE('F1813',(#3171),#3160,.F.);
#3173=CARTESIAN_POINT('',(15.,353.170539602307,15.));
#3174=DIRECTION('',(0.,0.,-1.));
#3175=DIRECTION('',(-1.,0.,0.));
#3176=AXIS2_PLACEMENT_3D('',#3173,#3174,#3175);
#3177=CYLINDRICAL_SURFACE('',#3176,3.);
#3178=ORIENTED_EDGE('',*,*,#1471,.T.);
#3179=DIRECTION('',(0.,0.,-1.));
#3180=VECTOR('',#3179,1.);
#3181=CARTESIAN_POINT('',(15.,350.170539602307,15.));
#3182=LINE('',#3181,#3180);
#3183=EDGE_CURVE('E1368',#765,#1461,#3182,.T.);
#3184=ORIENTED_EDGE('',*,*,#3183,.F.);
#3185=ORIENTED_EDGE('',*,*,#766,.F.);
#3186=ORIENTED_EDGE('',*,*,#3166,.T.);
#3187=EDGE_LOOP('',(#3178,#3184,#3185,#3186));
#3188=FACE_BOUND('',#3187,.T.);
#3189=ADVANCED_FACE('F1809',(#3188),#3177,.F.);
#3190=CARTESIAN_POINT('',(15.,350.170539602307,15.));
#3191=DIRECTION('',(0.,-1.,0.));
#3192=DIRECTION('',(0.,0.,-1.));
#3193=AXIS2_PLACEMENT_3D('',#3190,#3191,#3192);
#3194=PLANE('',#3193);
#3195=ORIENTED_EDGE('',*,*,#1462,.T.);
#3196=DIRECTION('',(0.,0.,-1.));
#3197=VECTOR('',#3196,1.);
#3198=CARTESIAN_POINT('',(0.,350.170539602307,15.));
#3199=LINE('',#3198,#3197);
#3200=EDGE_CURVE('E1365',#773,#1453,#3199,.T.);
#3201=ORIENTED_EDGE('',*,*,#3200,.F.);
#3202=ORIENTED_EDGE('',*,*,#774,.F.);
#3203=ORIENTED_EDGE('',*,*,#3183,.T.);
#3204=EDGE_LOOP('',(#3195,#3201,#3202,#3203));
#3205=FACE_BOUND('',#3204,.T.);
#3206=ADVANCED_FACE('F1805',(#3205),#3194,.F.);
#3207=CARTESIAN_POINT('',(0.,335.170539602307,15.));
#3208=DIRECTION('',(1.,0.,0.));
#3209=DIRECTION('',(0.,0.,-1.));
#3210=AXIS2_PLACEMENT_3D('',#3207,#3208,#3209);
#3211=PLANE('',#3210);
#3212=ORIENTED_EDGE('',*,*,#1454,.T.);
#3213=DIRECTION('',(0.,0.,-1.));
#3214=VECTOR('',#3213,1.);
#3215=CARTESIAN_POINT('',(0.,335.170539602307,15.));
#3216=LINE('',#3215,#3214);
#3217=EDGE_CURVE('E1362',#781,#1445,#3216,.T.);
#3218=ORIENTED_EDGE('',*,*,#3217,.F.);
#3219=ORIENTED_EDGE('',*,*,#782,.F.);
#3220=ORIENTED_EDGE('',*,*,#3200,.T.);
#3221=EDGE_LOOP('',(#3212,#3218,#3219,#3220));
#3222=FACE_BOUND('',#3221,.T.);
#3223=ADVANCED_FACE('F1801',(#3222),#3211,.F.);
#3224=CARTESIAN_POINT('',(0.,335.170539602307,15.));
#3225=DIRECTION('',(0.,1.,0.));
#3226=DIRECTION('',(0.,0.,1.));
#3227=AXIS2_PLACEMENT_3D('',#3224,#3225,#3226);
#3228=PLANE('',#3227);
#3229=ORIENTED_EDGE('',*,*,#1446,.T.);
#3230=DIRECTION('',(0.,0.,-1.));
#3231=VECTOR('',#3230,1.);
#3232=CARTESIAN_POINT('',(15.,335.170539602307,15.));
#3233=LINE('',#3232,#3231);
#3234=EDGE_CURVE('E1359',#789,#1437,#3233,.T.);
#3235=ORIENTED_EDGE('',*,*,#3234,.F.);
#3236=ORIENTED_EDGE('',*,*,#790,.F.);
#3237=ORIENTED_EDGE('',*,*,#3217,.T.);
#3238=EDGE_LOOP('',(#3229,#3235,#3236,#3237));
#3239=FACE_BOUND('',#3238,.T.);
#3240=ADVANCED_FACE('F1797',(#3239),#3228,.F.);
#3241=CARTESIAN_POINT('',(15.,332.170539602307,15.));
#3242=DIRECTION('',(0.,0.,-1.));
#3243=DIRECTION('',(-1.,0.,0.));
#3244=AXIS2_PLACEMENT_3D('',#3241,#3242,#3243);
#3245=CYLINDRICAL_SURFACE('',#3244,3.);
#3246=ORIENTED_EDGE('',*,*,#1438,.T.);
#3247=DIRECTION('',(0.,0.,-1.));
#3248=VECTOR('',#3247,1.);
#3249=CARTESIAN_POINT('',(15.,329.170539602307,15.));
#3250=LINE('',#3249,#3248);
#3251=EDGE_CURVE('E1356',#798,#1428,#3250,.T.);
#3252=ORIENTED_EDGE('',*,*,#3251,.F.);
#3253=ORIENTED_EDGE('',*,*,#799,.F.);
#3254=ORIENTED_EDGE('',*,*,#3234,.T.);
#3255=EDGE_LOOP('',(#3246,#3252,#3253,#3254));
#3256=FACE_BOUND('',#3255,.T.);
#3257=ADVANCED_FACE('F1793',(#3256),#3245,.F.);
#3258=CARTESIAN_POINT('',(15.,326.070539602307,15.));
#3259=DIRECTION('',(1.,0.,0.));
#3260=DIRECTION('',(0.,0.,-1.));
#3261=AXIS2_PLACEMENT_3D('',#3258,#3259,#3260);
#3262=PLANE('',#3261);
#3263=ORIENTED_EDGE('',*,*,#1429,.T.);
#3264=DIRECTION('',(0.,0.,-1.));
#3265=VECTOR('',#3264,1.);
#3266=CARTESIAN_POINT('',(15.,326.070539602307,15.));
#3267=LINE('',#3266,#3265);
#3268=EDGE_CURVE('E1353',#806,#1420,#3267,.T.);
#3269=ORIENTED_EDGE('',*,*,#3268,.F.);
#3270=ORIENTED_EDGE('',*,*,#807,.F.);
#3271=ORIENTED_EDGE('',*,*,#3251,.T.);
#3272=EDGE_LOOP('',(#3263,#3269,#3270,#3271));
#3273=FACE_BOUND('',#3272,.T.);
#3274=ADVANCED_FACE('F1789',(#3273),#3262,.F.);
#3275=CARTESIAN_POINT('',(15.,323.070539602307,15.));
#3276=DIRECTION('',(0.,0.,-1.));
#3277=DIRECTION('',(-1.,0.,0.));
#3278=AXIS2_PLACEMENT_3D('',#3275,#3276,#3277);
#3279=CYLINDRICAL_SURFACE('',#3278,3.);
#3280=ORIENTED_EDGE('',*,*,#1421,.T.);
#3281=DIRECTION('',(0.,0.,-1.));
#3282=VECTOR('',#3281,1.);
#3283=CARTESIAN_POINT('',(15.,320.070539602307,15.));
#3284=LINE('',#3283,#3282);
#3285=EDGE_CURVE('E1350',#815,#1411,#3284,.T.);
#3286=ORIENTED_EDGE('',*,*,#3285,.F.);
#3287=ORIENTED_EDGE('',*,*,#816,.F.);
#3288=ORIENTED_EDGE('',*,*,#3268,.T.);
#3289=EDGE_LOOP('',(#3280,#3286,#3287,#3288));
#3290=FACE_BOUND('',#3289,.T.);
#3291=ADVANCED_FACE('F1785',(#3290),#3279,.F.);
#3292=CARTESIAN_POINT('',(15.,320.070539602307,15.));
#3293=DIRECTION('',(0.,-1.,0.));
#3294=DIRECTION('',(0.,0.,-1.));
#3295=AXIS2_PLACEMENT_3D('',#3292,#3293,#3294);
#3296=PLANE('',#3295);
#3297=ORIENTED_EDGE('',*,*,#1412,.T.);
#3298=DIRECTION('',(0.,0.,-1.));
#3299=VECTOR('',#3298,1.);
#3300=CARTESIAN_POINT('',(0.,320.070539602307,15.));
#3301=LINE('',#3300,#3299);
#3302=EDGE_CURVE('E1347',#823,#1403,#3301,.T.);
#3303=ORIENTED_EDGE('',*,*,#3302,.F.);
#3304=ORIENTED_EDGE('',*,*,#824,.F.);
#3305=ORIENTED_EDGE('',*,*,#3285,.T.);
#3306=EDGE_LOOP('',(#3297,#3303,#3304,#3305));
#3307=FACE_BOUND('',#3306,.T.);
#3308=ADVANCED_FACE('F1781',(#3307),#3296,.F.);
#3309=CARTESIAN_POINT('',(0.,305.070539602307,15.));
#3310=DIRECTION('',(1.,0.,0.));
#3311=DIRECTION('',(0.,0.,-1.));
#3312=AXIS2_PLACEMENT_3D('',#3309,#3310,#3311);
#3313=PLANE('',#3312);
#3314=ORIENTED_EDGE('',*,*,#1404,.T.);
#3315=DIRECTION('',(0.,0.,-1.));
#3316=VECTOR('',#3315,1.);
#3317=CARTESIAN_POINT('',(0.,305.070539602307,15.));
#3318=LINE('',#3317,#3316);
#3319=EDGE_CURVE('E1344',#831,#1395,#3318,.T.);
#3320=ORIENTED_EDGE('',*,*,#3319,.F.);
#3321=ORIENTED_EDGE('',*,*,#832,.F.);
#3322=ORIENTED_EDGE('',*,*,#3302,.T.);
#3323=EDGE_LOOP('',(#3314,#3320,#3321,#3322));
#3324=FACE_BOUND('',#3323,.T.);
#3325=ADVANCED_FACE('F1777',(#3324),#3313,.F.);
#3326=CARTESIAN_POINT('',(0.,305.070539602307,15.));
#3327=DIRECTION('',(0.,1.,0.));
#3328=DIRECTION('',(0.,0.,1.));
#3329=AXIS2_PLACEMENT_3D('',#3326,#3327,#3328);
#3330=PLANE('',#3329);
#3331=ORIENTED_EDGE('',*,*,#1396,.T.);
#3332=DIRECTION('',(0.,0.,-1.));
#3333=VECTOR('',#3332,1.);
#3334=CARTESIAN_POINT('',(15.,305.070539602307,15.));
#3335=LINE('',#3334,#3333);
#3336=EDGE_CURVE('E1341',#839,#1387,#3335,.T.);
#3337=ORIENTED_EDGE('',*,*,#3336,.F.);
#3338=ORIENTED_EDGE('',*,*,#840,.F.);
#3339=ORIENTED_EDGE('',*,*,#3319,.T.);
#3340=EDGE_LOOP('',(#3331,#3337,#3338,#3339));
#3341=FACE_BOUND('',#3340,.T.);
#3342=ADVANCED_FACE('F1773',(#3341),#3330,.F.);
#3343=CARTESIAN_POINT('',(15.,302.070539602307,15.));
#3344=DIRECTION('',(0.,0.,-1.));
#3345=DIRECTION('',(-1.,0.,0.));
#3346=AXIS2_PLACEMENT_3D('',#3343,#3344,#3345);
#3347=CYLINDRICAL_SURFACE('',#3346,3.);
#3348=ORIENTED_EDGE('',*,*,#1388,.T.);
#3349=DIRECTION('',(0.,0.,-1.));
#3350=VECTOR('',#3349,1.);
#3351=CARTESIAN_POINT('',(15.,299.070539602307,15.));
#3352=LINE('',#3351,#3350);
#3353=EDGE_CURVE('E1338',#848,#1378,#3352,.T.);
#3354=ORIENTED_EDGE('',*,*,#3353,.F.);
#3355=ORIENTED_EDGE('',*,*,#849,.F.);
#3356=ORIENTED_EDGE('',*,*,#3336,.T.);
#3357=EDGE_LOOP('',(#3348,#3354,#3355,#3356));
#3358=FACE_BOUND('',#3357,.T.);
#3359=ADVANCED_FACE('F1769',(#3358),#3347,.F.);
#3360=CARTESIAN_POINT('',(15.,295.970539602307,15.));
#3361=DIRECTION('',(1.,0.,0.));
#3362=DIRECTION('',(0.,0.,-1.));
#3363=AXIS2_PLACEMENT_3D('',#3360,#3361,#3362);
#3364=PLANE('',#3363);
#3365=ORIENTED_EDGE('',*,*,#1379,.T.);
#3366=DIRECTION('',(0.,0.,-1.));
#3367=VECTOR('',#3366,1.);
#3368=CARTESIAN_POINT('',(15.,295.970539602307,15.));
#3369=LINE('',#3368,#3367);
#3370=EDGE_CURVE('E1335',#856,#1370,#3369,.T.);
#3371=ORIENTED_EDGE('',*,*,#3370,.F.);
#3372=ORIENTED_EDGE('',*,*,#857,.F.);
#3373=ORIENTED_EDGE('',*,*,#3353,.T.);
#3374=EDGE_LOOP('',(#3365,#3371,#3372,#3373));
#3375=FACE_BOUND('',#3374,.T.);
#3376=ADVANCED_FACE('F1765',(#3375),#3364,.F.);
#3377=CARTESIAN_POINT('',(15.,292.970539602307,15.));
#3378=DIRECTION('',(0.,0.,-1.));
#3379=DIRECTION('',(-1.,0.,0.));
#3380=AXIS2_PLACEMENT_3D('',#3377,#3378,#3379);
#3381=CYLINDRICAL_SURFACE('',#3380,3.);
#3382=ORIENTED_EDGE('',*,*,#1371,.T.);
#3383=DIRECTION('',(0.,0.,-1.));
#3384=VECTOR('',#3383,1.);
#3385=CARTESIAN_POINT('',(15.,289.970539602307,15.));
#3386=LINE('',#3385,#3384);
#3387=EDGE_CURVE('E1332',#865,#1361,#3386,.T.);
#3388=ORIENTED_EDGE('',*,*,#3387,.F.);
#3389=ORIENTED_EDGE('',*,*,#866,.F.);
#3390=ORIENTED_EDGE('',*,*,#3370,.T.);
#3391=EDGE_LOOP('',(#3382,#3388,#3389,#3390));
#3392=FACE_BOUND('',#3391,.T.);
#3393=ADVANCED_FACE('F1761',(#3392),#3381,.F.);
#3394=CARTESIAN_POINT('',(15.,289.970539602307,15.));
#3395=DIRECTION('',(0.,-1.,0.));
#3396=DIRECTION('',(0.,0.,-1.));
#3397=AXIS2_PLACEMENT_3D('',#3394,#3395,#3396);
#3398=PLANE('',#3397);
#3399=ORIENTED_EDGE('',*,*,#1362,.T.);
#3400=DIRECTION('',(0.,0.,-1.));
#3401=VECTOR('',#3400,1.);
#3402=CARTESIAN_POINT('',(0.,289.970539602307,15.));
#3403=LINE('',#3402,#3401);
#3404=EDGE_CURVE('E1329',#873,#1353,#3403,.T.);
#3405=ORIENTED_EDGE('',*,*,#3404,.F.);
#3406=ORIENTED_EDGE('',*,*,#874,.F.);
#3407=ORIENTED_EDGE('',*,*,#3387,.T.);
#3408=EDGE_LOOP('',(#3399,#3405,#3406,#3407));
#3409=FACE_BOUND('',#3408,.T.);
#3410=ADVANCED_FACE('F1757',(#3409),#3398,.F.);
#3411=CARTESIAN_POINT('',(0.,289.970539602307,15.));
#3412=DIRECTION('',(1.,0.,0.));
#3413=DIRECTION('',(0.,0.,-1.));
#3414=AXIS2_PLACEMENT_3D('',#3411,#3412,#3413);
#3415=PLANE('',#3414);
#3416=ORIENTED_EDGE('',*,*,#1354,.T.);
#3417=DIRECTION('',(0.,0.,-1.));
#3418=VECTOR('',#3417,1.);
#3419=CARTESIAN_POINT('',(0.,90.1,15.));
#3420=LINE('',#3419,#3418);
#3421=EDGE_CURVE('E1326',#881,#1345,#3420,.T.);
#3422=ORIENTED_EDGE('',*,*,#3421,.F.);
#3423=ORIENTED_EDGE('',*,*,#882,.F.);
#3424=ORIENTED_EDGE('',*,*,#3404,.T.);
#3425=EDGE_LOOP('',(#3416,#3422,#3423,#3424));
#3426=FACE_BOUND('',#3425,.T.);
#3427=ADVANCED_FACE('F1753',(#3426),#3415,.F.);
#3428=CARTESIAN_POINT('',(0.,90.1,15.));
#3429=DIRECTION('',(0.,1.,0.));
#3430=DIRECTION('',(0.,0.,1.));
#3431=AXIS2_PLACEMENT_3D('',#3428,#3429,#3430);
#3432=PLANE('',#3431);
#3433=ORIENTED_EDGE('',*,*,#1346,.T.);
#3434=ORIENTED_EDGE('',*,*,#2182,.F.);
#3435=ORIENTED_EDGE('',*,*,#888,.F.);
#3436=ORIENTED_EDGE('',*,*,#3421,.T.);
#3437=EDGE_LOOP('',(#3433,#3434,#3435,#3436));
#3438=FACE_BOUND('',#3437,.T.);
#3439=ADVANCED_FACE('F1750',(#3438),#3432,.F.);
#3440=CARTESIAN_POINT('',(42.45,27.1,-2.5));
#3441=DIRECTION('',(0.,0.,1.));
#3442=DIRECTION('',(1.,0.,0.));
#3443=AXIS2_PLACEMENT_3D('',#3440,#3441,#3442);
#3444=CYLINDRICAL_SURFACE('',#3443,3.);
#3445=ORIENTED_EDGE('',*,*,#1268,.T.);
#3446=DIRECTION('',(0.,0.,1.));
#3447=VECTOR('',#3446,1.);
#3448=CARTESIAN_POINT('',(42.45,30.1,-2.5));
#3449=LINE('',#3448,#3447);
#3450=EDGE_CURVE('E1005',#1267,#213,#3449,.T.);
#3451=ORIENTED_EDGE('',*,*,#3450,.T.);
#3452=ORIENTED_EDGE('',*,*,#214,.F.);
#3453=DIRECTION('',(0.,0.,1.));
#3454=VECTOR('',#3453,1.);
#3455=CARTESIAN_POINT('',(42.45,24.1,-2.5));
#3456=LINE('',#3455,#3454);
#3457=EDGE_CURVE('E1004',#1265,#202,#3456,.T.);
#3458=ORIENTED_EDGE('',*,*,#3457,.F.);
#3459=EDGE_LOOP('',(#3445,#3451,#3452,#3458));
#3460=FACE_BOUND('',#3459,.T.);
#3461=ADVANCED_FACE('F1747',(#3460),#3444,.F.);
#3462=CARTESIAN_POINT('',(0.,30.1,-2.5));
#3463=DIRECTION('',(0.,-1.,0.));
#3464=DIRECTION('',(0.,0.,-1.));
#3465=AXIS2_PLACEMENT_3D('',#3462,#3463,#3464);
#3466=PLANE('',#3465);
#3467=ORIENTED_EDGE('',*,*,#1325,.T.);
#3468=DIRECTION('',(0.,0.,1.));
#3469=VECTOR('',#3468,1.);
#3470=CARTESIAN_POINT('',(57.55,30.1,-2.5));
#3471=LINE('',#3470,#3469);
#3472=EDGE_CURVE('E1008',#1318,#221,#3471,.T.);
#3473=ORIENTED_EDGE('',*,*,#3472,.T.);
#3474=ORIENTED_EDGE('',*,*,#222,.F.);
#3475=ORIENTED_EDGE('',*,*,#3450,.F.);
#3476=EDGE_LOOP('',(#3467,#3473,#3474,#3475));
#3477=FACE_BOUND('',#3476,.T.);
#3478=ADVANCED_FACE('F2398',(#3477),#3466,.T.);
#3479=CARTESIAN_POINT('',(57.55,27.1,-2.5));
#3480=DIRECTION('',(0.,0.,1.));
#3481=DIRECTION('',(1.,0.,0.));
#3482=AXIS2_PLACEMENT_3D('',#3479,#3480,#3481);
#3483=CYLINDRICAL_SURFACE('',#3482,3.);
#3484=ORIENTED_EDGE('',*,*,#1319,.T.);
#3485=DIRECTION('',(0.,0.,1.));
#3486=VECTOR('',#3485,1.);
#3487=CARTESIAN_POINT('',(57.55,24.1,-2.5));
#3488=LINE('',#3487,#3486);
#3489=EDGE_CURVE('E1010',#1309,#230,#3488,.T.);
#3490=ORIENTED_EDGE('',*,*,#3489,.T.);
#3491=ORIENTED_EDGE('',*,*,#231,.F.);
#3492=ORIENTED_EDGE('',*,*,#3472,.F.);
#3493=EDGE_LOOP('',(#3484,#3490,#3491,#3492));
#3494=FACE_BOUND('',#3493,.T.);
#3495=ADVANCED_FACE('F2401',(#3494),#3483,.F.);
#3496=CARTESIAN_POINT('',(57.5500000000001,2.57634415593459E-13,-2.5));
#3497=DIRECTION('',(1.,0.,0.));
#3498=DIRECTION('',(0.,1.,0.));
#3499=AXIS2_PLACEMENT_3D('',#3496,#3497,#3498);
#3500=PLANE('',#3499);
#3501=DIRECTION('',(0.,0.,1.));
#3502=VECTOR('',#3501,1.);
#3503=CARTESIAN_POINT('',(57.55,21.,-2.5));
#3504=LINE('',#3503,#3502);
#3505=EDGE_CURVE('E1012',#1301,#238,#3504,.T.);
#3506=ORIENTED_EDGE('',*,*,#3505,.T.);
#3507=ORIENTED_EDGE('',*,*,#239,.T.);
#3508=ORIENTED_EDGE('',*,*,#3489,.F.);
#3509=ORIENTED_EDGE('',*,*,#1310,.F.);
#3510=EDGE_LOOP('',(#3506,#3507,#3508,#3509));
#3511=FACE_BOUND('',#3510,.T.);
#3512=ADVANCED_FACE('F2405',(#3511),#3500,.F.);
#3513=CARTESIAN_POINT('',(57.55,18.,-2.5));
#3514=DIRECTION('',(0.,0.,1.));
#3515=DIRECTION('',(1.,0.,0.));
#3516=AXIS2_PLACEMENT_3D('',#3513,#3514,#3515);
#3517=CYLINDRICAL_SURFACE('',#3516,3.);
#3518=ORIENTED_EDGE('',*,*,#1302,.T.);
#3519=DIRECTION('',(0.,0.,1.));
#3520=VECTOR('',#3519,1.);
#3521=CARTESIAN_POINT('',(57.55,15.,-2.5));
#3522=LINE('',#3521,#3520);
#3523=EDGE_CURVE('E1014',#1292,#247,#3522,.T.);
#3524=ORIENTED_EDGE('',*,*,#3523,.T.);
#3525=ORIENTED_EDGE('',*,*,#248,.F.);
#3526=ORIENTED_EDGE('',*,*,#3505,.F.);
#3527=EDGE_LOOP('',(#3518,#3524,#3525,#3526));
#3528=FACE_BOUND('',#3527,.T.);
#3529=ADVANCED_FACE('F2409',(#3528),#3517,.F.);
#3530=CARTESIAN_POINT('',(0.,15.,-2.5));
#3531=DIRECTION('',(0.,-1.,0.));
#3532=DIRECTION('',(1.,0.,0.));
#3533=AXIS2_PLACEMENT_3D('',#3530,#3531,#3532);
#3534=PLANE('',#3533);
#3535=DIRECTION('',(0.,0.,1.));
#3536=VECTOR('',#3535,1.);
#3537=CARTESIAN_POINT('',(42.45,15.,-2.5));
#3538=LINE('',#3537,#3536);
#3539=EDGE_CURVE('E1016',#1284,#255,#3538,.T.);
#3540=ORIENTED_EDGE('',*,*,#3539,.T.);
#3541=ORIENTED_EDGE('',*,*,#256,.T.);
#3542=ORIENTED_EDGE('',*,*,#3523,.F.);
#3543=ORIENTED_EDGE('',*,*,#1293,.F.);
#3544=EDGE_LOOP('',(#3540,#3541,#3542,#3543));
#3545=FACE_BOUND('',#3544,.T.);
#3546=ADVANCED_FACE('F2413',(#3545),#3534,.F.);
#3547=CARTESIAN_POINT('',(42.45,18.,-2.5));
#3548=DIRECTION('',(0.,0.,1.));
#3549=DIRECTION('',(1.,0.,0.));
#3550=AXIS2_PLACEMENT_3D('',#3547,#3548,#3549);
#3551=CYLINDRICAL_SURFACE('',#3550,3.);
#3552=DIRECTION('',(0.,0.,1.));
#3553=VECTOR('',#3552,1.);
#3554=CARTESIAN_POINT('',(42.45,21.,-2.5));
#3555=LINE('',#3554,#3553);
#3556=EDGE_CURVE('E1018',#1275,#204,#3555,.T.);
#3557=ORIENTED_EDGE('',*,*,#3556,.T.);
#3558=ORIENTED_EDGE('',*,*,#263,.T.);
#3559=ORIENTED_EDGE('',*,*,#3539,.F.);
#3560=ORIENTED_EDGE('',*,*,#1285,.F.);
#3561=EDGE_LOOP('',(#3557,#3558,#3559,#3560));
#3562=FACE_BOUND('',#3561,.T.);
#3563=ADVANCED_FACE('F2417',(#3562),#3551,.F.);
#3564=CARTESIAN_POINT('',(42.45,0.,-2.5));
#3565=DIRECTION('',(-1.,0.,0.));
#3566=DIRECTION('',(0.,0.,1.));
#3567=AXIS2_PLACEMENT_3D('',#3564,#3565,#3566);
#3568=PLANE('',#3567);
#3569=ORIENTED_EDGE('',*,*,#3457,.T.);
#3570=ORIENTED_EDGE('',*,*,#205,.T.);
#3571=ORIENTED_EDGE('',*,*,#3556,.F.);
#3572=ORIENTED_EDGE('',*,*,#1276,.F.);
#3573=EDGE_LOOP('',(#3569,#3570,#3571,#3572));
#3574=FACE_BOUND('',#3573,.T.);
#3575=ADVANCED_FACE('F2370',(#3574),#3568,.F.);
#3576=CARTESIAN_POINT('',(42.4499999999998,262.6,-2.5));
#3577=DIRECTION('',(0.,0.,1.));
#3578=DIRECTION('',(1.,0.,0.));
#3579=AXIS2_PLACEMENT_3D('',#3576,#3577,#3578);
#3580=CYLINDRICAL_SURFACE('',#3579,3.);
#3581=ORIENTED_EDGE('',*,*,#1963,.T.);
#3582=DIRECTION('',(0.,0.,1.));
#3583=VECTOR('',#3582,1.);
#3584=CARTESIAN_POINT('',(42.4499999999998,265.6,-2.5));
#3585=LINE('',#3584,#3583);
#3586=EDGE_CURVE('E939',#1962,#908,#3585,.T.);
#3587=ORIENTED_EDGE('',*,*,#3586,.T.);
#3588=ORIENTED_EDGE('',*,*,#909,.F.);
#3589=DIRECTION('',(0.,0.,1.));
#3590=VECTOR('',#3589,1.);
#3591=CARTESIAN_POINT('',(42.4499999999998,259.6,-2.5));
#3592=LINE('',#3591,#3590);
#3593=EDGE_CURVE('E940',#1960,#897,#3592,.T.);
#3594=ORIENTED_EDGE('',*,*,#3593,.F.);
#3595=EDGE_LOOP('',(#3581,#3587,#3588,#3594));
#3596=FACE_BOUND('',#3595,.T.);
#3597=ADVANCED_FACE('F2366',(#3596),#3580,.F.);
#3598=CARTESIAN_POINT('',(0.,265.6,-2.5));
#3599=DIRECTION('',(0.,-1.,0.));
#3600=DIRECTION('',(0.,0.,-1.));
#3601=AXIS2_PLACEMENT_3D('',#3598,#3599,#3600);
#3602=PLANE('',#3601);
#3603=ORIENTED_EDGE('',*,*,#2020,.T.);
#3604=DIRECTION('',(0.,0.,1.));
#3605=VECTOR('',#3604,1.);
#3606=CARTESIAN_POINT('',(57.5499999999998,265.6,-2.5));
#3607=LINE('',#3606,#3605);
#3608=EDGE_CURVE('E954',#2013,#916,#3607,.T.);
#3609=ORIENTED_EDGE('',*,*,#3608,.T.);
#3610=ORIENTED_EDGE('',*,*,#917,.F.);
#3611=ORIENTED_EDGE('',*,*,#3586,.F.);
#3612=EDGE_LOOP('',(#3603,#3609,#3610,#3611));
#3613=FACE_BOUND('',#3612,.T.);
#3614=ADVANCED_FACE('F2369',(#3613),#3602,.T.);
#3615=CARTESIAN_POINT('',(57.5499999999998,262.6,-2.5));
#3616=DIRECTION('',(0.,0.,1.));
#3617=DIRECTION('',(1.,0.,0.));
#3618=AXIS2_PLACEMENT_3D('',#3615,#3616,#3617);
#3619=CYLINDRICAL_SURFACE('',#3618,3.);
#3620=ORIENTED_EDGE('',*,*,#2014,.T.);
#3621=DIRECTION('',(0.,0.,1.));
#3622=VECTOR('',#3621,1.);
#3623=CARTESIAN_POINT('',(57.5499999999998,259.6,-2.5));
#3624=LINE('',#3623,#3622);
#3625=EDGE_CURVE('E952',#2004,#925,#3624,.T.);
#3626=ORIENTED_EDGE('',*,*,#3625,.T.);
#3627=ORIENTED_EDGE('',*,*,#926,.F.);
#3628=ORIENTED_EDGE('',*,*,#3608,.F.);
#3629=EDGE_LOOP('',(#3620,#3626,#3627,#3628));
#3630=FACE_BOUND('',#3629,.T.);
#3631=ADVANCED_FACE('F2390',(#3630),#3619,.F.);
#3632=CARTESIAN_POINT('',(57.5499999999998,0.,-2.5));
#3633=DIRECTION('',(1.,0.,0.));
#3634=DIRECTION('',(0.,0.,-1.));
#3635=AXIS2_PLACEMENT_3D('',#3632,#3633,#3634);
#3636=PLANE('',#3635);
#3637=DIRECTION('',(0.,0.,1.));
#3638=VECTOR('',#3637,1.);
#3639=CARTESIAN_POINT('',(57.5499999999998,256.5,-2.5));
#3640=LINE('',#3639,#3638);
#3641=EDGE_CURVE('E950',#1996,#933,#3640,.T.);
#3642=ORIENTED_EDGE('',*,*,#3641,.T.);
#3643=ORIENTED_EDGE('',*,*,#934,.T.);
#3644=ORIENTED_EDGE('',*,*,#3625,.F.);
#3645=ORIENTED_EDGE('',*,*,#2005,.F.);
#3646=EDGE_LOOP('',(#3642,#3643,#3644,#3645));
#3647=FACE_BOUND('',#3646,.T.);
#3648=ADVANCED_FACE('F2386',(#3647),#3636,.F.);
#3649=CARTESIAN_POINT('',(57.5499999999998,253.5,-2.5));
#3650=DIRECTION('',(0.,0.,1.));
#3651=DIRECTION('',(1.,0.,0.));
#3652=AXIS2_PLACEMENT_3D('',#3649,#3650,#3651);
#3653=CYLINDRICAL_SURFACE('',#3652,3.);
#3654=ORIENTED_EDGE('',*,*,#1997,.T.);
#3655=DIRECTION('',(0.,0.,1.));
#3656=VECTOR('',#3655,1.);
#3657=CARTESIAN_POINT('',(57.5499999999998,250.5,-2.5));
#3658=LINE('',#3657,#3656);
#3659=EDGE_CURVE('E948',#1987,#942,#3658,.T.);
#3660=ORIENTED_EDGE('',*,*,#3659,.T.);
#3661=ORIENTED_EDGE('',*,*,#943,.F.);
#3662=ORIENTED_EDGE('',*,*,#3641,.F.);
#3663=EDGE_LOOP('',(#3654,#3660,#3661,#3662));
#3664=FACE_BOUND('',#3663,.T.);
#3665=ADVANCED_FACE('F2382',(#3664),#3653,.F.);
#3666=CARTESIAN_POINT('',(0.,250.5,-2.5));
#3667=DIRECTION('',(0.,-1.,0.));
#3668=DIRECTION('',(0.,0.,-1.));
#3669=AXIS2_PLACEMENT_3D('',#3666,#3667,#3668);
#3670=PLANE('',#3669);
#3671=DIRECTION('',(0.,0.,1.));
#3672=VECTOR('',#3671,1.);
#3673=CARTESIAN_POINT('',(42.4499999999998,250.5,-2.5));
#3674=LINE('',#3673,#3672);
#3675=EDGE_CURVE('E946',#1979,#950,#3674,.T.);
#3676=ORIENTED_EDGE('',*,*,#3675,.T.);
#3677=ORIENTED_EDGE('',*,*,#951,.T.);
#3678=ORIENTED_EDGE('',*,*,#3659,.F.);
#3679=ORIENTED_EDGE('',*,*,#1988,.F.);
#3680=EDGE_LOOP('',(#3676,#3677,#3678,#3679));
#3681=FACE_BOUND('',#3680,.T.);
#3682=ADVANCED_FACE('F2378',(#3681),#3670,.F.);
#3683=CARTESIAN_POINT('',(42.4499999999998,253.5,-2.5));
#3684=DIRECTION('',(0.,0.,1.));
#3685=DIRECTION('',(1.,0.,0.));
#3686=AXIS2_PLACEMENT_3D('',#3683,#3684,#3685);
#3687=CYLINDRICAL_SURFACE('',#3686,3.);
#3688=DIRECTION('',(0.,0.,1.));
#3689=VECTOR('',#3688,1.);
#3690=CARTESIAN_POINT('',(42.4499999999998,256.5,-2.5));
#3691=LINE('',#3690,#3689);
#3692=EDGE_CURVE('E944',#1970,#899,#3691,.T.);
#3693=ORIENTED_EDGE('',*,*,#3692,.T.);
#3694=ORIENTED_EDGE('',*,*,#958,.T.);
#3695=ORIENTED_EDGE('',*,*,#3675,.F.);
#3696=ORIENTED_EDGE('',*,*,#1980,.F.);
#3697=EDGE_LOOP('',(#3693,#3694,#3695,#3696));
#3698=FACE_BOUND('',#3697,.T.);
#3699=ADVANCED_FACE('F2374',(#3698),#3687,.F.);
#3700=CARTESIAN_POINT('',(42.4500000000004,0.,-2.5));
#3701=DIRECTION('',(-1.,0.,0.));
#3702=DIRECTION('',(0.,-1.,0.));
#3703=AXIS2_PLACEMENT_3D('',#3700,#3701,#3702);
#3704=PLANE('',#3703);
#3705=ORIENTED_EDGE('',*,*,#3593,.T.);
#3706=ORIENTED_EDGE('',*,*,#900,.T.);
#3707=ORIENTED_EDGE('',*,*,#3692,.F.);
#3708=ORIENTED_EDGE('',*,*,#1971,.F.);
#3709=EDGE_LOOP('',(#3705,#3706,#3707,#3708));
#3710=FACE_BOUND('',#3709,.T.);
#3711=ADVANCED_FACE('F2337',(#3710),#3704,.F.);
#3712=CARTESIAN_POINT('',(42.4499999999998,232.5,-2.5));
#3713=DIRECTION('',(0.,0.,1.));
#3714=DIRECTION('',(1.,0.,0.));
#3715=AXIS2_PLACEMENT_3D('',#3712,#3713,#3714);
#3716=CYLINDRICAL_SURFACE('',#3715,3.);
#3717=ORIENTED_EDGE('',*,*,#1198,.T.);
#3718=DIRECTION('',(0.,0.,1.));
#3719=VECTOR('',#3718,1.);
#3720=CARTESIAN_POINT('',(42.4499999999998,235.5,-2.5));
#3721=LINE('',#3720,#3719);
#3722=EDGE_CURVE('E898',#1197,#143,#3721,.T.);
#3723=ORIENTED_EDGE('',*,*,#3722,.T.);
#3724=ORIENTED_EDGE('',*,*,#144,.F.);
#3725=DIRECTION('',(0.,0.,1.));
#3726=VECTOR('',#3725,1.);
#3727=CARTESIAN_POINT('',(42.4499999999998,229.5,-2.5));
#3728=LINE('',#3727,#3726);
#3729=EDGE_CURVE('E899',#1195,#132,#3728,.T.);
#3730=ORIENTED_EDGE('',*,*,#3729,.F.);
#3731=EDGE_LOOP('',(#3717,#3723,#3724,#3730));
#3732=FACE_BOUND('',#3731,.T.);
#3733=ADVANCED_FACE('F2333',(#3732),#3716,.F.);
#3734=CARTESIAN_POINT('',(0.,235.5,-2.5));
#3735=DIRECTION('',(0.,-1.,0.));
#3736=DIRECTION('',(0.,0.,-1.));
#3737=AXIS2_PLACEMENT_3D('',#3734,#3735,#3736);
#3738=PLANE('',#3737);
#3739=ORIENTED_EDGE('',*,*,#1255,.T.);
#3740=DIRECTION('',(0.,0.,1.));
#3741=VECTOR('',#3740,1.);
#3742=CARTESIAN_POINT('',(57.5499999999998,235.5,-2.5));
#3743=LINE('',#3742,#3741);
#3744=EDGE_CURVE('E913',#1248,#151,#3743,.T.);
#3745=ORIENTED_EDGE('',*,*,#3744,.T.);
#3746=ORIENTED_EDGE('',*,*,#152,.F.);
#3747=ORIENTED_EDGE('',*,*,#3722,.F.);
#3748=EDGE_LOOP('',(#3739,#3745,#3746,#3747));
#3749=FACE_BOUND('',#3748,.T.);
#3750=ADVANCED_FACE('F2336',(#3749),#3738,.T.);
#3751=CARTESIAN_POINT('',(57.5499999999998,232.5,-2.5));
#3752=DIRECTION('',(0.,0.,1.));
#3753=DIRECTION('',(1.,0.,0.));
#3754=AXIS2_PLACEMENT_3D('',#3751,#3752,#3753);
#3755=CYLINDRICAL_SURFACE('',#3754,2.99999999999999);
#3756=ORIENTED_EDGE('',*,*,#1249,.T.);
#3757=DIRECTION('',(0.,0.,1.));
#3758=VECTOR('',#3757,1.);
#3759=CARTESIAN_POINT('',(57.5499999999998,229.5,-2.5));
#3760=LINE('',#3759,#3758);
#3761=EDGE_CURVE('E911',#1239,#160,#3760,.T.);
#3762=ORIENTED_EDGE('',*,*,#3761,.T.);
#3763=ORIENTED_EDGE('',*,*,#161,.F.);
#3764=ORIENTED_EDGE('',*,*,#3744,.F.);
#3765=EDGE_LOOP('',(#3756,#3762,#3763,#3764));
#3766=FACE_BOUND('',#3765,.T.);
#3767=ADVANCED_FACE('F2358',(#3766),#3755,.F.);
#3768=CARTESIAN_POINT('',(57.5499999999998,0.,-2.5));
#3769=DIRECTION('',(1.,0.,0.));
#3770=DIRECTION('',(0.,0.,-1.));
#3771=AXIS2_PLACEMENT_3D('',#3768,#3769,#3770);
#3772=PLANE('',#3771);
#3773=DIRECTION('',(0.,0.,1.));
#3774=VECTOR('',#3773,1.);
#3775=CARTESIAN_POINT('',(57.5499999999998,226.4,-2.5));
#3776=LINE('',#3775,#3774);
#3777=EDGE_CURVE('E909',#1231,#168,#3776,.T.);
#3778=ORIENTED_EDGE('',*,*,#3777,.T.);
#3779=ORIENTED_EDGE('',*,*,#169,.T.);
#3780=ORIENTED_EDGE('',*,*,#3761,.F.);
#3781=ORIENTED_EDGE('',*,*,#1240,.F.);
#3782=EDGE_LOOP('',(#3778,#3779,#3780,#3781));
#3783=FACE_BOUND('',#3782,.T.);
#3784=ADVANCED_FACE('F2354',(#3783),#3772,.F.);
#3785=CARTESIAN_POINT('',(57.5499999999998,223.4,-2.5));
#3786=DIRECTION('',(0.,0.,1.));
#3787=DIRECTION('',(1.,0.,0.));
#3788=AXIS2_PLACEMENT_3D('',#3785,#3786,#3787);
#3789=CYLINDRICAL_SURFACE('',#3788,3.00000000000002);
#3790=ORIENTED_EDGE('',*,*,#1232,.T.);
#3791=DIRECTION('',(0.,0.,1.));
#3792=VECTOR('',#3791,1.);
#3793=CARTESIAN_POINT('',(57.5499999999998,220.4,-2.5));
#3794=LINE('',#3793,#3792);
#3795=EDGE_CURVE('E907',#1222,#177,#3794,.T.);
#3796=ORIENTED_EDGE('',*,*,#3795,.T.);
#3797=ORIENTED_EDGE('',*,*,#178,.F.);
#3798=ORIENTED_EDGE('',*,*,#3777,.F.);
#3799=EDGE_LOOP('',(#3790,#3796,#3797,#3798));
#3800=FACE_BOUND('',#3799,.T.);
#3801=ADVANCED_FACE('F2350',(#3800),#3789,.F.);
#3802=CARTESIAN_POINT('',(0.,220.4,-2.5));
#3803=DIRECTION('',(0.,-1.,0.));
#3804=DIRECTION('',(0.,0.,-1.));
#3805=AXIS2_PLACEMENT_3D('',#3802,#3803,#3804);
#3806=PLANE('',#3805);
#3807=DIRECTION('',(0.,0.,1.));
#3808=VECTOR('',#3807,1.);
#3809=CARTESIAN_POINT('',(42.4499999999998,220.4,-2.5));
#3810=LINE('',#3809,#3808);
#3811=EDGE_CURVE('E905',#1214,#185,#3810,.T.);
#3812=ORIENTED_EDGE('',*,*,#3811,.T.);
#3813=ORIENTED_EDGE('',*,*,#186,.T.);
#3814=ORIENTED_EDGE('',*,*,#3795,.F.);
#3815=ORIENTED_EDGE('',*,*,#1223,.F.);
#3816=EDGE_LOOP('',(#3812,#3813,#3814,#3815));
#3817=FACE_BOUND('',#3816,.T.);
#3818=ADVANCED_FACE('F2346',(#3817),#3806,.F.);
#3819=CARTESIAN_POINT('',(42.4499999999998,223.4,-2.5));
#3820=DIRECTION('',(0.,0.,1.));
#3821=DIRECTION('',(1.,0.,0.));
#3822=AXIS2_PLACEMENT_3D('',#3819,#3820,#3821);
#3823=CYLINDRICAL_SURFACE('',#3822,3.);
#3824=DIRECTION('',(0.,0.,1.));
#3825=VECTOR('',#3824,1.);
#3826=CARTESIAN_POINT('',(42.4499999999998,226.4,-2.5));
#3827=LINE('',#3826,#3825);
#3828=EDGE_CURVE('E903',#1205,#134,#3827,.T.);
#3829=ORIENTED_EDGE('',*,*,#3828,.T.);
#3830=ORIENTED_EDGE('',*,*,#193,.T.);
#3831=ORIENTED_EDGE('',*,*,#3811,.F.);
#3832=ORIENTED_EDGE('',*,*,#1215,.F.);
#3833=EDGE_LOOP('',(#3829,#3830,#3831,#3832));
#3834=FACE_BOUND('',#3833,.T.);
#3835=ADVANCED_FACE('F2342',(#3834),#3823,.F.);
#3836=CARTESIAN_POINT('',(42.4500000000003,0.,-2.5));
#3837=DIRECTION('',(-1.,0.,0.));
#3838=DIRECTION('',(0.,-1.,0.));
#3839=AXIS2_PLACEMENT_3D('',#3836,#3837,#3838);
#3840=PLANE('',#3839);
#3841=ORIENTED_EDGE('',*,*,#3729,.T.);
#3842=ORIENTED_EDGE('',*,*,#135,.T.);
#3843=ORIENTED_EDGE('',*,*,#3828,.F.);
#3844=ORIENTED_EDGE('',*,*,#1206,.F.);
#3845=EDGE_LOOP('',(#3841,#3842,#3843,#3844));
#3846=FACE_BOUND('',#3845,.T.);
#3847=ADVANCED_FACE('F2339',(#3846),#3840,.F.);
#3848=CARTESIAN_POINT('',(42.4499999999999,57.2,-2.5));
#3849=DIRECTION('',(0.,0.,1.));
#3850=DIRECTION('',(1.,0.,0.));
#3851=AXIS2_PLACEMENT_3D('',#3848,#3849,#3850);
#3852=CYLINDRICAL_SURFACE('',#3851,3.);
#3853=ORIENTED_EDGE('',*,*,#2033,.T.);
#3854=DIRECTION('',(0.,0.,1.));
#3855=VECTOR('',#3854,1.);
#3856=CARTESIAN_POINT('',(42.4499999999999,60.2,-2.5));
#3857=LINE('',#3856,#3855);
#3858=EDGE_CURVE('E857',#2032,#978,#3857,.T.);
#3859=ORIENTED_EDGE('',*,*,#3858,.T.);
#3860=ORIENTED_EDGE('',*,*,#979,.F.);
#3861=DIRECTION('',(0.,0.,1.));
#3862=VECTOR('',#3861,1.);
#3863=CARTESIAN_POINT('',(42.4499999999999,54.2,-2.5));
#3864=LINE('',#3863,#3862);
#3865=EDGE_CURVE('E858',#2030,#967,#3864,.T.);
#3866=ORIENTED_EDGE('',*,*,#3865,.F.);
#3867=EDGE_LOOP('',(#3853,#3859,#3860,#3866));
#3868=FACE_BOUND('',#3867,.T.);
#3869=ADVANCED_FACE('F2287',(#3868),#3852,.F.);
#3870=CARTESIAN_POINT('',(0.,60.2,-2.5));
#3871=DIRECTION('',(0.,-1.,0.));
#3872=DIRECTION('',(0.,0.,-1.));
#3873=AXIS2_PLACEMENT_3D('',#3870,#3871,#3872);
#3874=PLANE('',#3873);
#3875=ORIENTED_EDGE('',*,*,#2090,.T.);
#3876=DIRECTION('',(0.,0.,1.));
#3877=VECTOR('',#3876,1.);
#3878=CARTESIAN_POINT('',(57.5499999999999,60.2,-2.5));
#3879=LINE('',#3878,#3877);
#3880=EDGE_CURVE('E872',#2083,#986,#3879,.T.);
#3881=ORIENTED_EDGE('',*,*,#3880,.T.);
#3882=ORIENTED_EDGE('',*,*,#987,.F.);
#3883=ORIENTED_EDGE('',*,*,#3858,.F.);
#3884=EDGE_LOOP('',(#3875,#3881,#3882,#3883));
#3885=FACE_BOUND('',#3884,.T.);
#3886=ADVANCED_FACE('F2294',(#3885),#3874,.T.);
#3887=CARTESIAN_POINT('',(57.5499999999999,57.2,-2.5));
#3888=DIRECTION('',(0.,0.,1.));
#3889=DIRECTION('',(1.,0.,0.));
#3890=AXIS2_PLACEMENT_3D('',#3887,#3888,#3889);
#3891=CYLINDRICAL_SURFACE('',#3890,3.);
#3892=ORIENTED_EDGE('',*,*,#2084,.T.);
#3893=DIRECTION('',(0.,0.,1.));
#3894=VECTOR('',#3893,1.);
#3895=CARTESIAN_POINT('',(57.5499999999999,54.2,-2.5));
#3896=LINE('',#3895,#3894);
#3897=EDGE_CURVE('E870',#2074,#995,#3896,.T.);
#3898=ORIENTED_EDGE('',*,*,#3897,.T.);
#3899=ORIENTED_EDGE('',*,*,#996,.F.);
#3900=ORIENTED_EDGE('',*,*,#3880,.F.);
#3901=EDGE_LOOP('',(#3892,#3898,#3899,#3900));
#3902=FACE_BOUND('',#3901,.T.);
#3903=ADVANCED_FACE('F2298',(#3902),#3891,.F.);
#3904=CARTESIAN_POINT('',(57.5499999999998,-1.28817207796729E-13,-2.5));
#3905=DIRECTION('',(1.,0.,0.));
#3906=DIRECTION('',(0.,1.,0.));
#3907=AXIS2_PLACEMENT_3D('',#3904,#3905,#3906);
#3908=PLANE('',#3907);
#3909=DIRECTION('',(0.,0.,1.));
#3910=VECTOR('',#3909,1.);
#3911=CARTESIAN_POINT('',(57.5499999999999,51.1,-2.5));
#3912=LINE('',#3911,#3910);
#3913=EDGE_CURVE('E868',#2066,#1003,#3912,.T.);
#3914=ORIENTED_EDGE('',*,*,#3913,.T.);
#3915=ORIENTED_EDGE('',*,*,#1004,.T.);
#3916=ORIENTED_EDGE('',*,*,#3897,.F.);
#3917=ORIENTED_EDGE('',*,*,#2075,.F.);
#3918=EDGE_LOOP('',(#3914,#3915,#3916,#3917));
#3919=FACE_BOUND('',#3918,.T.);
#3920=ADVANCED_FACE('F2303',(#3919),#3908,.F.);
#3921=CARTESIAN_POINT('',(57.5499999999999,48.1,-2.5));
#3922=DIRECTION('',(0.,0.,1.));
#3923=DIRECTION('',(1.,0.,0.));
#3924=AXIS2_PLACEMENT_3D('',#3921,#3922,#3923);
#3925=CYLINDRICAL_SURFACE('',#3924,3.);
#3926=ORIENTED_EDGE('',*,*,#2067,.T.);
#3927=DIRECTION('',(0.,0.,1.));
#3928=VECTOR('',#3927,1.);
#3929=CARTESIAN_POINT('',(57.5499999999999,45.1,-2.5));
#3930=LINE('',#3929,#3928);
#3931=EDGE_CURVE('E866',#2057,#1012,#3930,.T.);
#3932=ORIENTED_EDGE('',*,*,#3931,.T.);
#3933=ORIENTED_EDGE('',*,*,#1013,.F.);
#3934=ORIENTED_EDGE('',*,*,#3913,.F.);
#3935=EDGE_LOOP('',(#3926,#3932,#3933,#3934));
#3936=FACE_BOUND('',#3935,.T.);
#3937=ADVANCED_FACE('F2307',(#3936),#3925,.F.);
#3938=CARTESIAN_POINT('',(0.,45.1,-2.5));
#3939=DIRECTION('',(0.,-1.,0.));
#3940=DIRECTION('',(0.,0.,-1.));
#3941=AXIS2_PLACEMENT_3D('',#3938,#3939,#3940);
#3942=PLANE('',#3941);
#3943=DIRECTION('',(0.,0.,1.));
#3944=VECTOR('',#3943,1.);
#3945=CARTESIAN_POINT('',(42.4499999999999,45.1,-2.5));
#3946=LINE('',#3945,#3944);
#3947=EDGE_CURVE('E864',#2049,#1020,#3946,.T.);
#3948=ORIENTED_EDGE('',*,*,#3947,.T.);
#3949=ORIENTED_EDGE('',*,*,#1021,.T.);
#3950=ORIENTED_EDGE('',*,*,#3931,.F.);
#3951=ORIENTED_EDGE('',*,*,#2058,.F.);
#3952=EDGE_LOOP('',(#3948,#3949,#3950,#3951));
#3953=FACE_BOUND('',#3952,.T.);
#3954=ADVANCED_FACE('F2310',(#3953),#3942,.F.);
#3955=CARTESIAN_POINT('',(42.4499999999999,48.1,-2.5));
#3956=DIRECTION('',(0.,0.,1.));
#3957=DIRECTION('',(1.,0.,0.));
#3958=AXIS2_PLACEMENT_3D('',#3955,#3956,#3957);
#3959=CYLINDRICAL_SURFACE('',#3958,3.);
#3960=DIRECTION('',(0.,0.,1.));
#3961=VECTOR('',#3960,1.);
#3962=CARTESIAN_POINT('',(42.4499999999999,51.1,-2.5));
#3963=LINE('',#3962,#3961);
#3964=EDGE_CURVE('E862',#2040,#969,#3963,.T.);
#3965=ORIENTED_EDGE('',*,*,#3964,.T.);
#3966=ORIENTED_EDGE('',*,*,#1028,.T.);
#3967=ORIENTED_EDGE('',*,*,#3947,.F.);
#3968=ORIENTED_EDGE('',*,*,#2050,.F.);
#3969=EDGE_LOOP('',(#3965,#3966,#3967,#3968));
#3970=FACE_BOUND('',#3969,.T.);
#3971=ADVANCED_FACE('F2313',(#3970),#3959,.F.);
#3972=CARTESIAN_POINT('',(42.45,0.,-2.5));
#3973=DIRECTION('',(-1.,0.,0.));
#3974=DIRECTION('',(0.,-1.,0.));
#3975=AXIS2_PLACEMENT_3D('',#3972,#3973,#3974);
#3976=PLANE('',#3975);
#3977=ORIENTED_EDGE('',*,*,#3865,.T.);
#3978=ORIENTED_EDGE('',*,*,#970,.T.);
#3979=ORIENTED_EDGE('',*,*,#3964,.F.);
#3980=ORIENTED_EDGE('',*,*,#2041,.F.);
#3981=EDGE_LOOP('',(#3977,#3978,#3979,#3980));
#3982=FACE_BOUND('',#3981,.T.);
#3983=ADVANCED_FACE('F2282',(#3982),#3976,.F.);
#3984=CARTESIAN_POINT('',(42.4499999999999,87.3,-2.5));
#3985=DIRECTION('',(0.,0.,1.));
#3986=DIRECTION('',(1.,0.,0.));
#3987=AXIS2_PLACEMENT_3D('',#3984,#3985,#3986);
#3988=CYLINDRICAL_SURFACE('',#3987,3.);
#3989=ORIENTED_EDGE('',*,*,#1128,.T.);
#3990=DIRECTION('',(0.,0.,1.));
#3991=VECTOR('',#3990,1.);
#3992=CARTESIAN_POINT('',(42.4499999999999,90.3,-2.5));
#3993=LINE('',#3992,#3991);
#3994=EDGE_CURVE('E811',#1127,#73,#3993,.T.);
#3995=ORIENTED_EDGE('',*,*,#3994,.T.);
#3996=ORIENTED_EDGE('',*,*,#74,.F.);
#3997=DIRECTION('',(0.,0.,1.));
#3998=VECTOR('',#3997,1.);
#3999=CARTESIAN_POINT('',(42.4499999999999,84.3,-2.5));
#4000=LINE('',#3999,#3998);
#4001=EDGE_CURVE('E819',#1125,#62,#4000,.T.);
#4002=ORIENTED_EDGE('',*,*,#4001,.F.);
#4003=EDGE_LOOP('',(#3989,#3995,#3996,#4002));
#4004=FACE_BOUND('',#4003,.T.);
#4005=ADVANCED_FACE('F2320',(#4004),#3988,.F.);
#4006=CARTESIAN_POINT('',(0.,90.3,-2.5));
#4007=DIRECTION('',(0.,-1.,0.));
#4008=DIRECTION('',(1.,0.,0.));
#4009=AXIS2_PLACEMENT_3D('',#4006,#4007,#4008);
#4010=PLANE('',#4009);
#4011=ORIENTED_EDGE('',*,*,#1185,.T.);
#4012=DIRECTION('',(0.,0.,1.));
#4013=VECTOR('',#4012,1.);
#4014=CARTESIAN_POINT('',(57.5499999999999,90.3,-2.5));
#4015=LINE('',#4014,#4013);
#4016=EDGE_CURVE('E813',#1178,#81,#4015,.T.);
#4017=ORIENTED_EDGE('',*,*,#4016,.T.);
#4018=ORIENTED_EDGE('',*,*,#82,.F.);
#4019=ORIENTED_EDGE('',*,*,#3994,.F.);
#4020=EDGE_LOOP('',(#4011,#4017,#4018,#4019));
#4021=FACE_BOUND('',#4020,.T.);
#4022=ADVANCED_FACE('F2632',(#4021),#4010,.T.);
#4023=CARTESIAN_POINT('',(57.5499999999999,87.3,-2.5));
#4024=DIRECTION('',(0.,0.,1.));
#4025=DIRECTION('',(1.,0.,0.));
#4026=AXIS2_PLACEMENT_3D('',#4023,#4024,#4025);
#4027=CYLINDRICAL_SURFACE('',#4026,3.);
#4028=ORIENTED_EDGE('',*,*,#1179,.T.);
#4029=DIRECTION('',(0.,0.,1.));
#4030=VECTOR('',#4029,1.);
#4031=CARTESIAN_POINT('',(57.5499999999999,84.3,-2.5));
#4032=LINE('',#4031,#4030);
#4033=EDGE_CURVE('E831',#1169,#90,#4032,.T.);
#4034=ORIENTED_EDGE('',*,*,#4033,.T.);
#4035=ORIENTED_EDGE('',*,*,#91,.F.);
#4036=ORIENTED_EDGE('',*,*,#4016,.F.);
#4037=EDGE_LOOP('',(#4028,#4034,#4035,#4036));
#4038=FACE_BOUND('',#4037,.T.);
#4039=ADVANCED_FACE('F2642',(#4038),#4027,.F.);
#4040=CARTESIAN_POINT('',(57.5499999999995,-2.57634415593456E-13,-2.5));
#4041=DIRECTION('',(1.,0.,0.));
#4042=DIRECTION('',(0.,1.,0.));
#4043=AXIS2_PLACEMENT_3D('',#4040,#4041,#4042);
#4044=PLANE('',#4043);
#4045=DIRECTION('',(0.,0.,1.));
#4046=VECTOR('',#4045,1.);
#4047=CARTESIAN_POINT('',(57.5499999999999,81.2,-2.5));
#4048=LINE('',#4047,#4046);
#4049=EDGE_CURVE('E829',#1161,#98,#4048,.T.);
#4050=ORIENTED_EDGE('',*,*,#4049,.T.);
#4051=ORIENTED_EDGE('',*,*,#99,.T.);
#4052=ORIENTED_EDGE('',*,*,#4033,.F.);
#4053=ORIENTED_EDGE('',*,*,#1170,.F.);
#4054=EDGE_LOOP('',(#4050,#4051,#4052,#4053));
#4055=FACE_BOUND('',#4054,.T.);
#4056=ADVANCED_FACE('F2652',(#4055),#4044,.F.);
#4057=CARTESIAN_POINT('',(57.5499999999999,78.2,-2.5));
#4058=DIRECTION('',(0.,0.,1.));
#4059=DIRECTION('',(1.,0.,0.));
#4060=AXIS2_PLACEMENT_3D('',#4057,#4058,#4059);
#4061=CYLINDRICAL_SURFACE('',#4060,3.);
#4062=ORIENTED_EDGE('',*,*,#1162,.T.);
#4063=DIRECTION('',(0.,0.,1.));
#4064=VECTOR('',#4063,1.);
#4065=CARTESIAN_POINT('',(57.5499999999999,75.2,-2.5));
#4066=LINE('',#4065,#4064);
#4067=EDGE_CURVE('E827',#1152,#107,#4066,.T.);
#4068=ORIENTED_EDGE('',*,*,#4067,.T.);
#4069=ORIENTED_EDGE('',*,*,#108,.F.);
#4070=ORIENTED_EDGE('',*,*,#4049,.F.);
#4071=EDGE_LOOP('',(#4062,#4068,#4069,#4070));
#4072=FACE_BOUND('',#4071,.T.);
#4073=ADVANCED_FACE('F2662',(#4072),#4061,.F.);
#4074=CARTESIAN_POINT('',(0.,75.2,-2.5));
#4075=DIRECTION('',(0.,-1.,0.));
#4076=DIRECTION('',(0.,0.,-1.));
#4077=AXIS2_PLACEMENT_3D('',#4074,#4075,#4076);
#4078=PLANE('',#4077);
#4079=DIRECTION('',(0.,0.,1.));
#4080=VECTOR('',#4079,1.);
#4081=CARTESIAN_POINT('',(42.4499999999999,75.2,-2.5));
#4082=LINE('',#4081,#4080);
#4083=EDGE_CURVE('E825',#1144,#115,#4082,.T.);
#4084=ORIENTED_EDGE('',*,*,#4083,.T.);
#4085=ORIENTED_EDGE('',*,*,#116,.T.);
#4086=ORIENTED_EDGE('',*,*,#4067,.F.);
#4087=ORIENTED_EDGE('',*,*,#1153,.F.);
#4088=EDGE_LOOP('',(#4084,#4085,#4086,#4087));
#4089=FACE_BOUND('',#4088,.T.);
#4090=ADVANCED_FACE('F2672',(#4089),#4078,.F.);
#4091=CARTESIAN_POINT('',(42.4499999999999,78.2,-2.5));
#4092=DIRECTION('',(0.,0.,1.));
#4093=DIRECTION('',(1.,0.,0.));
#4094=AXIS2_PLACEMENT_3D('',#4091,#4092,#4093);
#4095=CYLINDRICAL_SURFACE('',#4094,3.);
#4096=DIRECTION('',(0.,0.,1.));
#4097=VECTOR('',#4096,1.);
#4098=CARTESIAN_POINT('',(42.4499999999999,81.2,-2.5));
#4099=LINE('',#4098,#4097);
#4100=EDGE_CURVE('E823',#1135,#64,#4099,.T.);
#4101=ORIENTED_EDGE('',*,*,#4100,.T.);
#4102=ORIENTED_EDGE('',*,*,#123,.T.);
#4103=ORIENTED_EDGE('',*,*,#4083,.F.);
#4104=ORIENTED_EDGE('',*,*,#1145,.F.);
#4105=EDGE_LOOP('',(#4101,#4102,#4103,#4104));
#4106=FACE_BOUND('',#4105,.T.);
#4107=ADVANCED_FACE('F2682',(#4106),#4095,.F.);
#4108=CARTESIAN_POINT('',(42.4499999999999,0.,-2.5));
#4109=DIRECTION('',(-1.,0.,0.));
#4110=DIRECTION('',(0.,0.,1.));
#4111=AXIS2_PLACEMENT_3D('',#4108,#4109,#4110);
#4112=PLANE('',#4111);
#4113=ORIENTED_EDGE('',*,*,#4001,.T.);
#4114=ORIENTED_EDGE('',*,*,#65,.T.);
#4115=ORIENTED_EDGE('',*,*,#4100,.F.);
#4116=ORIENTED_EDGE('',*,*,#1136,.F.);
#4117=EDGE_LOOP('',(#4113,#4114,#4115,#4116));
#4118=FACE_BOUND('',#4117,.T.);
#4119=ADVANCED_FACE('F2692',(#4118),#4112,.F.);
#4120=CARTESIAN_POINT('',(42.4499999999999,202.4,-2.5));
#4121=DIRECTION('',(0.,0.,1.));
#4122=DIRECTION('',(1.,0.,0.));
#4123=AXIS2_PLACEMENT_3D('',#4120,#4121,#4122);
#4124=CYLINDRICAL_SURFACE('',#4123,3.);
#4125=ORIENTED_EDGE('',*,*,#2103,.T.);
#4126=DIRECTION('',(0.,0.,1.));
#4127=VECTOR('',#4126,1.);
#4128=CARTESIAN_POINT('',(42.4499999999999,205.4,-2.5));
#4129=LINE('',#4128,#4127);
#4130=EDGE_CURVE('E789',#2102,#1048,#4129,.T.);
#4131=ORIENTED_EDGE('',*,*,#4130,.T.);
#4132=ORIENTED_EDGE('',*,*,#1049,.F.);
#4133=DIRECTION('',(0.,0.,1.));
#4134=VECTOR('',#4133,1.);
#4135=CARTESIAN_POINT('',(42.4499999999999,199.4,-2.5));
#4136=LINE('',#4135,#4134);
#4137=EDGE_CURVE('E806',#2100,#1037,#4136,.T.);
#4138=ORIENTED_EDGE('',*,*,#4137,.F.);
#4139=EDGE_LOOP('',(#4125,#4131,#4132,#4138));
#4140=FACE_BOUND('',#4139,.T.);
#4141=ADVANCED_FACE('F791',(#4140),#4124,.F.);
#4142=CARTESIAN_POINT('',(0.,205.4,-2.5));
#4143=DIRECTION('',(0.,-1.,0.));
#4144=DIRECTION('',(0.,0.,-1.));
#4145=AXIS2_PLACEMENT_3D('',#4142,#4143,#4144);
#4146=PLANE('',#4145);
#4147=ORIENTED_EDGE('',*,*,#2160,.T.);
#4148=DIRECTION('',(0.,0.,1.));
#4149=VECTOR('',#4148,1.);
#4150=CARTESIAN_POINT('',(57.5499999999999,205.4,-2.5));
#4151=LINE('',#4150,#4149);
#4152=EDGE_CURVE('E795',#2153,#1056,#4151,.T.);
#4153=ORIENTED_EDGE('',*,*,#4152,.T.);
#4154=ORIENTED_EDGE('',*,*,#1057,.F.);
#4155=ORIENTED_EDGE('',*,*,#4130,.F.);
#4156=EDGE_LOOP('',(#4147,#4153,#4154,#4155));
#4157=FACE_BOUND('',#4156,.T.);
#4158=ADVANCED_FACE('F800',(#4157),#4146,.T.);
#4159=CARTESIAN_POINT('',(57.5499999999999,202.4,-2.5));
#4160=DIRECTION('',(0.,0.,1.));
#4161=DIRECTION('',(1.,0.,0.));
#4162=AXIS2_PLACEMENT_3D('',#4159,#4160,#4161);
#4163=CYLINDRICAL_SURFACE('',#4162,3.);
#4164=ORIENTED_EDGE('',*,*,#2154,.T.);
#4165=DIRECTION('',(0.,0.,1.));
#4166=VECTOR('',#4165,1.);
#4167=CARTESIAN_POINT('',(57.5499999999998,199.4,-2.5));
#4168=LINE('',#4167,#4166);
#4169=EDGE_CURVE('E1669',#2144,#1065,#4168,.T.);
#4170=ORIENTED_EDGE('',*,*,#4169,.T.);
#4171=ORIENTED_EDGE('',*,*,#1066,.F.);
#4172=ORIENTED_EDGE('',*,*,#4152,.F.);
#4173=EDGE_LOOP('',(#4164,#4170,#4171,#4172));
#4174=FACE_BOUND('',#4173,.T.);
#4175=ADVANCED_FACE('F1667',(#4174),#4163,.F.);
#4176=CARTESIAN_POINT('',(57.5499999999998,0.,-2.5));
#4177=DIRECTION('',(1.,0.,0.));
#4178=DIRECTION('',(0.,0.,-1.));
#4179=AXIS2_PLACEMENT_3D('',#4176,#4177,#4178);
#4180=PLANE('',#4179);
#4181=DIRECTION('',(0.,0.,1.));
#4182=VECTOR('',#4181,1.);
#4183=CARTESIAN_POINT('',(57.5499999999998,196.3,-2.5));
#4184=LINE('',#4183,#4182);
#4185=EDGE_CURVE('E1677',#2136,#1073,#4184,.T.);
#4186=ORIENTED_EDGE('',*,*,#4185,.T.);
#4187=ORIENTED_EDGE('',*,*,#1074,.T.);
#4188=ORIENTED_EDGE('',*,*,#4169,.F.);
#4189=ORIENTED_EDGE('',*,*,#2145,.F.);
#4190=EDGE_LOOP('',(#4186,#4187,#4188,#4189));
#4191=FACE_BOUND('',#4190,.T.);
#4192=ADVANCED_FACE('F1675',(#4191),#4180,.F.);
#4193=CARTESIAN_POINT('',(57.5499999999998,193.3,-2.5));
#4194=DIRECTION('',(0.,0.,1.));
#4195=DIRECTION('',(1.,0.,0.));
#4196=AXIS2_PLACEMENT_3D('',#4193,#4194,#4195);
#4197=CYLINDRICAL_SURFACE('',#4196,2.99999999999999);
#4198=ORIENTED_EDGE('',*,*,#2137,.T.);
#4199=DIRECTION('',(0.,0.,1.));
#4200=VECTOR('',#4199,1.);
#4201=CARTESIAN_POINT('',(57.5499999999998,190.3,-2.5));
#4202=LINE('',#4201,#4200);
#4203=EDGE_CURVE('E1685',#2127,#1082,#4202,.T.);
#4204=ORIENTED_EDGE('',*,*,#4203,.T.);
#4205=ORIENTED_EDGE('',*,*,#1083,.F.);
#4206=ORIENTED_EDGE('',*,*,#4185,.F.);
#4207=EDGE_LOOP('',(#4198,#4204,#4205,#4206));
#4208=FACE_BOUND('',#4207,.T.);
#4209=ADVANCED_FACE('F1680',(#4208),#4197,.F.);
#4210=CARTESIAN_POINT('',(-3.49793777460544E-13,190.3,-2.5));
#4211=DIRECTION('',(0.,-1.,0.));
#4212=DIRECTION('',(1.,0.,0.));
#4213=AXIS2_PLACEMENT_3D('',#4210,#4211,#4212);
#4214=PLANE('',#4213);
#4215=DIRECTION('',(0.,0.,1.));
#4216=VECTOR('',#4215,1.);
#4217=CARTESIAN_POINT('',(42.4499999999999,190.3,-2.5));
#4218=LINE('',#4217,#4216);
#4219=EDGE_CURVE('E1687',#2119,#1090,#4218,.T.);
#4220=ORIENTED_EDGE('',*,*,#4219,.T.);
#4221=ORIENTED_EDGE('',*,*,#1091,.T.);
#4222=ORIENTED_EDGE('',*,*,#4203,.F.);
#4223=ORIENTED_EDGE('',*,*,#2128,.F.);
#4224=EDGE_LOOP('',(#4220,#4221,#4222,#4223));
#4225=FACE_BOUND('',#4224,.T.);
#4226=ADVANCED_FACE('F1704',(#4225),#4214,.F.);
#4227=CARTESIAN_POINT('',(42.4499999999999,193.3,-2.5));
#4228=DIRECTION('',(0.,0.,1.));
#4229=DIRECTION('',(1.,0.,0.));
#4230=AXIS2_PLACEMENT_3D('',#4227,#4228,#4229);
#4231=CYLINDRICAL_SURFACE('',#4230,3.);
#4232=DIRECTION('',(0.,0.,1.));
#4233=VECTOR('',#4232,1.);
#4234=CARTESIAN_POINT('',(42.4499999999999,196.3,-2.5));
#4235=LINE('',#4234,#4233);
#4236=EDGE_CURVE('E59',#2110,#1039,#4235,.T.);
#4237=ORIENTED_EDGE('',*,*,#4236,.T.);
#4238=ORIENTED_EDGE('',*,*,#1098,.T.);
#4239=ORIENTED_EDGE('',*,*,#4219,.F.);
#4240=ORIENTED_EDGE('',*,*,#2120,.F.);
#4241=EDGE_LOOP('',(#4237,#4238,#4239,#4240));
#4242=FACE_BOUND('',#4241,.T.);
#4243=ADVANCED_FACE('F1702',(#4242),#4231,.F.);
#4244=CARTESIAN_POINT('',(42.4500000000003,0.,-2.5));
#4245=DIRECTION('',(-1.,0.,0.));
#4246=DIRECTION('',(0.,-1.,0.));
#4247=AXIS2_PLACEMENT_3D('',#4244,#4245,#4246);
#4248=PLANE('',#4247);
#4249=ORIENTED_EDGE('',*,*,#4137,.T.);
#4250=ORIENTED_EDGE('',*,*,#1040,.T.);
#4251=ORIENTED_EDGE('',*,*,#4236,.F.);
#4252=ORIENTED_EDGE('',*,*,#2111,.F.);
#4253=EDGE_LOOP('',(#4249,#4250,#4251,#4252));
#4254=FACE_BOUND('',#4253,.T.);
#4255=ADVANCED_FACE('F2759',(#4254),#4248,.F.);
#4256=CARTESIAN_POINT('',(50.,350.270515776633,7.5));
#4257=DIRECTION('',(0.,0.,1.));
#4258=DIRECTION('',(1.,0.,0.));
#4259=AXIS2_PLACEMENT_3D('',#4256,#4257,#4258);
#4260=CYLINDRICAL_SURFACE('',#4259,5.05000000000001);
#4261=CARTESIAN_POINT('',(50.,350.270515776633,7.5));
#4262=DIRECTION('',(0.,0.,1.));
#4263=DIRECTION('',(1.,0.,0.));
#4264=AXIS2_PLACEMENT_3D('',#4261,#4262,#4263);
#4265=CIRCLE('',#4264,5.05000000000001);
#4266=CARTESIAN_POINT('',(55.05,350.270515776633,7.5));
#4267=VERTEX_POINT('',#4266);
#4268=EDGE_CURVE('E796',#4267,#4267,#4265,.T.);
#4269=ORIENTED_EDGE('',*,*,#4268,.F.);
#4270=EDGE_LOOP('',(#4269));
#4271=FACE_BOUND('',#4270,.T.);
#4272=ORIENTED_EDGE('',*,*,#53,.T.);
#4273=EDGE_LOOP('',(#4272));
#4274=FACE_BOUND('',#4273,.T.);
#4275=ADVANCED_FACE('F2768',(#4271,#4274),#4260,.F.);
#4276=CARTESIAN_POINT('',(0.,0.,7.5));
#4277=DIRECTION('',(0.,0.,1.));
#4278=DIRECTION('',(1.,0.,0.));
#4279=AXIS2_PLACEMENT_3D('',#4276,#4277,#4278);
#4280=PLANE('',#4279);
#4281=ORIENTED_EDGE('',*,*,#4268,.T.);
#4282=EDGE_LOOP('',(#4281));
#4283=FACE_BOUND('',#4282,.T.);
#4284=ADVANCED_FACE('F2777',(#4283),#4280,.T.);
#4285=CARTESIAN_POINT('',(50.,280.270515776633,7.5));
#4286=DIRECTION('',(0.,0.,1.));
#4287=DIRECTION('',(1.,0.,0.));
#4288=AXIS2_PLACEMENT_3D('',#4285,#4286,#4287);
#4289=CYLINDRICAL_SURFACE('',#4288,5.05000000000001);
#4290=CARTESIAN_POINT('',(50.,280.270515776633,7.5));
#4291=DIRECTION('',(0.,0.,1.));
#4292=DIRECTION('',(1.,0.,0.));
#4293=AXIS2_PLACEMENT_3D('',#4290,#4291,#4292);
#4294=CIRCLE('',#4293,5.05000000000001);
#4295=CARTESIAN_POINT('',(55.05,280.270515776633,7.5));
#4296=VERTEX_POINT('',#4295);
#4297=EDGE_CURVE('E1711',#4296,#4296,#4294,.T.);
#4298=ORIENTED_EDGE('',*,*,#4297,.F.);
#4299=EDGE_LOOP('',(#4298));
#4300=FACE_BOUND('',#4299,.T.);
#4301=ORIENTED_EDGE('',*,*,#42,.T.);
#4302=EDGE_LOOP('',(#4301));
#4303=FACE_BOUND('',#4302,.T.);
#4304=ADVANCED_FACE('F1735',(#4300,#4303),#4289,.F.);
#4305=CARTESIAN_POINT('',(0.,0.,7.5));
#4306=DIRECTION('',(0.,0.,1.));
#4307=DIRECTION('',(1.,0.,0.));
#4308=AXIS2_PLACEMENT_3D('',#4305,#4306,#4307);
#4309=PLANE('',#4308);
#4310=ORIENTED_EDGE('',*,*,#4297,.T.);
#4311=EDGE_LOOP('',(#4310));
#4312=FACE_BOUND('',#4311,.T.);
#4313=ADVANCED_FACE('F1730',(#4312),#4309,.T.);
#4314=CARTESIAN_POINT('',(50.,315.270539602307,-2.5));
#4315=DIRECTION('',(0.,0.,1.));
#4316=DIRECTION('',(1.,0.,0.));
#4317=AXIS2_PLACEMENT_3D('',#4314,#4315,#4316);
#4318=CYLINDRICAL_SURFACE('',#4317,6.05000000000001);
#4319=ORIENTED_EDGE('',*,*,#31,.T.);
#4320=EDGE_LOOP('',(#4319));
#4321=FACE_BOUND('',#4320,.T.);
#4322=ORIENTED_EDGE('',*,*,#1115,.F.);
#4323=EDGE_LOOP('',(#4322));
#4324=FACE_BOUND('',#4323,.T.);
#4325=ADVANCED_FACE('F1728',(#4321,#4324),#4318,.F.);
#4326=CLOSED_SHELL('',(#1102,#2164,#2186,#2203,#2220,#2237,#2254,#2271,#2288,#2305,#2322,#2339,
#2356,#2373,#2390,#2407,#2424,#2441,#2458,#2475,#2492,#2509,#2526,#2543,#2560,#2577,#2594,#2611,
#2628,#2645,#2662,#2679,#2696,#2713,#2730,#2747,#2764,#2781,#2798,#2815,#2832,#2849,#2866,#2883,
#2900,#2917,#2934,#2951,#2968,#2985,#3002,#3019,#3036,#3053,#3070,#3087,#3104,#3121,#3138,#3155,
#3172,#3189,#3206,#3223,#3240,#3257,#3274,#3291,#3308,#3325,#3342,#3359,#3376,#3393,#3410,#3427,
#3439,#3461,#3478,#3495,#3512,#3529,#3546,#3563,#3575,#3597,#3614,#3631,#3648,#3665,#3682,#3699,
#3711,#3733,#3750,#3767,#3784,#3801,#3818,#3835,#3847,#3869,#3886,#3903,#3920,#3937,#3954,#3971,
#3983,#4005,#4022,#4039,#4056,#4073,#4090,#4107,#4119,#4141,#4158,#4175,#4192,#4209,#4226,#4243,
#4255,#4275,#4284,#4304,#4313,#4325));
#4327=MANIFOLD_SOLID_BREP('B2',#4326);
#4328=ADVANCED_BREP_SHAPE_REPRESENTATION('',(#18,#4327),#14);
#4329=SHAPE_DEFINITION_REPRESENTATION(#9,#4328);
ENDSEC;
END-ISO-10303-21;
